VERSION 5.8 ;
BUSBITCHARS "[]" ;
DIVIDERCHAR "/" ;
UNITS
    DATABASE MICRONS 1000 ;
END UNITS

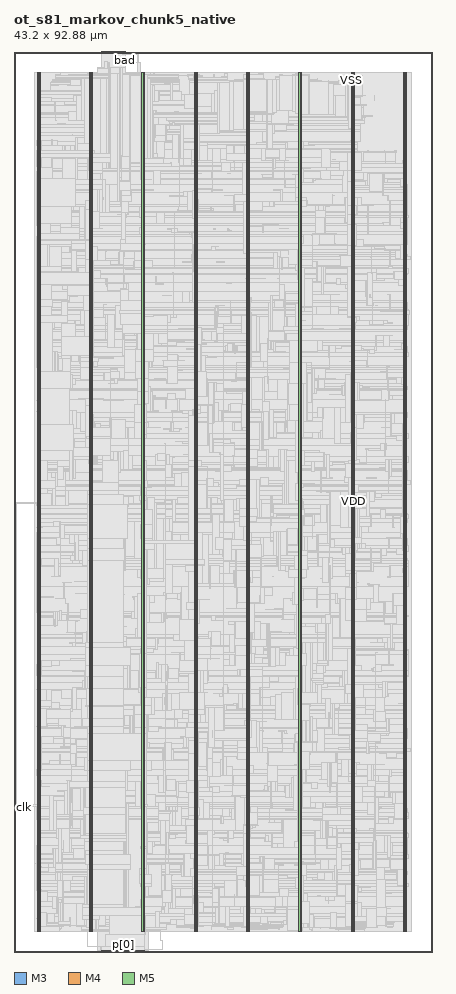
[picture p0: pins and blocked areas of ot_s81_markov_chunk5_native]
MACRO ot_s81_markov_chunk5_native
  FOREIGN ot_s81_markov_chunk5_native 0 0 ;
  CLASS BLOCK ;
  SIZE 43.2 BY 92.88 ;
  PIN bad
    DIRECTION OUTPUT ;
    USE SIGNAL ;
    PORT
      LAYER M3 ;
        RECT  11.448 92.736 11.466 92.88 ;
    END
  END bad
  PIN clk
    DIRECTION INPUT ;
    USE SIGNAL ;
    PORT
      LAYER M4 ;
        RECT  0 14.88 0.192 14.904 ;
    END
  END clk
  PIN p[0]
    DIRECTION INPUT ;
    USE SIGNAL ;
    PORT
      LAYER M3 ;
        RECT  11.304 0 11.322 0.144 ;
    END
  END p[0]
  PIN p[10]
    DIRECTION INPUT ;
    USE SIGNAL ;
    PORT
      LAYER M3 ;
        RECT  12.024 0 12.042 0.144 ;
    END
  END p[10]
  PIN p[11]
    DIRECTION INPUT ;
    USE SIGNAL ;
    PORT
      LAYER M5 ;
        RECT  12.048 0 12.072 0.192 ;
    END
  END p[11]
  PIN p[12]
    DIRECTION INPUT ;
    USE SIGNAL ;
    PORT
      LAYER M3 ;
        RECT  12.168 0 12.186 0.144 ;
    END
  END p[12]
  PIN p[13]
    DIRECTION INPUT ;
    USE SIGNAL ;
    PORT
      LAYER M5 ;
        RECT  12.192 0 12.216 0.192 ;
    END
  END p[13]
  PIN p[14]
    DIRECTION INPUT ;
    USE SIGNAL ;
    PORT
      LAYER M3 ;
        RECT  12.312 0 12.33 0.144 ;
    END
  END p[14]
  PIN p[15]
    DIRECTION INPUT ;
    USE SIGNAL ;
    PORT
      LAYER M5 ;
        RECT  12.336 0 12.36 0.192 ;
    END
  END p[15]
  PIN p[16]
    DIRECTION INPUT ;
    USE SIGNAL ;
    PORT
      LAYER M3 ;
        RECT  12.456 0 12.474 0.144 ;
    END
  END p[16]
  PIN p[17]
    DIRECTION INPUT ;
    USE SIGNAL ;
    PORT
      LAYER M5 ;
        RECT  12.48 0 12.504 0.192 ;
    END
  END p[17]
  PIN p[18]
    DIRECTION INPUT ;
    USE SIGNAL ;
    PORT
      LAYER M3 ;
        RECT  12.6 0 12.618 0.144 ;
    END
  END p[18]
  PIN p[19]
    DIRECTION INPUT ;
    USE SIGNAL ;
    PORT
      LAYER M5 ;
        RECT  12.624 0 12.648 0.192 ;
    END
  END p[19]
  PIN p[1]
    DIRECTION INPUT ;
    USE SIGNAL ;
    PORT
      LAYER M5 ;
        RECT  11.328 0 11.352 0.192 ;
    END
  END p[1]
  PIN p[20]
    DIRECTION INPUT ;
    USE SIGNAL ;
    PORT
      LAYER M3 ;
        RECT  12.744 0 12.762 0.144 ;
    END
  END p[20]
  PIN p[21]
    DIRECTION INPUT ;
    USE SIGNAL ;
    PORT
      LAYER M5 ;
        RECT  12.768 0 12.792 0.192 ;
    END
  END p[21]
  PIN p[22]
    DIRECTION INPUT ;
    USE SIGNAL ;
    PORT
      LAYER M3 ;
        RECT  12.888 0 12.906 0.144 ;
    END
  END p[22]
  PIN p[23]
    DIRECTION INPUT ;
    USE SIGNAL ;
    PORT
      LAYER M5 ;
        RECT  12.912 0 12.936 0.192 ;
    END
  END p[23]
  PIN p[24]
    DIRECTION INPUT ;
    USE SIGNAL ;
    PORT
      LAYER M3 ;
        RECT  13.032 0 13.05 0.144 ;
    END
  END p[24]
  PIN p[25]
    DIRECTION INPUT ;
    USE SIGNAL ;
    PORT
      LAYER M5 ;
        RECT  13.056 0 13.08 0.192 ;
    END
  END p[25]
  PIN p[26]
    DIRECTION INPUT ;
    USE SIGNAL ;
    PORT
      LAYER M3 ;
        RECT  13.176 0 13.194 0.144 ;
    END
  END p[26]
  PIN p[27]
    DIRECTION INPUT ;
    USE SIGNAL ;
    PORT
      LAYER M5 ;
        RECT  13.2 0 13.224 0.192 ;
    END
  END p[27]
  PIN p[28]
    DIRECTION INPUT ;
    USE SIGNAL ;
    PORT
      LAYER M3 ;
        RECT  13.32 0 13.338 0.144 ;
    END
  END p[28]
  PIN p[29]
    DIRECTION INPUT ;
    USE SIGNAL ;
    PORT
      LAYER M5 ;
        RECT  13.344 0 13.368 0.192 ;
    END
  END p[29]
  PIN p[2]
    DIRECTION INPUT ;
    USE SIGNAL ;
    PORT
      LAYER M3 ;
        RECT  11.448 0 11.466 0.144 ;
    END
  END p[2]
  PIN p[30]
    DIRECTION INPUT ;
    USE SIGNAL ;
    PORT
      LAYER M3 ;
        RECT  13.464 0 13.482 0.144 ;
    END
  END p[30]
  PIN p[31]
    DIRECTION INPUT ;
    USE SIGNAL ;
    PORT
      LAYER M5 ;
        RECT  13.488 0 13.512 0.192 ;
    END
  END p[31]
  PIN p[3]
    DIRECTION INPUT ;
    USE SIGNAL ;
    PORT
      LAYER M5 ;
        RECT  11.472 0 11.496 0.192 ;
    END
  END p[3]
  PIN p[4]
    DIRECTION INPUT ;
    USE SIGNAL ;
    PORT
      LAYER M3 ;
        RECT  11.592 0 11.61 0.144 ;
    END
  END p[4]
  PIN p[5]
    DIRECTION INPUT ;
    USE SIGNAL ;
    PORT
      LAYER M5 ;
        RECT  11.616 0 11.64 0.192 ;
    END
  END p[5]
  PIN p[6]
    DIRECTION INPUT ;
    USE SIGNAL ;
    PORT
      LAYER M3 ;
        RECT  11.736 0 11.754 0.144 ;
    END
  END p[6]
  PIN p[7]
    DIRECTION INPUT ;
    USE SIGNAL ;
    PORT
      LAYER M5 ;
        RECT  11.76 0 11.784 0.192 ;
    END
  END p[7]
  PIN p[8]
    DIRECTION INPUT ;
    USE SIGNAL ;
    PORT
      LAYER M3 ;
        RECT  11.88 0 11.898 0.144 ;
    END
  END p[8]
  PIN p[9]
    DIRECTION INPUT ;
    USE SIGNAL ;
    PORT
      LAYER M5 ;
        RECT  11.904 0 11.928 0.192 ;
    END
  END p[9]
  PIN rst_n
    DIRECTION INPUT ;
    USE SIGNAL ;
    PORT
      LAYER M4 ;
        RECT  0 15.024 0.192 15.048 ;
    END
  END rst_n
  PIN sum[0]
    DIRECTION INPUT ;
    USE SIGNAL ;
    PORT
      LAYER M3 ;
        RECT  9 0 9.018 0.144 ;
    END
  END sum[0]
  PIN sum[10]
    DIRECTION INPUT ;
    USE SIGNAL ;
    PORT
      LAYER M3 ;
        RECT  9.72 0 9.738 0.144 ;
    END
  END sum[10]
  PIN sum[11]
    DIRECTION INPUT ;
    USE SIGNAL ;
    PORT
      LAYER M5 ;
        RECT  9.744 0 9.768 0.192 ;
    END
  END sum[11]
  PIN sum[12]
    DIRECTION INPUT ;
    USE SIGNAL ;
    PORT
      LAYER M3 ;
        RECT  9.864 0 9.882 0.144 ;
    END
  END sum[12]
  PIN sum[13]
    DIRECTION INPUT ;
    USE SIGNAL ;
    PORT
      LAYER M5 ;
        RECT  9.888 0 9.912 0.192 ;
    END
  END sum[13]
  PIN sum[14]
    DIRECTION INPUT ;
    USE SIGNAL ;
    PORT
      LAYER M3 ;
        RECT  10.008 0 10.026 0.144 ;
    END
  END sum[14]
  PIN sum[15]
    DIRECTION INPUT ;
    USE SIGNAL ;
    PORT
      LAYER M5 ;
        RECT  10.032 0 10.056 0.192 ;
    END
  END sum[15]
  PIN sum[16]
    DIRECTION INPUT ;
    USE SIGNAL ;
    PORT
      LAYER M3 ;
        RECT  10.152 0 10.17 0.144 ;
    END
  END sum[16]
  PIN sum[17]
    DIRECTION INPUT ;
    USE SIGNAL ;
    PORT
      LAYER M5 ;
        RECT  10.176 0 10.2 0.192 ;
    END
  END sum[17]
  PIN sum[18]
    DIRECTION INPUT ;
    USE SIGNAL ;
    PORT
      LAYER M3 ;
        RECT  10.296 0 10.314 0.144 ;
    END
  END sum[18]
  PIN sum[19]
    DIRECTION INPUT ;
    USE SIGNAL ;
    PORT
      LAYER M5 ;
        RECT  10.32 0 10.344 0.192 ;
    END
  END sum[19]
  PIN sum[1]
    DIRECTION INPUT ;
    USE SIGNAL ;
    PORT
      LAYER M5 ;
        RECT  9.024 0 9.048 0.192 ;
    END
  END sum[1]
  PIN sum[20]
    DIRECTION INPUT ;
    USE SIGNAL ;
    PORT
      LAYER M3 ;
        RECT  10.44 0 10.458 0.144 ;
    END
  END sum[20]
  PIN sum[21]
    DIRECTION INPUT ;
    USE SIGNAL ;
    PORT
      LAYER M5 ;
        RECT  10.464 0 10.488 0.192 ;
    END
  END sum[21]
  PIN sum[22]
    DIRECTION INPUT ;
    USE SIGNAL ;
    PORT
      LAYER M3 ;
        RECT  10.584 0 10.602 0.144 ;
    END
  END sum[22]
  PIN sum[23]
    DIRECTION INPUT ;
    USE SIGNAL ;
    PORT
      LAYER M5 ;
        RECT  10.608 0 10.632 0.192 ;
    END
  END sum[23]
  PIN sum[24]
    DIRECTION INPUT ;
    USE SIGNAL ;
    PORT
      LAYER M3 ;
        RECT  10.728 0 10.746 0.144 ;
    END
  END sum[24]
  PIN sum[25]
    DIRECTION INPUT ;
    USE SIGNAL ;
    PORT
      LAYER M5 ;
        RECT  10.752 0 10.776 0.192 ;
    END
  END sum[25]
  PIN sum[26]
    DIRECTION INPUT ;
    USE SIGNAL ;
    PORT
      LAYER M3 ;
        RECT  10.872 0 10.89 0.144 ;
    END
  END sum[26]
  PIN sum[27]
    DIRECTION INPUT ;
    USE SIGNAL ;
    PORT
      LAYER M5 ;
        RECT  10.896 0 10.92 0.192 ;
    END
  END sum[27]
  PIN sum[28]
    DIRECTION INPUT ;
    USE SIGNAL ;
    PORT
      LAYER M3 ;
        RECT  11.016 0 11.034 0.144 ;
    END
  END sum[28]
  PIN sum[29]
    DIRECTION INPUT ;
    USE SIGNAL ;
    PORT
      LAYER M5 ;
        RECT  11.04 0 11.064 0.192 ;
    END
  END sum[29]
  PIN sum[2]
    DIRECTION INPUT ;
    USE SIGNAL ;
    PORT
      LAYER M3 ;
        RECT  9.144 0 9.162 0.144 ;
    END
  END sum[2]
  PIN sum[30]
    DIRECTION INPUT ;
    USE SIGNAL ;
    PORT
      LAYER M3 ;
        RECT  11.16 0 11.178 0.144 ;
    END
  END sum[30]
  PIN sum[31]
    DIRECTION INPUT ;
    USE SIGNAL ;
    PORT
      LAYER M5 ;
        RECT  11.184 0 11.208 0.192 ;
    END
  END sum[31]
  PIN sum[3]
    DIRECTION INPUT ;
    USE SIGNAL ;
    PORT
      LAYER M5 ;
        RECT  9.168 0 9.192 0.192 ;
    END
  END sum[3]
  PIN sum[4]
    DIRECTION INPUT ;
    USE SIGNAL ;
    PORT
      LAYER M3 ;
        RECT  9.288 0 9.306 0.144 ;
    END
  END sum[4]
  PIN sum[5]
    DIRECTION INPUT ;
    USE SIGNAL ;
    PORT
      LAYER M5 ;
        RECT  9.312 0 9.336 0.192 ;
    END
  END sum[5]
  PIN sum[6]
    DIRECTION INPUT ;
    USE SIGNAL ;
    PORT
      LAYER M3 ;
        RECT  9.432 0 9.45 0.144 ;
    END
  END sum[6]
  PIN sum[7]
    DIRECTION INPUT ;
    USE SIGNAL ;
    PORT
      LAYER M5 ;
        RECT  9.456 0 9.48 0.192 ;
    END
  END sum[7]
  PIN sum[8]
    DIRECTION INPUT ;
    USE SIGNAL ;
    PORT
      LAYER M3 ;
        RECT  9.576 0 9.594 0.144 ;
    END
  END sum[8]
  PIN sum[9]
    DIRECTION INPUT ;
    USE SIGNAL ;
    PORT
      LAYER M5 ;
        RECT  9.6 0 9.624 0.192 ;
    END
  END sum[9]
  PIN vin
    DIRECTION INPUT ;
    USE SIGNAL ;
    PORT
      LAYER M4 ;
        RECT  0 15.168 0.192 15.192 ;
    END
  END vin
  PIN vout
    DIRECTION OUTPUT ;
    USE SIGNAL ;
    PORT
      LAYER M3 ;
        RECT  11.304 92.736 11.322 92.88 ;
    END
  END vout
  PIN y[0]
    DIRECTION OUTPUT ;
    USE SIGNAL ;
    PORT
      LAYER M3 ;
        RECT  9 92.736 9.018 92.88 ;
    END
  END y[0]
  PIN y[10]
    DIRECTION OUTPUT ;
    USE SIGNAL ;
    PORT
      LAYER M3 ;
        RECT  9.72 92.736 9.738 92.88 ;
    END
  END y[10]
  PIN y[11]
    DIRECTION OUTPUT ;
    USE SIGNAL ;
    PORT
      LAYER M5 ;
        RECT  9.744 92.688 9.768 92.88 ;
    END
  END y[11]
  PIN y[12]
    DIRECTION OUTPUT ;
    USE SIGNAL ;
    PORT
      LAYER M3 ;
        RECT  9.864 92.736 9.882 92.88 ;
    END
  END y[12]
  PIN y[13]
    DIRECTION OUTPUT ;
    USE SIGNAL ;
    PORT
      LAYER M5 ;
        RECT  9.888 92.688 9.912 92.88 ;
    END
  END y[13]
  PIN y[14]
    DIRECTION OUTPUT ;
    USE SIGNAL ;
    PORT
      LAYER M3 ;
        RECT  10.008 92.736 10.026 92.88 ;
    END
  END y[14]
  PIN y[15]
    DIRECTION OUTPUT ;
    USE SIGNAL ;
    PORT
      LAYER M5 ;
        RECT  10.032 92.688 10.056 92.88 ;
    END
  END y[15]
  PIN y[16]
    DIRECTION OUTPUT ;
    USE SIGNAL ;
    PORT
      LAYER M3 ;
        RECT  10.152 92.736 10.17 92.88 ;
    END
  END y[16]
  PIN y[17]
    DIRECTION OUTPUT ;
    USE SIGNAL ;
    PORT
      LAYER M5 ;
        RECT  10.176 92.688 10.2 92.88 ;
    END
  END y[17]
  PIN y[18]
    DIRECTION OUTPUT ;
    USE SIGNAL ;
    PORT
      LAYER M3 ;
        RECT  10.296 92.736 10.314 92.88 ;
    END
  END y[18]
  PIN y[19]
    DIRECTION OUTPUT ;
    USE SIGNAL ;
    PORT
      LAYER M5 ;
        RECT  10.32 92.688 10.344 92.88 ;
    END
  END y[19]
  PIN y[1]
    DIRECTION OUTPUT ;
    USE SIGNAL ;
    PORT
      LAYER M5 ;
        RECT  9.024 92.688 9.048 92.88 ;
    END
  END y[1]
  PIN y[20]
    DIRECTION OUTPUT ;
    USE SIGNAL ;
    PORT
      LAYER M3 ;
        RECT  10.44 92.736 10.458 92.88 ;
    END
  END y[20]
  PIN y[21]
    DIRECTION OUTPUT ;
    USE SIGNAL ;
    PORT
      LAYER M5 ;
        RECT  10.464 92.688 10.488 92.88 ;
    END
  END y[21]
  PIN y[22]
    DIRECTION OUTPUT ;
    USE SIGNAL ;
    PORT
      LAYER M3 ;
        RECT  10.584 92.736 10.602 92.88 ;
    END
  END y[22]
  PIN y[23]
    DIRECTION OUTPUT ;
    USE SIGNAL ;
    PORT
      LAYER M5 ;
        RECT  10.608 92.688 10.632 92.88 ;
    END
  END y[23]
  PIN y[24]
    DIRECTION OUTPUT ;
    USE SIGNAL ;
    PORT
      LAYER M3 ;
        RECT  10.728 92.736 10.746 92.88 ;
    END
  END y[24]
  PIN y[25]
    DIRECTION OUTPUT ;
    USE SIGNAL ;
    PORT
      LAYER M5 ;
        RECT  10.752 92.688 10.776 92.88 ;
    END
  END y[25]
  PIN y[26]
    DIRECTION OUTPUT ;
    USE SIGNAL ;
    PORT
      LAYER M3 ;
        RECT  10.872 92.736 10.89 92.88 ;
    END
  END y[26]
  PIN y[27]
    DIRECTION OUTPUT ;
    USE SIGNAL ;
    PORT
      LAYER M5 ;
        RECT  10.896 92.688 10.92 92.88 ;
    END
  END y[27]
  PIN y[28]
    DIRECTION OUTPUT ;
    USE SIGNAL ;
    PORT
      LAYER M3 ;
        RECT  11.016 92.736 11.034 92.88 ;
    END
  END y[28]
  PIN y[29]
    DIRECTION OUTPUT ;
    USE SIGNAL ;
    PORT
      LAYER M5 ;
        RECT  11.04 92.688 11.064 92.88 ;
    END
  END y[29]
  PIN y[2]
    DIRECTION OUTPUT ;
    USE SIGNAL ;
    PORT
      LAYER M3 ;
        RECT  9.144 92.736 9.162 92.88 ;
    END
  END y[2]
  PIN y[30]
    DIRECTION OUTPUT ;
    USE SIGNAL ;
    PORT
      LAYER M3 ;
        RECT  11.16 92.736 11.178 92.88 ;
    END
  END y[30]
  PIN y[31]
    DIRECTION OUTPUT ;
    USE SIGNAL ;
    PORT
      LAYER M5 ;
        RECT  11.184 92.688 11.208 92.88 ;
    END
  END y[31]
  PIN y[3]
    DIRECTION OUTPUT ;
    USE SIGNAL ;
    PORT
      LAYER M5 ;
        RECT  9.168 92.688 9.192 92.88 ;
    END
  END y[3]
  PIN y[4]
    DIRECTION OUTPUT ;
    USE SIGNAL ;
    PORT
      LAYER M3 ;
        RECT  9.288 92.736 9.306 92.88 ;
    END
  END y[4]
  PIN y[5]
    DIRECTION OUTPUT ;
    USE SIGNAL ;
    PORT
      LAYER M5 ;
        RECT  9.312 92.688 9.336 92.88 ;
    END
  END y[5]
  PIN y[6]
    DIRECTION OUTPUT ;
    USE SIGNAL ;
    PORT
      LAYER M3 ;
        RECT  9.432 92.736 9.45 92.88 ;
    END
  END y[6]
  PIN y[7]
    DIRECTION OUTPUT ;
    USE SIGNAL ;
    PORT
      LAYER M5 ;
        RECT  9.456 92.688 9.48 92.88 ;
    END
  END y[7]
  PIN y[8]
    DIRECTION OUTPUT ;
    USE SIGNAL ;
    PORT
      LAYER M3 ;
        RECT  9.576 92.736 9.594 92.88 ;
    END
  END y[8]
  PIN y[9]
    DIRECTION OUTPUT ;
    USE SIGNAL ;
    PORT
      LAYER M5 ;
        RECT  9.6 92.688 9.624 92.88 ;
    END
  END y[9]
  PIN VDD
    DIRECTION INOUT ;
    USE POWER ;
    PORT
      LAYER M5 ;
        RECT  40.392 2.151 40.512 90.729 ;
        RECT  34.992 2.151 35.112 90.729 ;
        RECT  29.592 2.151 29.712 90.729 ;
        RECT  24.192 2.151 24.312 90.729 ;
        RECT  18.792 2.151 18.912 90.729 ;
        RECT  13.392 2.151 13.512 90.729 ;
        RECT  7.992 2.151 8.112 90.729 ;
        RECT  2.592 2.151 2.712 90.729 ;
    END
  END VDD
  PIN VSS
    DIRECTION INOUT ;
    USE GROUND ;
    PORT
      LAYER M5 ;
        RECT  40.2 2.137 40.32 90.743 ;
        RECT  34.8 2.137 34.92 90.743 ;
        RECT  29.4 2.137 29.52 90.743 ;
        RECT  24 2.137 24.12 90.743 ;
        RECT  18.6 2.137 18.72 90.743 ;
        RECT  13.2 2.137 13.32 90.743 ;
        RECT  7.8 2.137 7.92 90.743 ;
        RECT  2.4 2.137 2.52 90.743 ;
    END
  END VSS
  # OT_OBS_CLOSED layer=M5 d_um=1.536 added=399
  OBS
    LAYER RVTN ;
     RECT  2.16 2.16 41.04 2.295 ;
     RECT  2.16 2.565 41.04 2.835 ;
     RECT  2.16 3.105 41.04 3.375 ;
     RECT  2.16 3.645 41.04 3.915 ;
     RECT  2.16 4.185 41.04 4.455 ;
     RECT  2.16 4.725 41.04 4.995 ;
     RECT  2.16 5.265 41.04 5.535 ;
     RECT  2.16 5.805 41.04 6.075 ;
     RECT  2.16 6.345 41.04 6.615 ;
     RECT  2.16 6.885 41.04 7.155 ;
     RECT  2.16 7.425 41.04 7.695 ;
     RECT  2.16 7.965 41.04 8.235 ;
     RECT  2.16 8.505 41.04 8.775 ;
     RECT  2.16 9.045 41.04 9.315 ;
     RECT  2.16 9.585 41.04 9.855 ;
     RECT  2.16 10.125 41.04 10.395 ;
     RECT  2.16 10.665 41.04 10.935 ;
     RECT  2.16 11.205 41.04 11.475 ;
     RECT  2.16 11.745 41.04 12.015 ;
     RECT  2.16 12.285 41.04 12.555 ;
     RECT  2.16 12.825 41.04 13.095 ;
     RECT  2.16 13.365 41.04 13.635 ;
     RECT  2.16 13.905 41.04 14.175 ;
     RECT  2.16 14.445 41.04 14.715 ;
     RECT  2.16 14.985 41.04 15.255 ;
     RECT  2.16 15.525 41.04 15.795 ;
     RECT  2.16 16.065 41.04 16.335 ;
     RECT  2.16 16.605 41.04 16.875 ;
     RECT  2.16 17.145 41.04 17.415 ;
     RECT  2.16 17.685 41.04 17.955 ;
     RECT  2.16 18.225 41.04 18.495 ;
     RECT  2.16 18.765 41.04 19.035 ;
     RECT  2.16 19.305 41.04 19.575 ;
     RECT  2.16 19.845 41.04 20.115 ;
     RECT  2.16 20.385 41.04 20.655 ;
     RECT  2.16 20.925 41.04 21.195 ;
     RECT  2.16 21.465 41.04 21.735 ;
     RECT  2.16 22.005 41.04 22.275 ;
     RECT  2.16 22.545 41.04 22.815 ;
     RECT  2.16 23.085 41.04 23.355 ;
     RECT  2.16 23.625 41.04 23.895 ;
     RECT  2.16 24.165 41.04 24.435 ;
     RECT  2.16 24.705 41.04 24.975 ;
     RECT  2.16 25.245 41.04 25.515 ;
     RECT  2.16 25.785 41.04 26.055 ;
     RECT  2.16 26.325 41.04 26.595 ;
     RECT  2.16 26.865 41.04 27.135 ;
     RECT  2.16 27.405 41.04 27.675 ;
     RECT  2.16 27.945 41.04 28.215 ;
     RECT  2.16 28.485 41.04 28.755 ;
     RECT  2.16 29.025 41.04 29.295 ;
     RECT  2.16 29.565 41.04 29.835 ;
     RECT  2.16 30.105 41.04 30.375 ;
     RECT  2.16 30.645 41.04 30.915 ;
     RECT  2.16 31.185 41.04 31.455 ;
     RECT  2.16 31.725 41.04 31.995 ;
     RECT  2.16 32.265 41.04 32.535 ;
     RECT  2.16 32.805 41.04 33.075 ;
     RECT  2.16 33.345 41.04 33.615 ;
     RECT  2.16 33.885 41.04 34.155 ;
     RECT  2.16 34.425 41.04 34.695 ;
     RECT  2.16 34.965 41.04 35.235 ;
     RECT  2.16 35.505 41.04 35.775 ;
     RECT  2.16 36.045 41.04 36.315 ;
     RECT  2.16 36.585 41.04 36.855 ;
     RECT  2.16 37.125 41.04 37.395 ;
     RECT  2.16 37.665 41.04 37.935 ;
     RECT  2.16 38.205 41.04 38.475 ;
     RECT  2.16 38.745 41.04 39.015 ;
     RECT  2.16 39.285 41.04 39.555 ;
     RECT  2.16 39.825 41.04 40.095 ;
     RECT  2.16 40.365 41.04 40.635 ;
     RECT  2.16 40.905 41.04 41.175 ;
     RECT  2.16 41.445 41.04 41.715 ;
     RECT  2.16 41.985 41.04 42.255 ;
     RECT  2.16 42.525 41.04 42.795 ;
     RECT  2.16 43.065 41.04 43.335 ;
     RECT  2.16 43.605 41.04 43.875 ;
     RECT  2.16 44.145 41.04 44.415 ;
     RECT  2.16 44.685 41.04 44.955 ;
     RECT  2.16 45.225 41.04 45.495 ;
     RECT  2.16 45.765 41.04 46.035 ;
     RECT  2.16 46.305 41.04 46.575 ;
     RECT  2.16 46.845 41.04 47.115 ;
     RECT  2.16 47.385 41.04 47.655 ;
     RECT  2.16 47.925 41.04 48.195 ;
     RECT  2.16 48.465 41.04 48.735 ;
     RECT  2.16 49.005 41.04 49.275 ;
     RECT  2.16 49.545 41.04 49.815 ;
     RECT  2.16 50.085 41.04 50.355 ;
     RECT  2.16 50.625 41.04 50.895 ;
     RECT  2.16 51.165 41.04 51.435 ;
     RECT  2.16 51.705 41.04 51.975 ;
     RECT  2.16 52.245 41.04 52.515 ;
     RECT  2.16 52.785 41.04 53.055 ;
     RECT  2.16 53.325 41.04 53.595 ;
     RECT  2.16 53.865 41.04 54.135 ;
     RECT  2.16 54.405 41.04 54.675 ;
     RECT  2.16 54.945 41.04 55.215 ;
     RECT  2.16 55.485 41.04 55.755 ;
     RECT  2.16 56.025 41.04 56.295 ;
     RECT  2.16 56.565 41.04 56.835 ;
     RECT  2.16 57.105 41.04 57.375 ;
     RECT  2.16 57.645 41.04 57.915 ;
     RECT  2.16 58.185 41.04 58.455 ;
     RECT  2.16 58.725 41.04 58.995 ;
     RECT  2.16 59.265 41.04 59.535 ;
     RECT  2.16 59.805 41.04 60.075 ;
     RECT  2.16 60.345 41.04 60.615 ;
     RECT  2.16 60.885 41.04 61.155 ;
     RECT  2.16 61.425 41.04 61.695 ;
     RECT  2.16 61.965 41.04 62.235 ;
     RECT  2.16 62.505 41.04 62.775 ;
     RECT  2.16 63.045 41.04 63.315 ;
     RECT  2.16 63.585 41.04 63.855 ;
     RECT  2.16 64.125 41.04 64.395 ;
     RECT  2.16 64.665 41.04 64.935 ;
     RECT  2.16 65.205 41.04 65.475 ;
     RECT  2.16 65.745 41.04 66.015 ;
     RECT  2.16 66.285 41.04 66.555 ;
     RECT  2.16 66.825 41.04 67.095 ;
     RECT  2.16 67.365 41.04 67.635 ;
     RECT  2.16 67.905 41.04 68.175 ;
     RECT  2.16 68.445 41.04 68.715 ;
     RECT  2.16 68.985 41.04 69.255 ;
     RECT  2.16 69.525 41.04 69.795 ;
     RECT  2.16 70.065 41.04 70.335 ;
     RECT  2.16 70.605 41.04 70.875 ;
     RECT  2.16 71.145 41.04 71.415 ;
     RECT  2.16 71.685 41.04 71.955 ;
     RECT  2.16 72.225 41.04 72.495 ;
     RECT  2.16 72.765 41.04 73.035 ;
     RECT  2.16 73.305 41.04 73.575 ;
     RECT  2.16 73.845 41.04 74.115 ;
     RECT  2.16 74.385 41.04 74.655 ;
     RECT  2.16 74.925 41.04 75.195 ;
     RECT  2.16 75.465 41.04 75.735 ;
     RECT  2.16 76.005 41.04 76.275 ;
     RECT  2.16 76.545 41.04 76.815 ;
     RECT  2.16 77.085 41.04 77.355 ;
     RECT  2.16 77.625 41.04 77.895 ;
     RECT  2.16 78.165 41.04 78.435 ;
     RECT  2.16 78.705 41.04 78.975 ;
     RECT  2.16 79.245 41.04 79.515 ;
     RECT  2.16 79.785 41.04 80.055 ;
     RECT  2.16 80.325 41.04 80.595 ;
     RECT  2.16 80.865 41.04 81.135 ;
     RECT  2.16 81.405 41.04 81.675 ;
     RECT  2.16 81.945 41.04 82.215 ;
     RECT  2.16 82.485 41.04 82.755 ;
     RECT  2.16 83.025 41.04 83.295 ;
     RECT  2.16 83.565 41.04 83.835 ;
     RECT  2.16 84.105 41.04 84.375 ;
     RECT  2.16 84.645 41.04 84.915 ;
     RECT  2.16 85.185 41.04 85.455 ;
     RECT  2.16 85.725 41.04 85.995 ;
     RECT  2.16 86.265 41.04 86.535 ;
     RECT  2.16 86.805 41.04 87.075 ;
     RECT  2.16 87.345 41.04 87.615 ;
     RECT  2.16 87.885 41.04 88.155 ;
     RECT  2.16 88.425 41.04 88.695 ;
     RECT  2.16 88.965 41.04 89.235 ;
     RECT  2.16 89.505 41.04 89.775 ;
     RECT  2.16 90.045 41.04 90.315 ;
     RECT  2.16 90.585 41.04 90.72 ;
    LAYER RVTP ;
     RECT  2.16 2.295 41.04 2.565 ;
     RECT  2.16 2.835 41.04 3.105 ;
     RECT  2.16 3.375 41.04 3.645 ;
     RECT  2.16 3.915 41.04 4.185 ;
     RECT  2.16 4.455 41.04 4.725 ;
     RECT  2.16 4.995 41.04 5.265 ;
     RECT  2.16 5.535 41.04 5.805 ;
     RECT  2.16 6.075 41.04 6.345 ;
     RECT  2.16 6.615 41.04 6.885 ;
     RECT  2.16 7.155 41.04 7.425 ;
     RECT  2.16 7.695 41.04 7.965 ;
     RECT  2.16 8.235 41.04 8.505 ;
     RECT  2.16 8.775 41.04 9.045 ;
     RECT  2.16 9.315 41.04 9.585 ;
     RECT  2.16 9.855 41.04 10.125 ;
     RECT  2.16 10.395 41.04 10.665 ;
     RECT  2.16 10.935 41.04 11.205 ;
     RECT  2.16 11.475 41.04 11.745 ;
     RECT  2.16 12.015 41.04 12.285 ;
     RECT  2.16 12.555 41.04 12.825 ;
     RECT  2.16 13.095 41.04 13.365 ;
     RECT  2.16 13.635 41.04 13.905 ;
     RECT  2.16 14.175 41.04 14.445 ;
     RECT  2.16 14.715 41.04 14.985 ;
     RECT  2.16 15.255 41.04 15.525 ;
     RECT  2.16 15.795 41.04 16.065 ;
     RECT  2.16 16.335 41.04 16.605 ;
     RECT  2.16 16.875 41.04 17.145 ;
     RECT  2.16 17.415 41.04 17.685 ;
     RECT  2.16 17.955 41.04 18.225 ;
     RECT  2.16 18.495 41.04 18.765 ;
     RECT  2.16 19.035 41.04 19.305 ;
     RECT  2.16 19.575 41.04 19.845 ;
     RECT  2.16 20.115 41.04 20.385 ;
     RECT  2.16 20.655 41.04 20.925 ;
     RECT  2.16 21.195 41.04 21.465 ;
     RECT  2.16 21.735 41.04 22.005 ;
     RECT  2.16 22.275 41.04 22.545 ;
     RECT  2.16 22.815 41.04 23.085 ;
     RECT  2.16 23.355 41.04 23.625 ;
     RECT  2.16 23.895 41.04 24.165 ;
     RECT  2.16 24.435 41.04 24.705 ;
     RECT  2.16 24.975 41.04 25.245 ;
     RECT  2.16 25.515 41.04 25.785 ;
     RECT  2.16 26.055 41.04 26.325 ;
     RECT  2.16 26.595 41.04 26.865 ;
     RECT  2.16 27.135 41.04 27.405 ;
     RECT  2.16 27.675 41.04 27.945 ;
     RECT  2.16 28.215 41.04 28.485 ;
     RECT  2.16 28.755 41.04 29.025 ;
     RECT  2.16 29.295 41.04 29.565 ;
     RECT  2.16 29.835 41.04 30.105 ;
     RECT  2.16 30.375 41.04 30.645 ;
     RECT  2.16 30.915 41.04 31.185 ;
     RECT  2.16 31.455 41.04 31.725 ;
     RECT  2.16 31.995 41.04 32.265 ;
     RECT  2.16 32.535 41.04 32.805 ;
     RECT  2.16 33.075 41.04 33.345 ;
     RECT  2.16 33.615 41.04 33.885 ;
     RECT  2.16 34.155 41.04 34.425 ;
     RECT  2.16 34.695 41.04 34.965 ;
     RECT  2.16 35.235 41.04 35.505 ;
     RECT  2.16 35.775 41.04 36.045 ;
     RECT  2.16 36.315 41.04 36.585 ;
     RECT  2.16 36.855 41.04 37.125 ;
     RECT  2.16 37.395 41.04 37.665 ;
     RECT  2.16 37.935 41.04 38.205 ;
     RECT  2.16 38.475 41.04 38.745 ;
     RECT  2.16 39.015 41.04 39.285 ;
     RECT  2.16 39.555 41.04 39.825 ;
     RECT  2.16 40.095 41.04 40.365 ;
     RECT  2.16 40.635 41.04 40.905 ;
     RECT  2.16 41.175 41.04 41.445 ;
     RECT  2.16 41.715 41.04 41.985 ;
     RECT  2.16 42.255 41.04 42.525 ;
     RECT  2.16 42.795 41.04 43.065 ;
     RECT  2.16 43.335 41.04 43.605 ;
     RECT  2.16 43.875 41.04 44.145 ;
     RECT  2.16 44.415 41.04 44.685 ;
     RECT  2.16 44.955 41.04 45.225 ;
     RECT  2.16 45.495 41.04 45.765 ;
     RECT  2.16 46.035 41.04 46.305 ;
     RECT  2.16 46.575 41.04 46.845 ;
     RECT  2.16 47.115 41.04 47.385 ;
     RECT  2.16 47.655 41.04 47.925 ;
     RECT  2.16 48.195 41.04 48.465 ;
     RECT  2.16 48.735 41.04 49.005 ;
     RECT  2.16 49.275 41.04 49.545 ;
     RECT  2.16 49.815 41.04 50.085 ;
     RECT  2.16 50.355 41.04 50.625 ;
     RECT  2.16 50.895 41.04 51.165 ;
     RECT  2.16 51.435 41.04 51.705 ;
     RECT  2.16 51.975 41.04 52.245 ;
     RECT  2.16 52.515 41.04 52.785 ;
     RECT  2.16 53.055 41.04 53.325 ;
     RECT  2.16 53.595 41.04 53.865 ;
     RECT  2.16 54.135 41.04 54.405 ;
     RECT  2.16 54.675 41.04 54.945 ;
     RECT  2.16 55.215 41.04 55.485 ;
     RECT  2.16 55.755 41.04 56.025 ;
     RECT  2.16 56.295 41.04 56.565 ;
     RECT  2.16 56.835 41.04 57.105 ;
     RECT  2.16 57.375 41.04 57.645 ;
     RECT  2.16 57.915 41.04 58.185 ;
     RECT  2.16 58.455 41.04 58.725 ;
     RECT  2.16 58.995 41.04 59.265 ;
     RECT  2.16 59.535 41.04 59.805 ;
     RECT  2.16 60.075 41.04 60.345 ;
     RECT  2.16 60.615 41.04 60.885 ;
     RECT  2.16 61.155 41.04 61.425 ;
     RECT  2.16 61.695 41.04 61.965 ;
     RECT  2.16 62.235 41.04 62.505 ;
     RECT  2.16 62.775 41.04 63.045 ;
     RECT  2.16 63.315 41.04 63.585 ;
     RECT  2.16 63.855 41.04 64.125 ;
     RECT  2.16 64.395 41.04 64.665 ;
     RECT  2.16 64.935 41.04 65.205 ;
     RECT  2.16 65.475 41.04 65.745 ;
     RECT  2.16 66.015 41.04 66.285 ;
     RECT  2.16 66.555 41.04 66.825 ;
     RECT  2.16 67.095 41.04 67.365 ;
     RECT  2.16 67.635 41.04 67.905 ;
     RECT  2.16 68.175 41.04 68.445 ;
     RECT  2.16 68.715 41.04 68.985 ;
     RECT  2.16 69.255 41.04 69.525 ;
     RECT  2.16 69.795 41.04 70.065 ;
     RECT  2.16 70.335 41.04 70.605 ;
     RECT  2.16 70.875 41.04 71.145 ;
     RECT  2.16 71.415 41.04 71.685 ;
     RECT  2.16 71.955 41.04 72.225 ;
     RECT  2.16 72.495 41.04 72.765 ;
     RECT  2.16 73.035 41.04 73.305 ;
     RECT  2.16 73.575 41.04 73.845 ;
     RECT  2.16 74.115 41.04 74.385 ;
     RECT  2.16 74.655 41.04 74.925 ;
     RECT  2.16 75.195 41.04 75.465 ;
     RECT  2.16 75.735 41.04 76.005 ;
     RECT  2.16 76.275 41.04 76.545 ;
     RECT  2.16 76.815 41.04 77.085 ;
     RECT  2.16 77.355 41.04 77.625 ;
     RECT  2.16 77.895 41.04 78.165 ;
     RECT  2.16 78.435 41.04 78.705 ;
     RECT  2.16 78.975 41.04 79.245 ;
     RECT  2.16 79.515 41.04 79.785 ;
     RECT  2.16 80.055 41.04 80.325 ;
     RECT  2.16 80.595 41.04 80.865 ;
     RECT  2.16 81.135 41.04 81.405 ;
     RECT  2.16 81.675 41.04 81.945 ;
     RECT  2.16 82.215 41.04 82.485 ;
     RECT  2.16 82.755 41.04 83.025 ;
     RECT  2.16 83.295 41.04 83.565 ;
     RECT  2.16 83.835 41.04 84.105 ;
     RECT  2.16 84.375 41.04 84.645 ;
     RECT  2.16 84.915 41.04 85.185 ;
     RECT  2.16 85.455 41.04 85.725 ;
     RECT  2.16 85.995 41.04 86.265 ;
     RECT  2.16 86.535 41.04 86.805 ;
     RECT  2.16 87.075 41.04 87.345 ;
     RECT  2.16 87.615 41.04 87.885 ;
     RECT  2.16 88.155 41.04 88.425 ;
     RECT  2.16 88.695 41.04 88.965 ;
     RECT  2.16 89.235 41.04 89.505 ;
     RECT  2.16 89.775 41.04 90.045 ;
     RECT  2.16 90.315 41.04 90.585 ;
    LAYER M1 ;
     RECT  2.16 2.151 41.04 90.729 ;
    LAYER M2 ;
     RECT  2.16 2.151 7.555 90.729 ;
     RECT  7.555 2.106 7.691 90.729 ;
     RECT  7.691 2.151 8.851 90.729 ;
     RECT  8.851 2.106 9.211 90.729 ;
     RECT  9.211 1.728 9.319 90.729 ;
     RECT  8.635 0.144 9.599 0.162 ;
     RECT  9.319 1.152 10.031 90.729 ;
     RECT  10.031 1.152 10.651 1.242 ;
     RECT  10.651 0.531 10.895 1.242 ;
     RECT  10.895 1.152 10.939 1.242 ;
     RECT  10.031 2.106 10.939 90.729 ;
     RECT  10.579 91.791 11.011 91.809 ;
     RECT  10.939 1.152 11.155 90.729 ;
     RECT  11.011 91.791 11.155 91.89 ;
     RECT  11.155 1.152 11.183 91.89 ;
     RECT  11.183 2.106 11.255 91.89 ;
     RECT  11.255 91.791 11.399 91.89 ;
     RECT  11.183 1.152 11.759 1.242 ;
     RECT  11.255 2.106 11.759 90.774 ;
     RECT  11.443 0.144 11.939 0.234 ;
     RECT  11.759 1.152 11.939 1.17 ;
     RECT  11.759 2.151 12.335 90.774 ;
     RECT  12.739 1.152 12.839 1.17 ;
     RECT  11.399 91.791 13.019 91.809 ;
     RECT  11.939 0.144 13.027 0.162 ;
     RECT  13.027 0.144 13.099 0.198 ;
     RECT  12.335 2.151 13.171 90.729 ;
     RECT  13.099 0.144 13.199 0.279 ;
     RECT  13.199 0.144 13.667 0.234 ;
     RECT  13.171 2.106 14.135 90.729 ;
     RECT  13.667 0.216 15.323 0.234 ;
     RECT  15.115 1.152 15.323 1.17 ;
     RECT  14.135 2.151 41.04 90.729 ;
    LAYER M3 ;
     RECT  9 0.108 13.482 0.139 ;
     RECT  8.64 0.139 13.662 0.187 ;
     RECT  15.3 0.211 15.318 1.147 ;
     RECT  15.12 1.147 15.318 1.175 ;
     RECT  7.56 0.523 7.578 2.101 ;
     RECT  8.64 0.187 13.914 2.101 ;
     RECT  7.56 2.101 7.686 2.143 ;
     RECT  7.56 2.143 7.905 2.191 ;
     RECT  8.64 2.101 14.13 2.191 ;
     RECT  15.12 1.175 15.138 2.191 ;
     RECT  29.415 2.143 29.505 2.251 ;
     RECT  28.692 2.251 29.505 2.263 ;
     RECT  24.015 2.143 24.105 2.299 ;
     RECT  33.48 2.227 33.498 2.299 ;
     RECT  36.18 2.227 36.198 2.299 ;
     RECT  4.716 2.263 4.734 2.335 ;
     RECT  6.984 2.191 15.138 2.371 ;
     RECT  22.5 2.299 22.518 2.371 ;
     RECT  24.015 2.299 24.57 2.371 ;
     RECT  25.596 2.299 25.614 2.371 ;
     RECT  27.36 2.299 27.378 2.371 ;
     RECT  28.692 2.263 29.754 2.371 ;
     RECT  30.744 2.263 30.762 2.371 ;
     RECT  33.156 2.299 33.642 2.371 ;
     RECT  34.815 2.143 34.905 2.371 ;
     RECT  35.712 2.299 36.198 2.371 ;
     RECT  2.415 2.143 2.505 2.413 ;
     RECT  18.615 2.143 18.705 2.413 ;
     RECT  40.215 2.143 40.305 2.413 ;
     RECT  4.716 2.335 4.842 2.461 ;
     RECT  18.615 2.413 18.897 2.461 ;
     RECT  24.015 2.371 26.19 2.461 ;
     RECT  27.288 2.371 27.378 2.461 ;
     RECT  33.156 2.371 36.198 2.461 ;
     RECT  18.252 2.461 18.897 2.497 ;
     RECT  24.015 2.461 27.378 2.497 ;
     RECT  16.74 2.497 16.758 2.533 ;
     RECT  17.568 2.497 18.897 2.533 ;
     RECT  37.152 2.497 37.17 2.533 ;
     RECT  21.996 2.371 22.698 2.569 ;
     RECT  24.015 2.497 27.702 2.569 ;
     RECT  28.692 2.371 29.79 2.569 ;
     RECT  30.528 2.371 30.762 2.569 ;
     RECT  21.744 2.569 22.698 2.587 ;
     RECT  23.508 2.569 27.702 2.587 ;
     RECT  6.984 2.371 15.714 2.605 ;
     RECT  28.692 2.569 30.762 2.605 ;
     RECT  31.608 2.461 31.626 2.605 ;
     RECT  32.58 2.461 36.27 2.605 ;
     RECT  37.152 2.533 37.494 2.605 ;
     RECT  38.592 2.569 39.078 2.605 ;
     RECT  4.716 2.461 4.914 2.641 ;
     RECT  16.74 2.533 18.897 2.641 ;
     RECT  20.34 2.371 20.358 2.641 ;
     RECT  21.744 2.587 27.702 2.641 ;
     RECT  38.376 2.605 39.078 2.641 ;
     RECT  2.415 2.413 2.697 2.683 ;
     RECT  3.996 2.641 4.914 2.683 ;
     RECT  28.692 2.605 36.27 2.731 ;
     RECT  37.08 2.605 37.494 2.731 ;
     RECT  2.415 2.683 5.094 2.767 ;
     RECT  16.74 2.641 19.53 2.767 ;
     RECT  20.34 2.641 27.81 2.767 ;
     RECT  2.415 2.767 5.706 2.803 ;
     RECT  6.444 2.605 15.75 2.803 ;
     RECT  28.692 2.731 37.638 2.803 ;
     RECT  38.376 2.641 39.15 2.803 ;
     RECT  16.74 2.767 27.81 2.839 ;
     RECT  2.415 2.803 15.75 2.875 ;
     RECT  16.74 2.839 27.882 2.911 ;
     RECT  28.692 2.803 39.15 2.911 ;
     RECT  16.74 2.911 39.15 2.939 ;
     RECT  26.172 2.939 39.15 3.037 ;
     RECT  2.415 2.875 15.966 3.065 ;
     RECT  4.176 3.065 15.966 3.073 ;
     RECT  16.74 2.939 25.398 3.073 ;
     RECT  26.172 3.037 39.222 3.109 ;
     RECT  26.172 3.109 39.33 3.145 ;
     RECT  40.215 2.413 40.497 3.145 ;
     RECT  2.415 3.065 3.438 3.403 ;
     RECT  2.376 3.403 3.438 3.569 ;
     RECT  4.176 3.073 25.398 3.685 ;
     RECT  26.172 3.145 40.497 3.685 ;
     RECT  2.415 3.569 3.438 3.955 ;
     RECT  4.176 3.685 40.497 3.955 ;
     RECT  2.415 3.955 40.497 4.649 ;
     RECT  2.415 4.649 26.946 5.611 ;
     RECT  2.415 5.611 26.982 5.707 ;
     RECT  27.756 4.649 40.497 5.707 ;
     RECT  2.415 5.707 40.497 6.115 ;
     RECT  2.415 6.115 40.554 6.349 ;
     RECT  2.34 6.349 40.554 6.781 ;
     RECT  2.34 6.781 40.662 7.079 ;
     RECT  2.34 7.079 40.554 7.393 ;
     RECT  2.304 7.393 40.554 8.041 ;
     RECT  2.304 8.041 40.59 8.231 ;
     RECT  2.304 8.231 3.546 8.303 ;
     RECT  4.284 8.231 40.59 8.339 ;
     RECT  4.284 8.339 40.497 8.501 ;
     RECT  2.304 8.303 3.51 9.085 ;
     RECT  4.284 8.501 31.662 9.085 ;
     RECT  2.304 9.085 31.662 9.239 ;
     RECT  2.34 9.239 31.662 9.553 ;
     RECT  32.436 8.501 40.497 9.553 ;
     RECT  2.34 9.553 40.497 9.625 ;
     RECT  2.34 9.625 40.734 10.049 ;
     RECT  2.34 10.049 40.626 10.967 ;
     RECT  2.376 10.967 40.626 11.821 ;
     RECT  2.376 11.821 40.698 12.245 ;
     RECT  2.376 12.245 40.626 12.317 ;
     RECT  2.376 12.317 40.497 12.515 ;
     RECT  2.412 12.515 40.497 12.557 ;
     RECT  2.415 12.557 40.497 13.675 ;
     RECT  2.34 13.675 40.497 13.801 ;
     RECT  2.34 13.801 40.734 13.997 ;
     RECT  22.284 13.997 40.734 14.369 ;
     RECT  22.284 14.369 40.59 14.783 ;
     RECT  2.34 13.997 21.51 14.791 ;
     RECT  22.284 14.783 40.497 14.791 ;
     RECT  2.34 14.791 40.497 15.019 ;
     RECT  2.304 15.019 40.497 15.025 ;
     RECT  2.268 15.025 40.497 15.197 ;
     RECT  2.304 15.197 40.497 15.215 ;
     RECT  2.376 15.215 40.497 15.449 ;
     RECT  2.412 15.449 40.497 16.097 ;
     RECT  2.412 16.097 16.938 16.133 ;
     RECT  17.748 16.097 40.497 16.541 ;
     RECT  2.415 16.133 16.938 17.383 ;
     RECT  17.784 16.541 40.497 17.383 ;
     RECT  2.415 17.383 40.497 18.265 ;
     RECT  2.34 18.265 40.497 18.803 ;
     RECT  2.415 18.803 40.497 20.581 ;
     RECT  2.412 20.581 40.497 20.587 ;
     RECT  2.376 20.587 40.497 20.731 ;
     RECT  2.376 20.731 40.914 20.957 ;
     RECT  2.376 20.957 40.497 21.533 ;
     RECT  2.415 21.533 40.497 22.081 ;
     RECT  2.415 22.081 40.59 23.081 ;
     RECT  2.415 23.081 40.497 23.161 ;
     RECT  2.376 23.161 40.497 24.089 ;
     RECT  2.415 24.089 40.497 24.125 ;
     RECT  17.424 24.125 40.497 24.601 ;
     RECT  17.424 24.601 40.554 24.899 ;
     RECT  2.415 24.125 16.542 25.015 ;
     RECT  17.424 24.899 40.497 25.015 ;
     RECT  2.415 25.015 40.497 25.411 ;
     RECT  2.376 25.411 40.497 27.101 ;
     RECT  2.415 27.101 40.497 27.841 ;
     RECT  2.415 27.841 40.554 28.381 ;
     RECT  2.415 28.381 40.698 28.561 ;
     RECT  2.34 28.561 40.698 29.021 ;
     RECT  2.376 29.021 40.698 30.713 ;
     RECT  25.74 30.713 40.698 31.109 ;
     RECT  25.74 31.109 40.662 31.217 ;
     RECT  25.74 31.217 40.497 31.325 ;
     RECT  2.376 30.713 24.966 31.495 ;
     RECT  25.74 31.325 38.214 31.495 ;
     RECT  2.376 31.495 38.214 32.305 ;
     RECT  38.988 31.325 40.497 32.305 ;
     RECT  2.376 32.305 40.497 32.459 ;
     RECT  2.415 32.459 40.497 32.467 ;
     RECT  2.415 32.467 40.554 32.729 ;
     RECT  2.415 32.729 40.497 34.501 ;
     RECT  2.415 34.501 40.554 34.591 ;
     RECT  2.415 34.591 40.662 34.727 ;
     RECT  2.415 34.727 40.554 34.997 ;
     RECT  2.415 34.997 40.497 35.005 ;
     RECT  2.34 35.005 40.497 37.669 ;
     RECT  2.34 37.669 40.662 39.829 ;
     RECT  2.34 39.829 40.698 40.055 ;
     RECT  6.804 40.055 40.698 40.397 ;
     RECT  6.804 40.397 40.626 40.559 ;
     RECT  6.804 40.559 40.554 40.595 ;
     RECT  2.34 40.055 6.03 41.251 ;
     RECT  6.804 40.595 40.497 41.251 ;
     RECT  2.34 41.251 40.497 41.377 ;
     RECT  2.34 41.377 40.662 41.909 ;
     RECT  2.34 41.909 40.59 42.719 ;
     RECT  2.34 42.719 40.554 43.331 ;
     RECT  2.376 43.331 40.554 44.311 ;
     RECT  2.376 44.311 40.59 44.339 ;
     RECT  2.415 44.339 40.59 44.689 ;
     RECT  2.415 44.689 40.698 45.149 ;
     RECT  2.415 45.149 40.626 45.257 ;
     RECT  2.415 45.257 40.554 45.761 ;
     RECT  2.415 45.761 35.19 45.805 ;
     RECT  35.928 45.761 40.554 45.833 ;
     RECT  2.376 45.805 35.19 46.229 ;
     RECT  2.415 46.229 35.19 46.651 ;
     RECT  35.964 45.833 40.554 46.651 ;
     RECT  2.415 46.651 40.554 47.111 ;
     RECT  2.415 47.111 40.497 47.659 ;
     RECT  2.412 47.659 40.497 48.001 ;
     RECT  2.376 48.001 40.497 48.155 ;
     RECT  2.415 48.155 40.497 48.271 ;
     RECT  2.415 48.271 40.914 48.659 ;
     RECT  2.415 48.659 40.626 49.739 ;
     RECT  2.415 49.739 40.554 49.775 ;
     RECT  2.415 49.775 40.497 49.867 ;
     RECT  2.412 49.867 40.497 50.287 ;
     RECT  2.376 50.287 40.497 50.521 ;
     RECT  2.376 50.521 40.662 50.549 ;
     RECT  2.415 50.549 40.662 51.089 ;
     RECT  2.415 51.089 40.554 51.125 ;
     RECT  2.415 51.125 40.497 52.321 ;
     RECT  2.376 52.321 40.497 52.987 ;
     RECT  2.376 52.987 40.734 53.519 ;
     RECT  2.376 53.519 40.497 54.751 ;
     RECT  2.376 54.751 40.554 55.111 ;
     RECT  2.376 55.111 40.59 55.715 ;
     RECT  2.376 55.715 40.497 57.029 ;
     RECT  2.415 57.029 40.497 57.991 ;
     RECT  2.415 57.991 40.554 58.081 ;
     RECT  2.415 58.081 40.626 58.157 ;
     RECT  32.076 58.157 40.626 58.379 ;
     RECT  32.076 58.379 40.554 58.649 ;
     RECT  2.415 58.157 31.338 58.991 ;
     RECT  9.936 58.991 31.338 59.071 ;
     RECT  32.076 58.649 40.497 59.071 ;
     RECT  2.415 58.991 9.198 59.467 ;
     RECT  2.376 59.467 9.198 59.845 ;
     RECT  9.936 59.071 40.497 59.845 ;
     RECT  2.376 59.845 40.497 60.079 ;
     RECT  2.376 60.079 40.554 60.269 ;
     RECT  2.376 60.269 40.497 60.349 ;
     RECT  2.34 60.349 40.497 60.511 ;
     RECT  2.304 60.511 40.497 61.465 ;
     RECT  2.304 61.465 40.734 61.889 ;
     RECT  2.304 61.889 40.59 62.537 ;
     RECT  2.304 62.537 40.554 62.879 ;
     RECT  2.34 62.879 40.554 63.113 ;
     RECT  2.34 63.113 19.638 63.239 ;
     RECT  2.34 63.239 19.422 64.021 ;
     RECT  20.376 63.113 40.554 64.021 ;
     RECT  2.34 64.021 40.554 64.291 ;
     RECT  2.34 64.291 40.59 64.705 ;
     RECT  2.34 64.705 40.734 65.821 ;
     RECT  2.34 65.821 40.842 66.209 ;
     RECT  2.34 66.209 40.698 66.289 ;
     RECT  2.304 66.289 40.698 66.317 ;
     RECT  2.304 66.317 40.59 66.515 ;
     RECT  27.792 66.515 40.59 67.019 ;
     RECT  2.304 66.515 26.91 67.055 ;
     RECT  18.108 67.055 26.91 67.261 ;
     RECT  27.792 67.019 40.554 67.261 ;
     RECT  2.304 67.055 17.37 68.215 ;
     RECT  18.108 67.261 40.554 68.215 ;
     RECT  2.304 68.215 40.554 69.089 ;
     RECT  2.304 69.089 40.497 69.871 ;
     RECT  2.304 69.871 40.626 70.033 ;
     RECT  2.304 70.033 40.734 70.529 ;
     RECT  2.304 70.529 40.59 70.565 ;
     RECT  2.304 70.565 40.497 70.673 ;
     RECT  2.304 70.673 28.242 70.799 ;
     RECT  29.16 70.673 40.497 70.799 ;
     RECT  29.304 70.799 40.497 71.491 ;
     RECT  2.304 70.799 28.134 71.519 ;
     RECT  28.26 71.611 28.278 71.651 ;
     RECT  29.304 71.491 40.914 71.725 ;
     RECT  29.232 71.725 40.914 71.753 ;
     RECT  29.232 71.753 40.59 71.951 ;
     RECT  29.232 71.951 40.497 72.149 ;
     RECT  2.304 71.519 27.486 72.427 ;
     RECT  28.332 72.031 28.35 72.427 ;
     RECT  2.304 72.427 28.35 72.499 ;
     RECT  29.232 72.149 29.697 72.499 ;
     RECT  30.42 72.149 40.497 72.527 ;
     RECT  30.672 72.527 40.497 72.959 ;
     RECT  31.392 72.959 40.497 72.995 ;
     RECT  31.572 72.995 40.497 73.003 ;
     RECT  2.304 72.499 29.697 73.111 ;
     RECT  2.304 73.111 29.898 73.877 ;
     RECT  2.376 73.877 29.898 74.047 ;
     RECT  30.672 73.921 30.69 74.047 ;
     RECT  31.572 73.003 40.59 74.047 ;
     RECT  2.376 74.047 40.59 74.389 ;
     RECT  2.376 74.389 40.626 75.001 ;
     RECT  2.304 75.001 40.626 75.227 ;
     RECT  15.516 75.227 40.626 75.811 ;
     RECT  2.304 75.227 14.742 75.929 ;
     RECT  15.516 75.811 40.662 76.037 ;
     RECT  2.34 75.929 14.742 76.351 ;
     RECT  15.516 76.037 40.59 76.351 ;
     RECT  2.34 76.351 40.59 76.397 ;
     RECT  2.34 76.397 22.878 76.981 ;
     RECT  2.304 76.981 22.878 77.153 ;
     RECT  2.34 77.153 22.878 77.161 ;
     RECT  23.796 76.397 40.59 77.161 ;
     RECT  2.34 77.161 40.59 78.395 ;
     RECT  34.596 78.395 40.59 78.665 ;
     RECT  34.74 78.665 40.59 78.935 ;
     RECT  34.776 78.935 40.59 79.205 ;
     RECT  2.34 78.395 33.858 79.241 ;
     RECT  34.776 79.205 40.497 79.439 ;
     RECT  34.776 79.439 36.306 79.661 ;
     RECT  15.156 79.241 33.858 79.709 ;
     RECT  34.776 79.661 36.018 79.745 ;
     RECT  15.156 79.709 31.734 79.853 ;
     RECT  32.652 79.709 33.858 80.131 ;
     RECT  37.044 79.439 40.497 80.329 ;
     RECT  34.815 79.745 36.018 80.401 ;
     RECT  36.936 80.329 40.497 80.401 ;
     RECT  2.34 79.241 14.346 80.555 ;
     RECT  15.156 79.853 31.59 80.555 ;
     RECT  22.356 80.555 31.59 80.629 ;
     RECT  32.652 80.131 34.038 80.629 ;
     RECT  2.376 80.555 14.346 80.671 ;
     RECT  15.156 80.555 21.438 80.671 ;
     RECT  22.356 80.629 34.038 80.671 ;
     RECT  22.356 80.671 34.074 80.941 ;
     RECT  34.815 80.401 40.497 80.941 ;
     RECT  22.356 80.941 40.497 80.957 ;
     RECT  2.376 80.671 21.438 81.059 ;
     RECT  17.028 81.059 21.438 81.131 ;
     RECT  2.376 81.059 16.254 81.365 ;
     RECT  32.652 80.957 40.497 81.389 ;
     RECT  16.2 81.365 16.254 81.473 ;
     RECT  18.288 81.131 21.438 81.481 ;
     RECT  22.356 80.957 31.77 81.481 ;
     RECT  32.652 81.389 39.33 81.599 ;
     RECT  40.104 81.389 40.497 81.635 ;
     RECT  17.028 81.131 17.514 81.877 ;
     RECT  2.376 81.365 15.426 81.905 ;
     RECT  18.288 81.481 31.77 81.977 ;
     RECT  16.56 81.877 17.514 82.021 ;
     RECT  18.288 81.977 19.962 82.021 ;
     RECT  15.552 82.147 15.642 82.255 ;
     RECT  16.56 82.021 19.962 82.255 ;
     RECT  2.376 81.905 14.778 82.409 ;
     RECT  2.415 82.409 14.778 82.445 ;
     RECT  32.688 81.599 39.33 82.525 ;
     RECT  15.552 82.255 19.962 82.553 ;
     RECT  32.688 82.525 39.438 82.553 ;
     RECT  32.688 82.553 37.35 82.589 ;
     RECT  38.196 82.553 39.438 82.589 ;
     RECT  32.688 82.589 36.63 82.637 ;
     RECT  19.908 82.553 19.962 82.652 ;
     RECT  36.504 82.637 36.63 82.679 ;
     RECT  38.196 82.589 38.25 82.679 ;
     RECT  39.312 82.589 39.438 82.679 ;
     RECT  15.552 82.553 19.17 82.687 ;
     RECT  36.612 82.679 36.63 82.715 ;
     RECT  38.232 82.679 38.25 82.715 ;
     RECT  39.312 82.679 39.33 82.715 ;
     RECT  15.516 82.687 19.17 82.781 ;
     RECT  19.944 82.652 19.962 82.831 ;
     RECT  20.808 81.977 31.77 82.831 ;
     RECT  32.688 82.637 35.406 82.831 ;
     RECT  19.944 82.831 31.77 82.921 ;
     RECT  32.544 82.831 35.406 82.921 ;
     RECT  19.944 82.921 35.406 83.363 ;
     RECT  25.02 83.363 35.406 83.525 ;
     RECT  15.552 82.781 19.17 83.569 ;
     RECT  19.944 83.363 24.297 83.569 ;
     RECT  2.415 82.445 14.742 83.605 ;
     RECT  15.552 83.569 24.297 83.605 ;
     RECT  2.415 83.605 24.297 83.641 ;
     RECT  25.668 83.525 35.406 83.641 ;
     RECT  2.376 83.641 24.297 84.271 ;
     RECT  2.376 84.271 24.354 84.611 ;
     RECT  15.876 84.611 24.354 84.721 ;
     RECT  25.668 83.641 35.73 84.721 ;
     RECT  15.876 84.721 35.73 84.839 ;
     RECT  2.376 84.611 15.138 85.109 ;
     RECT  16.02 84.839 35.73 85.261 ;
     RECT  2.376 85.109 14.958 85.379 ;
     RECT  16.02 85.261 35.802 85.451 ;
     RECT  27.54 85.451 35.802 85.459 ;
     RECT  16.02 85.451 26.802 85.487 ;
     RECT  27.54 85.459 36.162 85.487 ;
     RECT  27.792 85.487 36.162 85.523 ;
     RECT  16.02 85.487 26.622 85.721 ;
     RECT  16.02 85.721 24.858 85.729 ;
     RECT  28.368 85.523 36.162 85.765 ;
     RECT  15.912 85.729 24.858 85.801 ;
     RECT  2.415 85.379 14.958 86.071 ;
     RECT  15.732 85.801 24.858 86.071 ;
     RECT  28.368 85.765 36.198 86.071 ;
     RECT  28.368 86.071 36.306 86.189 ;
     RECT  36.936 86.251 36.954 86.369 ;
     RECT  25.668 85.721 26.622 86.431 ;
     RECT  2.415 86.071 24.858 86.467 ;
     RECT  25.668 86.431 26.802 86.467 ;
     RECT  2.415 86.467 26.802 86.575 ;
     RECT  2.415 86.575 26.874 86.587 ;
     RECT  2.415 86.587 27.09 86.639 ;
     RECT  23.976 86.639 27.09 87.007 ;
     RECT  23.976 87.007 27.522 87.151 ;
     RECT  28.368 86.189 36.054 87.151 ;
     RECT  23.976 87.151 36.054 87.355 ;
     RECT  2.415 86.639 23.166 87.385 ;
     RECT  23.976 87.355 36.378 87.385 ;
     RECT  2.415 87.385 36.378 87.413 ;
     RECT  2.415 87.413 19.134 88.079 ;
     RECT  18.108 88.079 19.134 88.231 ;
     RECT  19.944 87.413 35.73 88.231 ;
     RECT  18.108 88.231 35.73 88.321 ;
     RECT  37.152 87.925 37.17 88.349 ;
     RECT  18.108 88.321 35.982 88.357 ;
     RECT  18.108 88.357 36.234 88.397 ;
     RECT  2.415 88.079 17.37 88.493 ;
     RECT  2.415 88.493 17.226 88.781 ;
     RECT  2.415 88.781 17.154 88.799 ;
     RECT  2.415 88.799 17.046 88.925 ;
     RECT  3.78 88.925 17.046 89.51 ;
     RECT  3.816 89.51 17.046 89.699 ;
     RECT  18.108 88.397 35.982 89.771 ;
     RECT  3.852 89.699 17.046 89.779 ;
     RECT  3.852 89.779 17.118 89.807 ;
     RECT  32.436 89.771 35.982 89.807 ;
     RECT  32.436 89.807 33.642 89.843 ;
     RECT  3.924 89.807 17.118 89.969 ;
     RECT  18.108 89.771 31.698 89.969 ;
     RECT  32.472 89.843 32.49 89.969 ;
     RECT  33.48 89.843 33.642 89.969 ;
     RECT  34.416 89.807 35.982 89.969 ;
     RECT  33.48 89.969 33.498 89.981 ;
     RECT  3.924 89.969 17.046 90.005 ;
     RECT  22.788 89.969 31.338 90.005 ;
     RECT  3.924 90.005 16.974 90.041 ;
     RECT  23.292 90.005 25.938 90.041 ;
     RECT  26.964 90.005 31.338 90.077 ;
     RECT  18.108 89.969 22.05 90.091 ;
     RECT  4.248 90.041 16.974 90.113 ;
     RECT  23.688 90.041 25.866 90.113 ;
     RECT  31.32 90.077 31.338 90.113 ;
     RECT  18.036 90.091 22.05 90.239 ;
     RECT  26.964 90.077 30.546 90.239 ;
     RECT  34.668 89.969 35.982 90.239 ;
     RECT  4.284 90.113 16.938 90.275 ;
     RECT  18.036 90.239 19.854 90.275 ;
     RECT  20.592 90.239 22.05 90.275 ;
     RECT  34.668 90.239 35.097 90.275 ;
     RECT  21.456 90.275 22.05 90.311 ;
     RECT  18.036 90.275 19.422 90.355 ;
     RECT  26.964 90.239 27.738 90.383 ;
     RECT  28.692 90.239 30.546 90.383 ;
     RECT  4.32 90.275 16.938 90.419 ;
     RECT  17.928 90.355 19.422 90.419 ;
     RECT  35.964 90.239 35.982 90.419 ;
     RECT  2.415 88.925 2.697 90.467 ;
     RECT  34.815 90.275 35.097 90.467 ;
     RECT  40.215 81.635 40.497 90.467 ;
     RECT  4.32 90.419 4.842 90.509 ;
     RECT  5.616 90.419 16.938 90.509 ;
     RECT  17.928 90.419 19.098 90.509 ;
     RECT  20.592 90.275 20.682 90.509 ;
     RECT  23.688 90.113 25.722 90.509 ;
     RECT  28.692 90.383 30.51 90.509 ;
     RECT  4.464 90.509 4.842 90.545 ;
     RECT  5.616 90.509 5.634 90.545 ;
     RECT  6.408 90.509 14.994 90.545 ;
     RECT  20.592 90.509 20.61 90.545 ;
     RECT  27.396 90.383 27.738 90.545 ;
     RECT  28.98 90.509 30.402 90.545 ;
     RECT  7.815 90.545 14.454 90.557 ;
     RECT  6.408 90.545 6.426 90.581 ;
     RECT  15.912 90.509 15.93 90.581 ;
     RECT  17.928 90.509 18.954 90.581 ;
     RECT  24.015 90.509 24.354 90.581 ;
     RECT  4.824 90.545 4.842 90.617 ;
     RECT  7.815 90.557 13.305 90.617 ;
     RECT  14.436 90.557 14.454 90.617 ;
     RECT  18.615 90.581 18.954 90.617 ;
     RECT  21.744 90.311 22.05 90.617 ;
     RECT  25.236 90.509 25.722 90.617 ;
     RECT  29.088 90.545 29.505 90.617 ;
     RECT  25.236 90.617 25.254 90.689 ;
     RECT  2.415 90.467 2.505 90.737 ;
     RECT  7.815 90.617 7.905 90.737 ;
     RECT  12.312 90.617 13.305 90.737 ;
     RECT  18.615 90.617 18.705 90.737 ;
     RECT  24.015 90.581 24.105 90.737 ;
     RECT  29.415 90.617 29.505 90.737 ;
     RECT  34.815 90.467 34.905 90.737 ;
     RECT  40.215 90.467 40.305 90.737 ;
     RECT  12.312 90.737 13.014 90.779 ;
     RECT  8.64 90.617 11.466 91.277 ;
     RECT  12.78 90.779 13.014 91.814 ;
     RECT  12.78 91.814 12.798 92.669 ;
     RECT  9 91.277 11.466 92.748 ;
    LAYER M4 ;
     RECT  0.156 14.88 0.275 15.192 ;
     RECT  2.252 9.12 2.293 9.144 ;
     RECT  2.329 28.992 2.365 29.016 ;
     RECT  0.229 46.32 2.365 46.344 ;
     RECT  2.293 81.456 2.365 81.48 ;
     RECT  2.293 83.232 2.365 83.256 ;
     RECT  0.275 15.024 2.401 15.192 ;
     RECT  2.365 3.408 2.408 3.432 ;
     RECT  2.365 6.384 2.408 6.408 ;
     RECT  2.293 7.92 2.408 9.144 ;
     RECT  2.365 10.176 2.408 10.2 ;
     RECT  2.401 12.528 2.408 12.552 ;
     RECT  2.329 13.68 2.408 13.704 ;
     RECT  2.401 15.024 2.408 16.104 ;
     RECT  2.329 18.768 2.408 18.792 ;
     RECT  2.401 20.592 2.408 20.616 ;
     RECT  2.365 23.28 2.408 23.304 ;
     RECT  2.365 27.072 2.408 27.096 ;
     RECT  2.365 28.992 2.408 29.64 ;
     RECT  2.365 36.624 2.408 36.648 ;
     RECT  2.365 39.744 2.408 39.768 ;
     RECT  2.365 43.824 2.408 43.848 ;
     RECT  2.365 46.08 2.408 46.344 ;
     RECT  2.401 49.872 2.408 49.896 ;
     RECT  2.365 55.728 2.408 55.752 ;
     RECT  2.365 56.88 2.408 56.904 ;
     RECT  2.365 66.048 2.408 66.072 ;
     RECT  2.365 67.68 2.408 67.704 ;
     RECT  2.365 70.272 2.408 70.632 ;
     RECT  2.365 81.072 2.408 81.48 ;
     RECT  2.365 83.232 2.408 83.784 ;
     RECT  2.408 2.148 2.512 90.732 ;
     RECT  2.512 2.418 2.704 90.462 ;
     RECT  2.704 5.184 2.819 6.408 ;
     RECT  2.704 8.688 2.819 8.808 ;
     RECT  2.704 77.04 2.819 78.648 ;
     RECT  2.704 28.464 2.837 30.072 ;
     RECT  2.704 17.088 2.867 17.688 ;
     RECT  2.704 18.768 2.867 19.464 ;
     RECT  2.704 20.592 2.867 22.248 ;
     RECT  2.704 39.744 2.867 40.632 ;
     RECT  2.704 80.4 2.867 83.784 ;
     RECT  2.867 39.792 2.873 40.632 ;
     RECT  2.704 43.824 2.909 43.896 ;
     RECT  2.704 2.688 3.299 4.104 ;
     RECT  2.704 23.28 3.305 27.096 ;
     RECT  3.299 4.08 3.347 4.104 ;
     RECT  2.704 51.312 3.421 75.864 ;
     RECT  2.704 49.488 3.449 49.896 ;
     RECT  3.305 23.28 3.485 23.592 ;
     RECT  2.819 5.184 3.491 6.264 ;
     RECT  2.867 17.088 3.629 17.112 ;
     RECT  2.819 77.472 3.665 78.648 ;
     RECT  2.704 12.528 3.697 13.704 ;
     RECT  2.704 14.976 3.697 16.104 ;
     RECT  2.867 19.344 3.697 19.464 ;
     RECT  3.421 51.312 3.697 75.384 ;
     RECT  3.697 50.688 3.701 75.384 ;
     RECT  3.701 50.688 3.779 58.296 ;
     RECT  3.701 59.28 3.809 75.384 ;
     RECT  2.867 80.4 3.827 82.056 ;
     RECT  2.837 28.464 3.845 28.488 ;
     RECT  2.837 29.472 3.845 30.072 ;
     RECT  2.704 87.792 3.845 88.2 ;
     RECT  3.305 25.104 3.875 27.096 ;
     RECT  2.704 46.08 3.881 47.304 ;
     RECT  3.809 59.28 3.881 74.136 ;
     RECT  2.867 83.232 3.905 83.784 ;
     RECT  3.449 49.488 3.913 49.512 ;
     RECT  3.665 78.096 3.913 78.648 ;
     RECT  3.881 64.368 3.917 74.136 ;
     RECT  3.491 5.184 3.949 5.688 ;
     RECT  2.704 10.176 3.949 10.2 ;
     RECT  2.704 33.648 3.949 33.672 ;
     RECT  3.881 59.28 3.953 63.24 ;
     RECT  3.917 68.832 3.953 74.136 ;
     RECT  3.779 50.688 3.971 54.696 ;
     RECT  3.917 66.624 3.971 67.32 ;
     RECT  3.971 66.72 3.989 67.32 ;
     RECT  3.905 83.232 3.989 83.832 ;
     RECT  3.971 50.688 4.012 53.016 ;
     RECT  3.953 70.896 4.012 74.136 ;
     RECT  3.881 46.128 4.021 47.304 ;
     RECT  3.697 12.528 4.025 16.104 ;
     RECT  2.704 36.624 4.061 36.648 ;
     RECT  3.779 56.4 4.061 58.296 ;
     RECT  2.819 8.688 4.093 8.712 ;
     RECT  3.949 10.176 4.093 10.632 ;
     RECT  3.949 33.648 4.093 33.72 ;
     RECT  2.704 34.992 4.093 35.112 ;
     RECT  2.909 43.872 4.093 43.896 ;
     RECT  2.867 21.504 4.097 22.248 ;
     RECT  4.061 56.4 4.097 58.152 ;
     RECT  3.917 64.368 4.163 65.64 ;
     RECT  4.012 50.832 4.169 53.016 ;
     RECT  4.163 64.368 4.169 65.592 ;
     RECT  3.841 38.736 4.201 38.76 ;
     RECT  2.873 39.936 4.201 40.632 ;
     RECT  2.704 86.448 4.201 86.472 ;
     RECT  3.845 87.792 4.201 87.816 ;
     RECT  3.953 59.28 4.213 61.992 ;
     RECT  4.093 7.392 4.237 7.416 ;
     RECT  4.093 8.688 4.237 10.632 ;
     RECT  3.697 31.536 4.241 31.56 ;
     RECT  4.093 33.648 4.259 35.112 ;
     RECT  4.021 46.128 4.261 47.88 ;
     RECT  3.913 49.008 4.261 49.512 ;
     RECT  4.201 86.448 4.261 87.816 ;
     RECT  3.913 76.944 4.268 76.968 ;
     RECT  4.213 59.808 4.277 61.992 ;
     RECT  4.261 46.128 4.307 49.512 ;
     RECT  4.237 7.392 4.313 10.632 ;
     RECT  4.261 85.776 4.313 87.816 ;
     RECT  4.313 85.776 4.348 85.8 ;
     RECT  4.097 56.4 4.349 57.048 ;
     RECT  4.025 12.528 4.357 15.624 ;
     RECT  3.949 4.512 4.381 5.688 ;
     RECT  4.357 11.712 4.403 15.624 ;
     RECT  2.704 42.72 4.405 42.744 ;
     RECT  3.913 78.096 4.417 78.936 ;
     RECT  4.259 33.696 4.457 35.112 ;
     RECT  4.277 59.904 4.457 61.992 ;
     RECT  3.953 63.216 4.457 63.24 ;
     RECT  4.012 71.28 4.457 74.136 ;
     RECT  4.405 42.096 4.492 42.744 ;
     RECT  3.875 27.024 4.493 27.096 ;
     RECT  4.313 7.392 4.501 8.184 ;
     RECT  4.307 48.048 4.501 49.512 ;
     RECT  3.809 75.216 4.501 75.384 ;
     RECT  4.268 76.416 4.501 76.968 ;
     RECT  4.381 4.08 4.525 5.688 ;
     RECT  3.989 83.232 4.529 83.784 ;
     RECT  3.299 2.688 4.549 2.952 ;
     RECT  4.525 4.08 4.549 6.264 ;
     RECT  3.485 23.328 4.556 23.592 ;
     RECT  4.201 38.736 4.601 40.632 ;
     RECT  4.457 59.904 4.601 61.656 ;
     RECT  3.769 89.472 4.601 89.496 ;
     RECT  4.313 9.264 4.633 10.632 ;
     RECT  4.403 11.712 4.633 12.792 ;
     RECT  4.601 39.936 4.637 40.632 ;
     RECT  4.601 59.904 4.637 61.416 ;
     RECT  4.556 23.328 4.643 24.12 ;
     RECT  4.637 59.904 4.643 61.272 ;
     RECT  3.697 19.344 4.669 19.8 ;
     RECT  4.492 42.72 4.705 42.744 ;
     RECT  4.093 43.872 4.705 44.472 ;
     RECT  3.845 29.568 4.709 30.072 ;
     RECT  4.457 34.176 4.741 35.112 ;
     RECT  3.875 25.104 4.745 25.8 ;
     RECT  4.669 19.344 4.781 20.376 ;
     RECT  4.601 38.736 4.781 38.808 ;
     RECT  4.457 72.192 4.813 74.136 ;
     RECT  4.501 75.216 4.813 76.968 ;
     RECT  4.417 78.096 4.813 79.704 ;
     RECT  4.745 25.104 4.817 25.128 ;
     RECT  4.705 42.72 4.817 44.472 ;
     RECT  4.781 38.736 4.835 38.76 ;
     RECT  4.549 2.688 4.837 6.264 ;
     RECT  4.501 7.296 4.837 8.184 ;
     RECT  4.097 22.224 4.885 22.248 ;
     RECT  4.643 23.328 4.885 23.352 ;
     RECT  4.493 27.024 4.885 27.048 ;
     RECT  4.741 34.176 4.925 35.256 ;
     RECT  4.169 52.032 4.925 53.016 ;
     RECT  4.633 9.264 4.931 12.792 ;
     RECT  4.813 72.192 4.931 76.968 ;
     RECT  3.953 68.832 4.957 69.72 ;
     RECT  4.169 64.416 4.961 65.592 ;
     RECT  4.813 78.096 4.988 79.848 ;
     RECT  3.827 80.88 4.988 82.056 ;
     RECT  4.988 78.096 4.993 82.056 ;
     RECT  4.529 83.232 4.993 83.256 ;
     RECT  4.837 2.688 5.027 8.184 ;
     RECT  5.027 2.688 5.061 7.368 ;
     RECT  4.813 21.12 5.125 21.192 ;
     RECT  4.885 22.224 5.125 23.352 ;
     RECT  4.931 75.264 5.149 76.968 ;
     RECT  4.097 58.128 5.173 58.152 ;
     RECT  4.313 87.36 5.177 87.816 ;
     RECT  5.125 21.12 5.212 23.352 ;
     RECT  5.149 75.744 5.221 76.968 ;
     RECT  4.993 78.096 5.221 83.256 ;
     RECT  4.403 14.208 5.245 15.624 ;
     RECT  4.453 16.608 5.245 16.632 ;
     RECT  4.817 42.72 5.249 44.088 ;
     RECT  4.307 46.128 5.269 47.016 ;
     RECT  4.501 48.048 5.269 49.56 ;
     RECT  5.221 75.744 5.285 83.256 ;
     RECT  5.269 46.128 5.315 49.56 ;
     RECT  4.349 56.928 5.315 57.048 ;
     RECT  4.309 36.48 5.317 36.504 ;
     RECT  5.212 22.704 5.321 23.352 ;
     RECT  4.489 85.488 5.321 85.512 ;
     RECT  5.317 35.952 5.357 36.504 ;
     RECT  5.285 76.368 5.357 83.256 ;
     RECT  4.925 34.176 5.393 34.824 ;
     RECT  5.281 55.872 5.413 55.896 ;
     RECT  5.269 62.736 5.461 62.76 ;
     RECT  3.971 54.096 5.497 54.696 ;
     RECT  5.413 55.68 5.497 55.896 ;
     RECT  4.957 68.352 5.509 69.72 ;
     RECT  5.461 32.976 5.516 33 ;
     RECT  5.393 34.176 5.516 34.248 ;
     RECT  4.169 50.832 5.533 50.856 ;
     RECT  4.925 52.032 5.533 52.968 ;
     RECT  3.989 67.248 5.533 67.32 ;
     RECT  5.509 68.352 5.537 70.248 ;
     RECT  5.537 69.408 5.555 70.248 ;
     RECT  5.245 14.208 5.569 16.632 ;
     RECT  5.425 17.664 5.569 17.688 ;
     RECT  5.516 32.976 5.603 33.048 ;
     RECT  5.357 35.952 5.603 35.976 ;
     RECT  5.315 46.128 5.609 47.64 ;
     RECT  4.931 9.264 5.645 9.288 ;
     RECT  5.497 54.096 5.653 55.896 ;
     RECT  5.173 58.128 5.653 58.68 ;
     RECT  4.643 60 5.653 61.272 ;
     RECT  5.653 58.128 5.66 61.272 ;
     RECT  5.461 62.736 5.66 63.288 ;
     RECT  4.931 10.32 5.677 12.792 ;
     RECT  5.569 14.208 5.677 17.688 ;
     RECT  5.315 48.624 5.677 49.56 ;
     RECT  5.533 50.832 5.677 52.968 ;
     RECT  5.66 58.128 5.699 63.288 ;
     RECT  4.931 72.192 5.699 74.136 ;
     RECT  5.533 67.152 5.701 67.32 ;
     RECT  5.537 68.352 5.701 68.376 ;
     RECT  5.321 22.704 5.717 22.776 ;
     RECT  5.677 10.32 5.747 17.688 ;
     RECT  5.701 67.152 5.747 68.376 ;
     RECT  5.249 42.72 5.749 43.08 ;
     RECT  5.747 10.32 5.753 16.968 ;
     RECT  5.061 6.24 5.789 7.368 ;
     RECT  5.753 12.768 5.789 16.968 ;
     RECT  4.709 30.048 5.821 30.072 ;
     RECT  4.789 40.656 5.821 40.872 ;
     RECT  5.699 60.816 5.843 63.288 ;
     RECT  5.245 25.008 5.845 25.032 ;
     RECT  5.569 89.472 5.857 89.496 ;
     RECT  5.699 72.192 5.861 73.512 ;
     RECT  5.357 76.512 5.861 83.256 ;
     RECT  5.753 10.32 5.897 11.736 ;
     RECT  5.845 25.008 5.929 25.128 ;
     RECT  4.993 38.112 5.933 38.136 ;
     RECT  4.781 19.344 5.965 19.8 ;
     RECT  5.929 24.816 5.965 25.128 ;
     RECT  4.885 26.16 5.965 27.048 ;
     RECT  5.843 60.96 5.969 63.288 ;
     RECT  5.965 24.816 5.989 27.048 ;
     RECT  5.677 48.624 6.001 52.968 ;
     RECT  5.509 84.288 6.001 84.312 ;
     RECT  5.699 58.128 6.005 59.64 ;
     RECT  5.989 24.816 6.035 27.336 ;
     RECT  5.749 31.872 6.037 31.896 ;
     RECT  5.861 72.192 6.037 72.408 ;
     RECT  5.789 12.768 6.041 16.824 ;
     RECT  6.001 48.624 6.041 53.016 ;
     RECT  5.653 54.048 6.044 55.896 ;
     RECT  5.789 7.344 6.073 7.368 ;
     RECT  6.005 58.128 6.077 59.16 ;
     RECT  6.001 84.288 6.085 84.408 ;
     RECT  5.897 10.32 6.109 10.632 ;
     RECT  6.041 48.816 6.131 53.016 ;
     RECT  5.861 76.512 6.149 77.448 ;
     RECT  5.965 19.344 6.181 20.088 ;
     RECT  5.177 87.792 6.181 87.816 ;
     RECT  5.821 40.416 6.217 40.872 ;
     RECT  5.749 42.192 6.217 43.08 ;
     RECT  6.131 52.032 6.221 53.016 ;
     RECT  5.861 78.624 6.227 83.256 ;
     RECT  6.181 19.104 6.253 20.088 ;
     RECT  5.212 21.12 6.253 21.192 ;
     RECT  4.961 64.416 6.277 65.16 ;
     RECT  5.603 32.976 6.284 33 ;
     RECT  6.037 71.808 6.293 72.408 ;
     RECT  6.277 63.504 6.323 65.16 ;
     RECT  6.253 19.104 6.332 21.192 ;
     RECT  6.332 19.104 6.361 21.384 ;
     RECT  6.323 63.504 6.364 63.816 ;
     RECT  6.037 31.536 6.365 31.896 ;
     RECT  6.131 48.816 6.365 50.856 ;
     RECT  6.077 58.56 6.365 59.16 ;
     RECT  5.555 69.456 6.373 70.248 ;
     RECT  6.227 79.68 6.397 83.256 ;
     RECT  6.044 54 6.401 55.896 ;
     RECT  6.361 19.104 6.419 21.96 ;
     RECT  6.293 71.856 6.445 72.408 ;
     RECT  5.612 85.776 6.469 86.76 ;
     RECT  6.181 87.792 6.469 88.392 ;
     RECT  5.061 2.688 6.473 5.016 ;
     RECT  6.035 25.008 6.473 27.336 ;
     RECT  6.397 79.68 6.509 84.024 ;
     RECT  5.747 67.68 6.545 68.376 ;
     RECT  6.545 67.776 6.565 68.376 ;
     RECT  6.373 69.456 6.565 70.68 ;
     RECT  5.516 34.128 6.581 34.248 ;
     RECT  5.969 60.96 6.611 62.424 ;
     RECT  5.315 57.024 6.613 57.048 ;
     RECT  6.611 62.4 6.652 62.424 ;
     RECT  6.565 67.776 6.653 70.68 ;
     RECT  6.217 40.416 6.689 43.08 ;
     RECT  6.109 74.688 6.757 74.712 ;
     RECT  6.149 76.512 6.757 76.968 ;
     RECT  6.253 66.528 6.761 66.552 ;
     RECT  6.581 34.224 6.797 34.248 ;
     RECT  5.861 73.488 6.803 73.512 ;
     RECT  6.611 60.96 6.805 61.32 ;
     RECT  6.041 14.64 6.829 16.824 ;
     RECT  6.401 54 6.829 55.704 ;
     RECT  5.857 89.472 6.851 90.072 ;
     RECT  5.897 11.712 6.853 11.736 ;
     RECT  6.041 12.768 6.853 13.656 ;
     RECT  6.829 14.64 6.853 16.968 ;
     RECT  6.323 64.8 6.901 65.16 ;
     RECT  6.469 85.776 6.937 88.392 ;
     RECT  6.851 89.472 6.937 90.12 ;
     RECT  6.289 23.28 7.004 23.304 ;
     RECT  6.473 25.008 7.004 26.184 ;
     RECT  6.365 31.872 7.045 31.896 ;
     RECT  6.284 32.88 7.045 33 ;
     RECT  6.473 27.168 7.117 27.336 ;
     RECT  6.689 40.416 7.117 41.448 ;
     RECT  6.853 11.712 7.141 13.656 ;
     RECT  6.853 14.64 7.141 17.592 ;
     RECT  5.789 6.24 7.225 6.264 ;
     RECT  6.073 7.344 7.225 7.752 ;
     RECT  6.109 9.696 7.237 10.632 ;
     RECT  7.141 11.712 7.237 17.592 ;
     RECT  6.473 2.784 7.261 5.016 ;
     RECT  7.225 6.24 7.261 7.752 ;
     RECT  7.189 73.536 7.261 73.56 ;
     RECT  6.757 74.688 7.261 76.968 ;
     RECT  6.509 83.472 7.261 84.024 ;
     RECT  6.937 85.776 7.261 90.12 ;
     RECT  6.805 60.768 7.285 61.32 ;
     RECT  6.419 19.104 7.297 20.088 ;
     RECT  7.117 27.168 7.297 28.008 ;
     RECT  6.037 28.992 7.297 29.016 ;
     RECT  7.297 27.168 7.333 29.016 ;
     RECT  7.261 73.536 7.333 76.968 ;
     RECT  6.829 53.664 7.369 55.704 ;
     RECT  6.613 57.024 7.369 57.096 ;
     RECT  7.237 9.696 7.381 17.592 ;
     RECT  6.653 69.456 7.381 70.68 ;
     RECT  6.445 71.856 7.381 72.264 ;
     RECT  6.221 52.032 7.405 52.632 ;
     RECT  7.369 53.664 7.405 57.096 ;
     RECT  7.045 31.872 7.477 33 ;
     RECT  7.261 2.784 7.513 7.752 ;
     RECT  7.297 18.72 7.549 20.088 ;
     RECT  6.364 63.504 7.585 63.528 ;
     RECT  6.901 64.8 7.585 66.216 ;
     RECT  5.609 46.32 7.621 47.64 ;
     RECT  7.585 63.504 7.621 66.216 ;
     RECT  6.509 79.68 7.628 80.664 ;
     RECT  6.509 82.032 7.628 82.488 ;
     RECT  6.253 38.208 7.657 38.232 ;
     RECT  7.117 39.888 7.657 41.448 ;
     RECT  6.689 42.48 7.657 43.08 ;
     RECT  6.829 34.464 7.693 35.352 ;
     RECT  7.513 2.496 7.765 7.752 ;
     RECT  7.381 9.072 7.801 17.592 ;
     RECT  7.333 73.536 7.801 77.592 ;
     RECT  6.227 78.624 7.801 78.648 ;
     RECT  7.765 2.496 7.808 7.992 ;
     RECT  7.801 9.072 7.808 17.688 ;
     RECT  7.549 18.72 7.808 20.136 ;
     RECT  6.419 21.168 7.808 21.96 ;
     RECT  7.004 23.28 7.808 26.184 ;
     RECT  7.333 27.168 7.808 29.064 ;
     RECT  5.821 30.048 7.808 30.264 ;
     RECT  7.477 31.872 7.808 33.048 ;
     RECT  7.693 34.464 7.808 35.832 ;
     RECT  6.361 37.008 7.808 37.032 ;
     RECT  7.657 38.208 7.808 43.08 ;
     RECT  5.249 44.064 7.808 44.088 ;
     RECT  7.621 45.456 7.808 47.64 ;
     RECT  6.365 49.488 7.808 50.856 ;
     RECT  7.405 52.032 7.808 57.096 ;
     RECT  6.365 59.136 7.808 59.16 ;
     RECT  7.285 60.384 7.808 61.32 ;
     RECT  7.621 63.072 7.808 66.216 ;
     RECT  6.653 67.776 7.808 68.376 ;
     RECT  7.381 69.456 7.808 72.264 ;
     RECT  7.801 73.536 7.808 78.648 ;
     RECT  7.628 79.68 7.808 82.488 ;
     RECT  7.261 83.472 7.808 90.12 ;
     RECT  7.808 2.148 7.912 90.732 ;
     RECT  7.912 2.304 8.104 90.732 ;
     RECT  8.104 23.04 8.165 25.464 ;
     RECT  8.104 40.848 8.165 44.424 ;
     RECT  8.104 11.424 8.201 13.608 ;
     RECT  8.104 50.304 8.243 55.464 ;
     RECT  8.104 60.288 8.243 61.32 ;
     RECT  8.201 11.424 8.245 11.448 ;
     RECT  8.243 50.304 8.284 54.648 ;
     RECT  8.104 14.976 8.345 16.392 ;
     RECT  8.104 19.296 8.345 21.432 ;
     RECT  8.104 2.304 8.381 10.152 ;
     RECT  8.104 26.496 8.417 35.832 ;
     RECT  8.284 50.304 8.417 54.504 ;
     RECT  8.417 26.496 8.489 28.488 ;
     RECT  8.417 29.76 8.489 35.832 ;
     RECT  8.417 50.304 8.531 51.288 ;
     RECT  8.381 2.304 8.561 7.704 ;
     RECT  8.104 38.256 8.561 39.864 ;
     RECT  8.104 71.328 8.597 72.84 ;
     RECT  8.531 50.304 8.633 51.24 ;
     RECT  8.243 60.384 8.633 61.32 ;
     RECT  8.104 74.64 8.633 78.696 ;
     RECT  8.561 2.304 8.705 7.656 ;
     RECT  8.104 17.664 8.741 17.688 ;
     RECT  8.633 60.96 8.749 61.32 ;
     RECT  8.489 29.76 8.777 33.048 ;
     RECT  8.633 74.64 8.819 74.808 ;
     RECT  8.633 75.888 8.819 78.696 ;
     RECT  8.104 37.056 8.915 37.272 ;
     RECT  7.549 0.528 8.917 0.552 ;
     RECT  8.417 52.704 8.921 54.504 ;
     RECT  8.104 69.456 8.921 70.296 ;
     RECT  8.345 19.296 8.957 19.608 ;
     RECT  8.104 45.456 8.957 48.552 ;
     RECT  8.104 79.728 8.963 90.168 ;
     RECT  8.777 29.76 9.029 32.232 ;
     RECT  8.489 34.464 9.029 35.832 ;
     RECT  8.561 38.256 9.029 38.28 ;
     RECT  8.201 12.432 9.109 13.608 ;
     RECT  8.345 14.976 9.109 15.528 ;
     RECT  8.819 76.368 9.109 78.696 ;
     RECT  8.963 79.728 9.109 79.752 ;
     RECT  8.957 19.488 9.137 19.608 ;
     RECT  8.957 45.696 9.137 48.552 ;
     RECT  8.345 20.592 9.169 21.432 ;
     RECT  8.165 23.04 9.169 23.064 ;
     RECT  8.165 24.096 9.169 25.464 ;
     RECT  8.165 40.848 9.169 42.552 ;
     RECT  8.165 43.68 9.169 44.424 ;
     RECT  8.819 74.64 9.173 74.664 ;
     RECT  9.169 20.592 9.209 21.48 ;
     RECT  9.029 29.76 9.209 32.04 ;
     RECT  8.104 57.024 9.241 57.096 ;
     RECT  8.104 65.52 9.241 66.264 ;
     RECT  9.109 12.432 9.277 15.528 ;
     RECT  9.277 12.096 9.281 15.528 ;
     RECT  9.241 56.88 9.281 57.096 ;
     RECT  9.241 65.52 9.281 66.84 ;
     RECT  8.629 91.2 9.301 91.272 ;
     RECT  9.301 91.2 9.313 91.8 ;
     RECT  9.209 29.76 9.389 30.888 ;
     RECT  9.281 65.52 9.404 65.832 ;
     RECT  8.381 8.832 9.421 10.152 ;
     RECT  9.169 23.04 9.421 25.464 ;
     RECT  8.705 2.784 9.425 7.656 ;
     RECT  9.109 76.368 9.425 79.752 ;
     RECT  8.597 71.328 9.461 72.36 ;
     RECT  8.921 69.456 9.493 69.48 ;
     RECT  9.281 66.816 9.497 66.84 ;
     RECT  9.281 14.208 9.541 15.528 ;
     RECT  8.561 39.504 9.565 39.864 ;
     RECT  9.169 40.848 9.565 44.424 ;
     RECT  9.493 68.928 9.565 69.48 ;
     RECT  9.461 72.336 9.569 72.36 ;
     RECT  8.963 80.832 9.569 90.168 ;
     RECT  9.445 63.12 9.601 63.144 ;
     RECT  9.404 64.896 9.601 65.832 ;
     RECT  9.313 91.2 9.635 91.848 ;
     RECT  9.601 62.4 9.637 63.144 ;
     RECT  9.601 64.32 9.637 65.832 ;
     RECT  9.565 68.64 9.637 69.48 ;
     RECT  9.541 14.208 9.647 15.576 ;
     RECT  9.169 16.752 9.647 17.064 ;
     RECT  8.633 50.832 9.673 51.24 ;
     RECT  9.637 68.256 9.683 69.48 ;
     RECT  9.569 80.88 9.733 90.168 ;
     RECT  9.635 91.2 9.733 91.8 ;
     RECT  9.673 50.832 9.745 51.624 ;
     RECT  9.137 45.696 9.749 47.4 ;
     RECT  9.209 32.016 9.785 32.04 ;
     RECT  9.425 3.36 9.817 7.656 ;
     RECT  9.421 8.784 9.817 10.152 ;
     RECT  9.209 20.976 9.817 21.48 ;
     RECT  9.421 22.752 9.817 25.464 ;
     RECT  8.489 26.496 9.817 26.856 ;
     RECT  9.817 22.752 9.821 26.856 ;
     RECT  9.029 34.464 9.821 35.592 ;
     RECT  9.425 76.368 9.821 79.224 ;
     RECT  9.647 14.208 9.829 17.064 ;
     RECT  8.917 0.192 9.857 0.552 ;
     RECT  9.745 50.832 9.857 51.96 ;
     RECT  8.921 53.376 9.889 54.36 ;
     RECT  9.733 80.88 9.893 91.8 ;
     RECT  9.817 20.976 9.923 21.672 ;
     RECT  9.821 22.752 9.923 24.456 ;
     RECT  9.893 80.88 9.923 91.224 ;
     RECT  9.461 71.328 9.925 71.352 ;
     RECT  8.489 27.936 9.961 28.488 ;
     RECT  9.389 29.76 9.961 30.84 ;
     RECT  9.889 53.376 9.961 55.08 ;
     RECT  9.961 27.936 9.965 30.84 ;
     RECT  9.137 48.48 9.997 48.552 ;
     RECT  9.421 49.536 9.997 49.56 ;
     RECT  9.923 20.976 10.001 21.48 ;
     RECT  9.923 22.752 10.001 23.064 ;
     RECT  9.821 76.368 10.001 76.392 ;
     RECT  9.961 53.088 10.019 55.08 ;
     RECT  9.281 56.88 10.019 57.048 ;
     RECT  10.019 53.088 10.069 54.936 ;
     RECT  9.821 25.536 10.073 26.856 ;
     RECT  9.749 45.792 10.133 47.4 ;
     RECT  9.997 48.48 10.133 49.56 ;
     RECT  9.281 12.096 10.177 12.888 ;
     RECT  9.932 60.24 10.177 60.264 ;
     RECT  9.965 30.384 10.181 30.84 ;
     RECT  9.445 1.728 10.211 1.752 ;
     RECT  9.829 14.208 10.213 17.112 ;
     RECT  9.137 19.488 10.213 19.512 ;
     RECT  9.821 34.464 10.217 35.112 ;
     RECT  10.133 45.792 10.217 49.56 ;
     RECT  9.857 0.24 10.249 0.552 ;
     RECT  10.217 48.576 10.249 49.56 ;
     RECT  9.857 50.832 10.249 51.624 ;
     RECT  8.749 61.296 10.289 61.32 ;
     RECT  9.565 38.928 10.307 44.424 ;
     RECT  9.817 3.36 10.321 10.152 ;
     RECT  10.307 38.928 10.321 39.912 ;
     RECT  9.709 58.656 10.321 58.68 ;
     RECT  10.181 30.816 10.325 30.84 ;
     RECT  10.321 38.064 10.325 39.912 ;
     RECT  10.325 38.064 10.348 39.672 ;
     RECT  10.249 0.24 10.355 0.6 ;
     RECT  9.637 62.4 10.361 65.832 ;
     RECT  10.073 26.784 10.429 26.856 ;
     RECT  9.965 27.936 10.429 29.208 ;
     RECT  10.361 64.32 10.429 65.832 ;
     RECT  10.001 21.312 10.433 21.48 ;
     RECT  10.355 0.24 10.499 0.408 ;
     RECT  10.213 19.488 10.501 19.896 ;
     RECT  10.213 14.208 10.537 17.976 ;
     RECT  10.501 19.44 10.537 19.896 ;
     RECT  10.508 33.36 10.595 33.384 ;
     RECT  10.429 26.784 10.621 29.208 ;
     RECT  10.321 58.656 10.649 59.256 ;
     RECT  10.649 59.232 10.681 59.256 ;
     RECT  10.177 60.24 10.681 60.312 ;
     RECT  9.821 77.472 10.681 79.224 ;
     RECT  9.923 80.88 10.681 90.648 ;
     RECT  10.249 48.576 10.685 51.624 ;
     RECT  10.321 3.36 10.789 10.872 ;
     RECT  8.915 37.056 10.789 37.08 ;
     RECT  10.348 38.064 10.789 39.48 ;
     RECT  10.685 48.72 10.793 51.624 ;
     RECT  10.177 11.904 10.825 12.888 ;
     RECT  9.925 70.992 10.825 71.352 ;
     RECT  10.793 48.816 10.829 51.624 ;
     RECT  10.789 37.056 10.835 39.48 ;
     RECT  10.825 70.992 10.837 72.168 ;
     RECT  10.825 11.904 10.861 13.128 ;
     RECT  10.537 14.208 10.861 19.896 ;
     RECT  10.001 22.752 10.865 22.776 ;
     RECT  10.217 45.792 10.865 47.16 ;
     RECT  10.681 77.472 10.883 90.648 ;
     RECT  10.499 0.24 10.885 0.264 ;
     RECT  10.883 80.832 10.885 90.648 ;
     RECT  10.837 70.992 10.973 72.408 ;
     RECT  10.883 77.472 10.973 79.56 ;
     RECT  10.973 77.472 11.005 77.976 ;
     RECT  10.829 49.488 11.009 51.624 ;
     RECT  10.885 80.832 11.029 91.176 ;
     RECT  10.789 2.976 11.045 10.872 ;
     RECT  10.217 34.752 11.116 35.112 ;
     RECT  10.835 38.928 11.117 39.48 ;
     RECT  10.361 62.4 11.149 63.24 ;
     RECT  11.029 80.832 11.153 91.272 ;
     RECT  11.005 77.088 11.171 77.976 ;
     RECT  10.835 37.056 11.185 37.608 ;
     RECT  11.185 36.864 11.189 37.608 ;
     RECT  11.153 80.832 11.189 91.176 ;
     RECT  11.045 3.408 11.221 10.872 ;
     RECT  10.861 11.904 11.221 19.896 ;
     RECT  11.009 49.824 11.257 51.624 ;
     RECT  10.865 45.936 11.267 47.16 ;
     RECT  10.307 41.184 11.293 44.424 ;
     RECT  10.621 26.832 11.297 29.208 ;
     RECT  10.717 32.064 11.329 32.088 ;
     RECT  10.019 56.88 11.333 56.904 ;
     RECT  10.681 59.232 11.365 60.312 ;
     RECT  11.149 61.584 11.365 63.24 ;
     RECT  11.189 36.864 11.369 36.888 ;
     RECT  10.973 71.808 11.405 72.408 ;
     RECT  11.117 39.408 11.413 39.48 ;
     RECT  11.293 41.184 11.413 44.472 ;
     RECT  11.365 59.232 11.413 63.24 ;
     RECT  10.429 64.32 11.413 66.744 ;
     RECT  11.221 3.408 11.437 19.896 ;
     RECT  9.923 24.048 11.437 24.456 ;
     RECT  11.413 59.232 11.441 66.744 ;
     RECT  11.441 59.76 11.449 66.744 ;
     RECT  11.372 69.984 11.459 70.008 ;
     RECT  11.437 3.408 11.477 20.136 ;
     RECT  10.069 52.992 11.477 54.936 ;
     RECT  9.683 68.256 11.509 68.952 ;
     RECT  10.717 76.08 11.509 76.104 ;
     RECT  11.413 39.408 11.513 44.472 ;
     RECT  11.029 73.536 11.549 73.56 ;
     RECT  11.509 67.824 11.557 68.952 ;
     RECT  10.073 25.536 11.581 25.56 ;
     RECT  11.329 32.064 11.585 32.568 ;
     RECT  11.405 72.288 11.593 72.408 ;
     RECT  11.077 33.6 11.621 33.624 ;
     RECT  11.557 67.824 11.651 69 ;
     RECT  11.257 1.728 11.653 1.752 ;
     RECT  11.437 30.816 11.653 30.84 ;
     RECT  11.585 32.064 11.653 32.472 ;
     RECT  11.477 3.408 11.657 15.288 ;
     RECT  11.653 30.816 11.657 32.472 ;
     RECT  11.509 75.84 11.657 76.104 ;
     RECT  11.297 27.216 11.689 29.208 ;
     RECT  11.477 16.704 11.693 20.136 ;
     RECT  11.657 76.08 11.749 76.104 ;
     RECT  11.477 52.992 11.756 54.12 ;
     RECT  11.693 18.72 11.761 20.136 ;
     RECT  11.651 68.256 11.765 69 ;
     RECT  11.749 76.08 11.765 76.392 ;
     RECT  11.267 45.936 11.788 46.968 ;
     RECT  11.653 1.728 11.795 1.992 ;
     RECT  11.765 68.352 11.795 68.376 ;
     RECT  10.885 0.192 11.797 0.264 ;
     RECT  11.795 1.728 11.797 1.8 ;
     RECT  11.257 49.824 11.801 51.768 ;
     RECT  11.765 76.368 11.836 76.392 ;
     RECT  11.657 3.792 11.837 15.288 ;
     RECT  11.837 3.936 11.843 13.656 ;
     RECT  11.756 52.944 11.843 54.12 ;
     RECT  10.973 78.96 11.905 79.56 ;
     RECT  11.189 80.832 11.905 90.6 ;
     RECT  11.329 21.6 11.928 21.624 ;
     RECT  11.437 23.328 11.928 24.456 ;
     RECT  11.797 0.192 11.939 1.8 ;
     RECT  11.689 27.216 11.941 29.64 ;
     RECT  11.657 30.816 11.941 31.368 ;
     RECT  11.171 77.472 11.941 77.976 ;
     RECT  11.905 78.96 11.941 90.6 ;
     RECT  11.941 27.216 11.987 31.368 ;
     RECT  11.941 77.472 11.987 90.6 ;
     RECT  11.761 18.72 11.989 20.424 ;
     RECT  11.928 21.6 11.989 24.456 ;
     RECT  11.987 80.4 12.017 90.6 ;
     RECT  11.987 30.24 12.028 31.224 ;
     RECT  11.989 18.72 12.035 24.456 ;
     RECT  12.017 80.4 12.053 90.504 ;
     RECT  11.116 34.896 12.085 35.112 ;
     RECT  11.987 77.472 12.172 78.648 ;
     RECT  12.035 20.784 12.233 24.456 ;
     RECT  11.801 49.824 12.233 51.288 ;
     RECT  12.193 36.624 12.301 36.648 ;
     RECT  11.788 46.32 12.337 46.968 ;
     RECT  12.233 21.408 12.373 24.456 ;
     RECT  11.581 25.44 12.373 25.56 ;
     RECT  11.473 70.416 12.373 70.44 ;
     RECT  11.449 63.648 12.437 66.744 ;
     RECT  12.085 34.416 12.445 35.112 ;
     RECT  12.301 36.336 12.445 36.648 ;
     RECT  11.843 52.992 12.469 54.12 ;
     RECT  11.513 40.848 12.481 44.472 ;
     RECT  11.837 14.976 12.517 15.288 ;
     RECT  11.693 16.704 12.517 17.64 ;
     RECT  11.449 59.76 12.517 62.184 ;
     RECT  11.657 32.448 12.589 32.472 ;
     RECT  12.517 59.232 12.589 62.184 ;
     RECT  11.939 0.192 12.629 0.552 ;
     RECT  12.589 59.232 12.661 62.232 ;
     RECT  12.437 63.648 12.661 67.272 ;
     RECT  11.513 39.456 12.697 39.48 ;
     RECT  12.469 56.448 12.697 56.472 ;
     RECT  12.589 32.448 12.733 33.384 ;
     RECT  12.445 34.416 12.733 36.648 ;
     RECT  12.697 56.448 12.757 57.432 ;
     RECT  11.987 27.216 12.805 29.064 ;
     RECT  11.173 92.64 12.809 92.664 ;
     RECT  12.517 14.976 13.021 17.64 ;
     RECT  12.028 30.816 13.021 31.224 ;
     RECT  12.697 38.64 13.021 39.48 ;
     RECT  11.939 1.728 13.025 1.8 ;
     RECT  12.373 21.408 13.052 25.56 ;
     RECT  13.021 79.728 13.052 80.376 ;
     RECT  12.053 81.456 13.052 90.504 ;
     RECT  12.337 46.32 13.093 47.064 ;
     RECT  13.052 79.728 13.093 90.504 ;
     RECT  11.843 4.176 13.165 13.656 ;
     RECT  12.629 0.192 13.18 0.36 ;
     RECT  13.025 1.776 13.208 1.8 ;
     RECT  13.165 2.784 13.208 13.656 ;
     RECT  13.021 14.928 13.208 17.64 ;
     RECT  12.035 18.816 13.208 19.8 ;
     RECT  13.052 21.408 13.208 25.656 ;
     RECT  12.805 26.832 13.208 29.064 ;
     RECT  13.021 30.816 13.208 31.32 ;
     RECT  12.733 32.448 13.208 37.032 ;
     RECT  13.021 38.496 13.208 39.48 ;
     RECT  12.481 40.56 13.208 44.472 ;
     RECT  13.093 46.32 13.208 47.928 ;
     RECT  12.233 50.16 13.208 51.288 ;
     RECT  12.469 52.992 13.208 54.696 ;
     RECT  12.757 56.448 13.208 57.864 ;
     RECT  12.661 59.232 13.208 67.272 ;
     RECT  12.373 70.416 13.208 71.304 ;
     RECT  12.373 73.056 13.208 73.08 ;
     RECT  12.949 74.064 13.208 74.712 ;
     RECT  12.901 75.792 13.208 75.816 ;
     RECT  12.553 76.944 13.208 76.968 ;
     RECT  12.172 78.624 13.208 78.648 ;
     RECT  13.093 79.728 13.208 90.552 ;
     RECT  13.18 0.192 13.235 0.312 ;
     RECT  13.208 1.776 13.312 90.732 ;
     RECT  13.312 1.776 13.504 90.552 ;
     RECT  13.504 5.76 13.529 13.416 ;
     RECT  13.504 73.056 13.565 73.08 ;
     RECT  13.504 1.776 13.601 3.72 ;
     RECT  13.504 14.976 13.601 16.344 ;
     RECT  13.504 30.24 13.619 31.272 ;
     RECT  13.504 52.992 13.715 54.696 ;
     RECT  13.529 10.128 13.745 13.416 ;
     RECT  13.504 37.92 13.745 46.872 ;
     RECT  13.504 47.904 13.763 48.648 ;
     RECT  13.504 21.12 13.781 26.232 ;
     RECT  13.504 81.936 13.781 90.552 ;
     RECT  13.529 5.76 13.889 9.048 ;
     RECT  13.715 54.096 13.889 54.696 ;
     RECT  13.235 0.192 13.925 0.216 ;
     RECT  13.781 22.752 13.925 26.232 ;
     RECT  13.781 21.12 13.961 21.672 ;
     RECT  13.504 33.984 13.961 36.792 ;
     RECT  13.745 37.92 13.997 38.52 ;
     RECT  13.715 52.992 13.997 53.016 ;
     RECT  13.504 60.336 14.033 61.032 ;
     RECT  13.504 55.824 14.069 58.344 ;
     RECT  13.781 81.936 14.105 90.12 ;
     RECT  14.033 60.336 14.141 60.984 ;
     RECT  13.504 79.728 14.141 79.752 ;
     RECT  13.504 18.768 14.177 19.8 ;
     RECT  14.177 19.536 14.213 19.8 ;
     RECT  13.763 47.904 14.213 48.024 ;
     RECT  14.105 81.936 14.249 89.544 ;
     RECT  14.249 81.936 14.257 89.448 ;
     RECT  13.745 10.128 14.285 11.4 ;
     RECT  13.504 70.656 14.291 71.352 ;
     RECT  14.069 55.824 14.321 57.864 ;
     RECT  14.141 60.384 14.321 60.984 ;
     RECT  14.291 70.656 14.329 70.68 ;
     RECT  13.504 78.624 14.393 78.648 ;
     RECT  13.619 30.864 14.429 31.272 ;
     RECT  14.321 55.824 14.429 57.432 ;
     RECT  13.504 65.568 14.429 65.784 ;
     RECT  14.257 81.936 14.429 86.808 ;
     RECT  14.321 60.96 14.435 60.984 ;
     RECT  13.504 62.16 14.437 63.816 ;
     RECT  13.961 36.096 14.465 36.792 ;
     RECT  13.745 39.6 14.465 46.872 ;
     RECT  14.429 56.976 14.501 57.432 ;
     RECT  14.429 83.616 14.501 85.416 ;
     RECT  14.285 10.896 14.537 11.4 ;
     RECT  13.925 24.48 14.537 26.232 ;
     RECT  14.257 87.792 14.537 89.448 ;
     RECT  14.501 57.168 14.573 57.432 ;
     RECT  14.429 86.496 14.573 86.808 ;
     RECT  13.601 2.496 14.605 3.72 ;
     RECT  13.504 50.16 14.605 51.096 ;
     RECT  13.601 14.976 14.609 16.248 ;
     RECT  14.501 84.048 14.627 85.416 ;
     RECT  14.588 69.696 14.629 69.72 ;
     RECT  14.605 2.496 14.641 3.96 ;
     RECT  13.504 28.224 14.641 28.824 ;
     RECT  14.429 31.248 14.641 31.272 ;
     RECT  13.504 32.448 14.641 32.472 ;
     RECT  14.629 68.928 14.675 69.72 ;
     RECT  14.573 86.592 14.681 86.808 ;
     RECT  13.961 21.12 14.713 21.144 ;
     RECT  14.641 28.224 14.713 29.064 ;
     RECT  14.465 39.6 14.753 46.344 ;
     RECT  14.641 31.248 14.825 32.472 ;
     RECT  14.713 28.224 14.861 29.928 ;
     RECT  14.825 31.824 14.861 32.472 ;
     RECT  14.537 87.792 14.861 88.872 ;
     RECT  14.785 17.808 14.893 18.168 ;
     RECT  13.925 22.752 14.897 23.256 ;
     RECT  14.429 55.824 14.897 55.848 ;
     RECT  13.745 12.432 14.917 13.416 ;
     RECT  14.609 14.976 14.917 15.384 ;
     RECT  14.917 12.432 14.963 15.384 ;
     RECT  14.641 2.496 14.969 4.2 ;
     RECT  14.861 87.84 14.969 88.872 ;
     RECT  14.537 11.136 15.073 11.4 ;
     RECT  14.963 12.432 15.073 15 ;
     RECT  14.897 23.136 15.113 23.256 ;
     RECT  13.889 54.096 15.149 54.12 ;
     RECT  14.969 3.936 15.181 4.2 ;
     RECT  15.113 23.232 15.185 23.256 ;
     RECT  14.437 62.64 15.185 63.816 ;
     RECT  15.181 3.936 15.217 4.296 ;
     RECT  13.961 33.984 15.217 34.92 ;
     RECT  13.889 5.808 15.221 9.048 ;
     RECT  14.861 28.224 15.253 29.688 ;
     RECT  14.713 20.976 15.289 21.144 ;
     RECT  14.861 32.448 15.293 32.472 ;
     RECT  14.537 24.912 15.325 26.232 ;
     RECT  14.213 19.728 15.361 19.8 ;
     RECT  15.289 20.832 15.361 21.144 ;
     RECT  14.893 16.512 15.397 18.168 ;
     RECT  15.361 19.728 15.397 21.144 ;
     RECT  14.465 36.768 15.397 36.792 ;
     RECT  13.997 38.208 15.397 38.52 ;
     RECT  14.753 39.6 15.397 44.712 ;
     RECT  15.325 61.008 15.397 61.032 ;
     RECT  15.217 33.984 15.401 35.064 ;
     RECT  14.675 68.928 15.401 68.952 ;
     RECT  15.397 38.208 15.437 44.712 ;
     RECT  15.397 16.512 15.443 21.144 ;
     RECT  15.397 60.384 15.443 61.032 ;
     RECT  14.753 46.32 15.505 46.344 ;
     RECT  14.429 81.936 15.505 81.96 ;
     RECT  15.443 16.512 15.509 18.792 ;
     RECT  15.509 16.656 15.532 18.696 ;
     RECT  15.217 3.936 15.541 4.68 ;
     RECT  15.221 5.808 15.541 7.944 ;
     RECT  15.443 19.776 15.541 21.144 ;
     RECT  15.401 34.128 15.58 35.064 ;
     RECT  14.627 84.288 15.589 85.416 ;
     RECT  14.533 59.184 15.653 59.208 ;
     RECT  15.577 52.464 15.661 52.488 ;
     RECT  15.397 36.768 15.685 37.08 ;
     RECT  15.644 56.112 15.685 56.136 ;
     RECT  14.573 57.168 15.685 57.192 ;
     RECT  15.532 16.656 15.689 18.168 ;
     RECT  14.969 2.496 15.725 2.952 ;
     RECT  15.58 34.416 15.725 35.064 ;
     RECT  15.361 78.336 15.725 78.36 ;
     RECT  15.589 83.76 15.725 85.416 ;
     RECT  15.685 36.432 15.731 37.08 ;
     RECT  15.685 56.112 15.731 57.192 ;
     RECT  15.469 10.08 15.757 10.104 ;
     RECT  15.073 11.136 15.757 15 ;
     RECT  14.605 50.16 15.757 51.384 ;
     RECT  15.725 2.832 15.761 2.952 ;
     RECT  15.325 24.912 15.781 26.664 ;
     RECT  15.253 27.792 15.781 29.688 ;
     RECT  15.725 34.416 15.797 34.44 ;
     RECT  14.681 86.592 15.797 86.616 ;
     RECT  15.781 24.912 15.827 29.688 ;
     RECT  15.731 56.976 15.829 57.192 ;
     RECT  14.429 65.664 15.829 65.784 ;
     RECT  15.827 24.912 15.869 29.496 ;
     RECT  15.869 28.224 15.905 29.496 ;
     RECT  15.505 30.72 15.905 30.744 ;
     RECT  15.433 53.952 15.937 53.976 ;
     RECT  15.541 3.936 15.941 7.944 ;
     RECT  15.757 10.08 15.941 15 ;
     RECT  15.221 9.024 15.973 9.048 ;
     RECT  15.941 10.08 15.973 10.584 ;
     RECT  15.973 9.024 15.977 10.584 ;
     RECT  15.937 53.904 16.009 53.976 ;
     RECT  15.977 10.128 16.013 10.584 ;
     RECT  15.757 49.008 16.013 51.384 ;
     RECT  15.941 11.76 16.085 15 ;
     RECT  15.437 38.496 16.085 44.712 ;
     RECT  15.761 2.88 16.117 2.952 ;
     RECT  14.969 87.84 16.153 88.392 ;
     RECT  15.541 89.664 16.153 89.688 ;
     RECT  15.941 4.464 16.157 7.944 ;
     RECT  16.009 53.76 16.189 53.976 ;
     RECT  15.829 64.992 16.193 65.784 ;
     RECT  15.869 24.912 16.229 26.664 ;
     RECT  15.361 67.776 16.229 67.8 ;
     RECT  16.189 53.76 16.261 54.648 ;
     RECT  15.865 74.592 16.261 74.616 ;
     RECT  15.541 19.776 16.265 21.576 ;
     RECT  15.505 46.32 16.297 46.584 ;
     RECT  16.157 7.92 16.307 7.944 ;
     RECT  16.013 49.008 16.307 51.096 ;
     RECT  16.085 38.688 16.316 44.712 ;
     RECT  15.977 9.024 16.337 9.144 ;
     RECT  16.316 38.688 16.337 45 ;
     RECT  16.337 38.88 16.355 45 ;
     RECT  16.355 39.984 16.357 45 ;
     RECT  16.297 46.32 16.357 46.68 ;
     RECT  16.085 13.104 16.369 15 ;
     RECT  15.505 81.936 16.369 82.776 ;
     RECT  15.725 83.76 16.369 84.36 ;
     RECT  15.725 85.344 16.369 85.416 ;
     RECT  16.157 4.464 16.373 6.84 ;
     RECT  16.357 39.984 16.373 46.68 ;
     RECT  16.153 87.84 16.373 89.688 ;
     RECT  16.261 53.76 16.409 54.696 ;
     RECT  15.361 32.736 16.441 32.76 ;
     RECT  16.193 65.472 16.453 65.784 ;
     RECT  16.265 19.776 16.481 20.856 ;
     RECT  16.397 70.128 16.481 70.152 ;
     RECT  14.213 48 16.513 48.024 ;
     RECT  16.307 49.008 16.513 49.368 ;
     RECT  16.307 51.072 16.517 51.096 ;
     RECT  16.297 23.184 16.549 23.208 ;
     RECT  16.369 85.344 16.595 85.608 ;
     RECT  16.549 70.656 16.633 70.68 ;
     RECT  16.373 4.464 16.697 6.552 ;
     RECT  16.085 11.76 16.697 12.12 ;
     RECT  16.369 13.104 16.697 15.048 ;
     RECT  15.689 16.656 16.697 17.832 ;
     RECT  16.373 44.4 16.697 46.68 ;
     RECT  15.829 56.976 16.697 57.624 ;
     RECT  16.117 2.88 16.729 3.384 ;
     RECT  15.185 62.64 16.733 63 ;
     RECT  15.443 60.384 16.789 60.552 ;
     RECT  16.697 16.656 16.799 17.64 ;
     RECT  16.453 65.52 16.805 65.784 ;
     RECT  15.788 58.656 16.835 58.92 ;
     RECT  16.789 60 16.835 61.608 ;
     RECT  15.731 36.432 16.837 37.032 ;
     RECT  16.697 46.32 16.837 46.68 ;
     RECT  16.697 12.096 16.841 12.12 ;
     RECT  16.549 76.368 16.841 76.392 ;
     RECT  16.271 55.824 16.873 55.848 ;
     RECT  16.697 56.976 16.873 57.144 ;
     RECT  16.261 74.208 16.877 74.616 ;
     RECT  16.549 23.184 16.913 23.976 ;
     RECT  16.835 58.656 16.913 58.68 ;
     RECT  15.905 28.224 16.94 29.256 ;
     RECT  16.799 15.984 16.949 17.64 ;
     RECT  16.835 61.008 16.949 61.608 ;
     RECT  16.549 86.736 16.949 86.76 ;
     RECT  16.909 76.512 17.017 76.584 ;
     RECT  16.369 81.936 17.017 84.36 ;
     RECT  16.94 27.888 17.027 29.256 ;
     RECT  16.229 25.056 17.045 26.664 ;
     RECT  17.027 28.512 17.077 29.256 ;
     RECT  16.225 30.864 17.077 30.888 ;
     RECT  16.441 32.16 17.077 32.76 ;
     RECT  17.053 34.416 17.077 34.44 ;
     RECT  17.017 81.504 17.101 84.36 ;
     RECT  17.045 25.056 17.123 26.808 ;
     RECT  17.077 28.512 17.123 30.888 ;
     RECT  17.123 25.2 17.129 26.808 ;
     RECT  16.409 53.76 17.129 53.976 ;
     RECT  16.873 55.824 17.129 57.144 ;
     RECT  17.101 81.936 17.161 84.36 ;
     RECT  16.595 85.344 17.161 85.416 ;
     RECT  17.123 30 17.164 30.888 ;
     RECT  16.337 9.024 17.197 9.048 ;
     RECT  16.837 36.336 17.197 37.032 ;
     RECT  16.697 5.712 17.201 6.552 ;
     RECT  16.373 39.984 17.219 43.08 ;
     RECT  17.077 32.16 17.233 33.288 ;
     RECT  17.077 34.32 17.233 34.44 ;
     RECT  17.197 35.52 17.233 37.08 ;
     RECT  16.697 13.104 17.237 15 ;
     RECT  16.373 87.84 17.237 88.776 ;
     RECT  17.197 8.208 17.269 9.048 ;
     RECT  16.513 48 17.269 49.368 ;
     RECT  17.233 32.16 17.305 37.08 ;
     RECT  17.129 53.952 17.309 53.976 ;
     RECT  16.835 60 17.345 60.024 ;
     RECT  16.657 52.704 17.377 52.728 ;
     RECT  15.253 80.304 17.377 80.328 ;
     RECT  17.129 55.824 17.413 55.848 ;
     RECT  16.081 78 17.449 78.024 ;
     RECT  17.377 21.12 17.485 21.144 ;
     RECT  17.161 81.936 17.489 85.416 ;
     RECT  17.269 7.776 17.521 9.048 ;
     RECT  16.013 10.128 17.521 10.152 ;
     RECT  17.485 21.12 17.521 21.192 ;
     RECT  17.161 22.176 17.521 22.2 ;
     RECT  16.733 62.976 17.561 63 ;
     RECT  16.729 2.784 17.564 3.384 ;
     RECT  16.697 4.464 17.564 4.488 ;
     RECT  17.521 7.776 17.593 10.152 ;
     RECT  17.237 87.84 17.593 88.488 ;
     RECT  16.949 61.008 17.597 61.032 ;
     RECT  17.237 13.104 17.701 13.752 ;
     RECT  17.129 57.024 17.701 57.144 ;
     RECT  17.629 58.128 17.701 58.152 ;
     RECT  17.708 11.52 17.749 11.544 ;
     RECT  17.521 21.12 17.773 22.2 ;
     RECT  16.913 23.184 17.773 23.688 ;
     RECT  17.017 76.512 17.917 76.92 ;
     RECT  17.449 78 17.917 78.456 ;
     RECT  17.749 11.232 17.989 11.544 ;
     RECT  17.701 12.528 17.989 13.752 ;
     RECT  17.413 55.584 17.989 55.848 ;
     RECT  17.521 51.36 18.025 51.384 ;
     RECT  16.909 90.48 18.025 90.504 ;
     RECT  16.877 74.208 18.097 74.232 ;
     RECT  16.481 19.776 18.133 19.896 ;
     RECT  17.653 39.312 18.133 39.336 ;
     RECT  17.269 48 18.133 49.512 ;
     RECT  18.025 50.784 18.133 51.384 ;
     RECT  17.237 14.976 18.169 15 ;
     RECT  16.949 15.984 18.169 16.536 ;
     RECT  16.949 17.616 18.169 17.64 ;
     RECT  17.377 52.512 18.277 52.728 ;
     RECT  17.701 54.144 18.277 54.168 ;
     RECT  17.341 71.184 18.277 71.208 ;
     RECT  18.097 74.064 18.277 74.232 ;
     RECT  17.489 81.936 18.277 82.776 ;
     RECT  17.305 32.16 18.349 37.704 ;
     RECT  18.133 38.736 18.349 39.336 ;
     RECT  17.201 5.76 18.373 6.552 ;
     RECT  18.277 71.184 18.38 72.024 ;
     RECT  17.773 21.12 18.385 23.688 ;
     RECT  17.917 76.512 18.421 78.456 ;
     RECT  17.989 55.344 18.457 55.848 ;
     RECT  18.421 75.744 18.457 78.456 ;
     RECT  17.564 2.784 18.469 4.488 ;
     RECT  18.373 5.76 18.469 6.6 ;
     RECT  18.457 55.248 18.469 55.848 ;
     RECT  18.421 67.056 18.469 67.08 ;
     RECT  18.38 70.224 18.469 72.024 ;
     RECT  18.277 73.728 18.469 74.232 ;
     RECT  18.025 90.096 18.529 90.504 ;
     RECT  17.989 11.232 18.565 13.752 ;
     RECT  18.169 14.976 18.565 17.64 ;
     RECT  18.469 2.784 18.608 6.6 ;
     RECT  17.593 7.776 18.608 10.2 ;
     RECT  18.565 11.232 18.608 17.64 ;
     RECT  18.133 18.96 18.608 19.896 ;
     RECT  18.385 21.12 18.608 23.976 ;
     RECT  17.129 25.2 18.608 25.992 ;
     RECT  17.123 28.512 18.608 28.968 ;
     RECT  17.164 30.864 18.608 30.888 ;
     RECT  18.349 32.16 18.608 39.336 ;
     RECT  17.219 40.416 18.608 43.08 ;
     RECT  16.697 44.4 18.608 44.76 ;
     RECT  16.837 46.32 18.608 46.92 ;
     RECT  18.133 48 18.608 51.48 ;
     RECT  18.277 52.512 18.608 54.168 ;
     RECT  18.469 55.248 18.608 55.992 ;
     RECT  17.701 57.024 18.608 58.152 ;
     RECT  17.809 62.16 18.608 62.232 ;
     RECT  16.981 64.32 18.608 64.344 ;
     RECT  16.805 65.76 18.608 65.784 ;
     RECT  18.469 67.056 18.608 67.704 ;
     RECT  18.469 70.224 18.608 74.232 ;
     RECT  18.457 75.744 18.608 78.6 ;
     RECT  17.377 80.304 18.608 80.376 ;
     RECT  18.277 81.648 18.608 82.776 ;
     RECT  17.489 84 18.608 85.416 ;
     RECT  17.593 87.024 18.608 88.488 ;
     RECT  18.529 90.048 18.608 90.504 ;
     RECT  18.608 2.148 18.712 90.732 ;
     RECT  18.712 2.418 18.904 90.462 ;
     RECT  18.904 8.976 18.965 10.2 ;
     RECT  18.904 19.104 18.965 29.064 ;
     RECT  18.904 32.304 19.001 32.568 ;
     RECT  18.904 13.824 19.037 17.688 ;
     RECT  18.904 4.08 19.043 5.784 ;
     RECT  18.965 19.104 19.043 22.728 ;
     RECT  18.904 76.512 19.073 77.64 ;
     RECT  18.904 33.936 19.109 36.36 ;
     RECT  19.109 33.936 19.181 34.776 ;
     RECT  18.904 81.648 19.187 85.416 ;
     RECT  18.965 23.712 19.253 29.064 ;
     RECT  18.904 64.032 19.331 64.392 ;
     RECT  18.904 59.184 19.344 62.76 ;
     RECT  18.904 50.112 19.379 50.76 ;
     RECT  18.904 80.304 19.397 80.328 ;
     RECT  18.904 38.016 19.469 43.32 ;
     RECT  19.043 4.08 19.505 5.16 ;
     RECT  19.037 13.824 19.505 15.768 ;
     RECT  19.253 26.736 19.541 29.064 ;
     RECT  18.904 90 19.613 90.072 ;
     RECT  19.344 59.184 19.721 61.608 ;
     RECT  19.253 23.712 19.756 25.32 ;
     RECT  19.344 62.736 19.865 62.76 ;
     RECT  18.904 45.792 19.909 48.264 ;
     RECT  19.721 59.184 19.909 59.88 ;
     RECT  19.043 19.104 19.916 21.576 ;
     RECT  19.541 27.744 19.933 29.064 ;
     RECT  18.904 30.24 19.933 30.264 ;
     RECT  18.904 57.84 19.933 58.152 ;
     RECT  19.909 59.184 19.933 59.208 ;
     RECT  18.904 78.72 19.933 78.744 ;
     RECT  19.909 45.792 19.955 48.84 ;
     RECT  19.379 50.112 19.955 50.136 ;
     RECT  18.904 11.232 19.957 12.168 ;
     RECT  18.965 8.976 19.969 9.96 ;
     RECT  19.957 10.992 19.969 12.552 ;
     RECT  19.541 26.736 19.973 26.76 ;
     RECT  19.933 57.84 19.973 59.208 ;
     RECT  19.721 61.344 19.973 61.608 ;
     RECT  19.969 8.976 20.003 12.552 ;
     RECT  19.916 18.768 20.005 21.576 ;
     RECT  19.043 22.704 20.005 22.728 ;
     RECT  18.904 52.224 20.005 54.648 ;
     RECT  18.904 55.632 20.005 56.664 ;
     RECT  19.973 57.84 20.005 58.776 ;
     RECT  19.933 27.744 20.009 30.264 ;
     RECT  20.009 27.984 20.017 30.264 ;
     RECT  19.187 81.648 20.017 83.208 ;
     RECT  19.469 38.016 20.045 43.08 ;
     RECT  20.005 52.224 20.045 58.776 ;
     RECT  20.005 18.768 20.051 22.728 ;
     RECT  20.003 8.976 20.077 11.016 ;
     RECT  20.051 21.12 20.077 22.728 ;
     RECT  19.756 23.712 20.077 25.224 ;
     RECT  20.017 27.984 20.081 28.968 ;
     RECT  20.045 40.944 20.081 43.08 ;
     RECT  19.001 32.352 20.113 32.568 ;
     RECT  20.077 8.544 20.117 11.016 ;
     RECT  20.081 27.984 20.117 28.008 ;
     RECT  20.051 18.768 20.147 19.8 ;
     RECT  19.505 13.824 20.153 15.432 ;
     RECT  20.045 38.016 20.156 39.864 ;
     RECT  19.037 16.944 20.185 17.688 ;
     RECT  20.147 18.768 20.185 19.512 ;
     RECT  20.045 52.224 20.185 53.544 ;
     RECT  20.185 16.56 20.225 19.512 ;
     RECT  19.109 36.336 20.225 36.36 ;
     RECT  20.156 37.488 20.243 39.864 ;
     RECT  18.904 44.4 20.245 44.76 ;
     RECT  19.955 45.792 20.245 46.92 ;
     RECT  20.117 10.992 20.261 11.016 ;
     RECT  19.073 76.512 20.285 76.776 ;
     RECT  20.245 44.4 20.332 46.92 ;
     RECT  20.252 31.296 20.339 31.32 ;
     RECT  20.285 76.512 20.339 76.824 ;
     RECT  18.904 87.264 20.348 88.632 ;
     RECT  20.339 76.56 20.369 76.824 ;
     RECT  19.933 78.672 20.389 78.744 ;
     RECT  19.969 79.776 20.396 79.8 ;
     RECT  20.113 32.352 20.401 33.048 ;
     RECT  19.181 34.752 20.401 34.776 ;
     RECT  18.904 72.384 20.401 72.408 ;
     RECT  20.389 78.528 20.435 78.744 ;
     RECT  20.293 6 20.437 6.072 ;
     RECT  18.904 7.056 20.437 7.08 ;
     RECT  20.081 40.992 20.437 43.08 ;
     RECT  20.332 44.4 20.437 45.144 ;
     RECT  20.017 81.648 20.437 82.968 ;
     RECT  20.225 16.56 20.473 17.112 ;
     RECT  20.435 78.528 20.477 78.648 ;
     RECT  20.396 79.776 20.483 80.472 ;
     RECT  18.904 2.784 20.531 3.096 ;
     RECT  20.185 51.504 20.531 53.544 ;
     RECT  19.955 48 20.549 48.84 ;
     RECT  20.483 79.776 20.549 79.8 ;
     RECT  20.045 54.576 20.585 58.776 ;
     RECT  20.369 76.56 20.585 76.776 ;
     RECT  20.531 51.504 20.621 52.92 ;
     RECT  18.904 65.76 20.653 65.784 ;
     RECT  20.531 2.832 20.657 3.096 ;
     RECT  20.437 6 20.657 7.08 ;
     RECT  20.117 8.544 20.657 9.96 ;
     RECT  20.077 21.12 20.657 25.224 ;
     RECT  20.585 54.624 20.657 58.776 ;
     RECT  20.657 54.768 20.693 58.776 ;
     RECT  19.613 90 20.693 90.024 ;
     RECT  19.331 64.368 20.725 64.392 ;
     RECT  20.653 65.76 20.725 66.504 ;
     RECT  20.348 86.592 20.725 88.632 ;
     RECT  20.003 12.096 20.729 12.552 ;
     RECT  20.657 2.88 20.761 3.096 ;
     RECT  19.505 4.08 20.761 4.584 ;
     RECT  20.761 2.88 20.765 4.584 ;
     RECT  20.725 64.368 20.773 66.504 ;
     RECT  20.401 34.224 20.801 34.776 ;
     RECT  20.617 74.592 20.801 74.616 ;
     RECT  20.153 15.408 20.837 15.432 ;
     RECT  20.401 72.384 20.837 72.792 ;
     RECT  20.653 63.024 20.869 63.048 ;
     RECT  20.773 64.368 20.869 66.744 ;
     RECT  20.693 57.84 20.909 58.776 ;
     RECT  19.973 61.344 20.945 61.368 ;
     RECT  19.187 84.432 21.013 85.416 ;
     RECT  20.725 86.592 21.013 88.872 ;
     RECT  20.332 46.32 21.017 46.92 ;
     RECT  20.869 63.024 21.017 66.744 ;
     RECT  20.693 54.768 21.053 56.664 ;
     RECT  20.549 48 21.089 48.456 ;
     RECT  20.837 72.768 21.089 72.792 ;
     RECT  20.765 2.928 21.109 4.584 ;
     RECT  20.657 6 21.109 6.696 ;
     RECT  21.017 63.792 21.155 66.744 ;
     RECT  20.581 26.688 21.157 26.712 ;
     RECT  21.155 63.792 21.161 65.592 ;
     RECT  20.657 8.976 21.193 9.96 ;
     RECT  20.473 16.512 21.197 17.112 ;
     RECT  20.243 38.016 21.197 39.864 ;
     RECT  20.437 40.992 21.197 45.144 ;
     RECT  21.161 63.792 21.197 64.392 ;
     RECT  20.621 51.504 21.229 51.528 ;
     RECT  21.109 2.928 21.233 6.696 ;
     RECT  20.017 30.24 21.233 30.264 ;
     RECT  21.013 84.432 21.233 89.736 ;
     RECT  20.225 18.144 21.265 19.512 ;
     RECT  20.437 81.504 21.269 82.968 ;
     RECT  20.153 13.824 21.337 14.136 ;
     RECT  21.265 18.144 21.341 19.896 ;
     RECT  20.401 31.68 21.341 33.048 ;
     RECT  21.229 51.312 21.341 51.528 ;
     RECT  20.833 49.584 21.349 49.608 ;
     RECT  21.341 51.312 21.395 51.336 ;
     RECT  21.089 48 21.445 48.264 ;
     RECT  21.349 49.584 21.445 50.04 ;
     RECT  21.337 13.296 21.449 14.136 ;
     RECT  21.017 46.32 21.449 46.776 ;
     RECT  21.053 54.768 21.449 55.896 ;
     RECT  21.341 18.24 21.481 19.896 ;
     RECT  20.657 21.12 21.481 21.864 ;
     RECT  21.449 54.864 21.485 55.896 ;
     RECT  21.157 26.4 21.553 26.712 ;
     RECT  21.197 40.992 21.553 42.552 ;
     RECT  21.445 49.584 21.557 50.712 ;
     RECT  20.477 78.624 21.557 78.648 ;
     RECT  21.193 11.664 21.589 11.688 ;
     RECT  20.657 22.848 21.589 25.224 ;
     RECT  21.553 26.4 21.589 27.336 ;
     RECT  21.553 40.848 21.589 42.552 ;
     RECT  21.193 8.976 21.593 10.152 ;
     RECT  21.449 13.296 21.593 13.992 ;
     RECT  20.801 34.224 21.593 34.248 ;
     RECT  20.909 57.84 21.593 58.68 ;
     RECT  20.621 52.56 21.625 52.92 ;
     RECT  21.481 18.24 21.629 21.864 ;
     RECT  21.589 22.848 21.665 27.336 ;
     RECT  21.233 5.76 21.697 6.696 ;
     RECT  21.197 44.4 21.697 45.144 ;
     RECT  21.449 46.32 21.697 46.728 ;
     RECT  21.155 66.72 21.701 66.744 ;
     RECT  20.869 71.184 21.701 71.208 ;
     RECT  21.665 22.848 21.737 25.56 ;
     RECT  21.593 8.976 21.773 9 ;
     RECT  21.737 22.848 21.773 23.4 ;
     RECT  21.593 10.128 21.788 10.152 ;
     RECT  21.733 62.016 21.805 62.04 ;
     RECT  21.233 2.928 21.841 4.68 ;
     RECT  21.409 74.352 21.845 74.376 ;
     RECT  21.629 18.24 21.881 20.184 ;
     RECT  21.737 24.912 21.881 25.56 ;
     RECT  21.593 57.84 21.949 57.864 ;
     RECT  21.269 81.744 21.949 82.968 ;
     RECT  21.665 26.688 21.98 27.336 ;
     RECT  21.589 11.472 22.028 11.688 ;
     RECT  22.028 11.28 22.057 11.688 ;
     RECT  21.805 62.016 22.057 62.568 ;
     RECT  22.021 74.448 22.057 74.472 ;
     RECT  21.98 26.688 22.067 27.576 ;
     RECT  21.788 10.128 22.097 10.296 ;
     RECT  22.067 26.688 22.097 27.336 ;
     RECT  22.057 11.28 22.115 12.552 ;
     RECT  21.485 55.728 22.129 55.896 ;
     RECT  22.057 74.448 22.169 74.664 ;
     RECT  21.841 2.592 22.205 4.68 ;
     RECT  22.169 74.448 22.205 74.568 ;
     RECT  21.625 29.568 22.213 30.216 ;
     RECT  21.341 31.68 22.213 32.808 ;
     RECT  21.233 84.768 22.273 89.736 ;
     RECT  21.625 52.512 22.313 52.92 ;
     RECT  21.161 65.472 22.357 65.592 ;
     RECT  22.129 55.728 22.381 56.472 ;
     RECT  21.985 80.352 22.385 80.376 ;
     RECT  21.589 40.32 22.421 42.552 ;
     RECT  21.557 49.584 22.421 50.184 ;
     RECT  22.357 64.896 22.444 66.264 ;
     RECT  21.593 13.68 22.453 13.992 ;
     RECT  21.913 68.976 22.457 69 ;
     RECT  22.205 74.448 22.457 74.472 ;
     RECT  21.697 17.136 22.501 17.16 ;
     RECT  21.881 18.24 22.501 19.128 ;
     RECT  22.46 16.128 22.547 16.152 ;
     RECT  22.525 54.576 22.561 54.6 ;
     RECT  22.057 62.016 22.561 62.808 ;
     RECT  22.501 17.136 22.565 19.128 ;
     RECT  22.421 42.528 22.597 42.552 ;
     RECT  22.565 17.136 22.601 18.264 ;
     RECT  22.273 84.768 22.601 89.88 ;
     RECT  21.197 38.016 22.633 39.096 ;
     RECT  22.115 11.664 22.637 12.552 ;
     RECT  22.165 67.248 22.637 67.272 ;
     RECT  21.697 78.096 22.652 78.12 ;
     RECT  22.097 10.128 22.669 10.152 ;
     RECT  21.881 25.44 22.669 25.56 ;
     RECT  22.561 61.92 22.669 62.808 ;
     RECT  21.697 44.4 22.673 46.728 ;
     RECT  22.652 77.232 22.693 78.12 ;
     RECT  21.949 81.744 22.7 83.256 ;
     RECT  22.453 13.68 22.705 14.856 ;
     RECT  22.597 42.528 22.705 43.32 ;
     RECT  22.673 44.4 22.705 44.472 ;
     RECT  22.561 53.856 22.705 54.6 ;
     RECT  22.669 61.872 22.705 62.808 ;
     RECT  22.693 76.368 22.739 78.12 ;
     RECT  22.559 51.216 22.741 51.24 ;
     RECT  22.313 52.512 22.741 52.536 ;
     RECT  22.7 81.456 22.741 83.256 ;
     RECT  22.421 50.016 22.745 50.184 ;
     RECT  22.213 29.568 22.769 32.808 ;
     RECT  22.165 33.792 22.769 34.104 ;
     RECT  22.633 38.016 22.777 39.336 ;
     RECT  22.705 61.776 22.781 62.808 ;
     RECT  22.741 51.216 22.787 52.536 ;
     RECT  22.741 80.64 22.787 83.256 ;
     RECT  22.769 29.568 22.817 34.104 ;
     RECT  22.781 61.776 22.817 62.568 ;
     RECT  22.777 37.584 22.837 39.336 ;
     RECT  22.421 40.32 22.837 41.496 ;
     RECT  22.637 12.528 22.849 12.552 ;
     RECT  22.705 13.68 22.849 16.008 ;
     RECT  22.489 58.896 22.892 58.92 ;
     RECT  22.673 45.552 22.921 46.728 ;
     RECT  22.837 37.584 22.924 41.496 ;
     RECT  21.697 5.76 22.933 7.368 ;
     RECT  21.829 8.832 22.933 8.856 ;
     RECT  21.445 47.808 22.961 48.264 ;
     RECT  22.892 58.896 22.961 59.784 ;
     RECT  22.817 61.872 22.961 62.568 ;
     RECT  22.933 5.76 22.979 8.856 ;
     RECT  22.961 59.232 22.979 59.784 ;
     RECT  21.949 35.424 22.981 35.448 ;
     RECT  21.881 20.16 22.988 20.184 ;
     RECT  22.669 25.44 22.993 25.608 ;
     RECT  22.979 5.76 23.02 7.944 ;
     RECT  22.988 19.92 23.029 20.184 ;
     RECT  21.629 21.264 23.029 21.864 ;
     RECT  22.961 61.92 23.033 62.568 ;
     RECT  22.993 25.152 23.065 25.608 ;
     RECT  22.453 28.512 23.065 28.536 ;
     RECT  23.065 25.104 23.173 25.608 ;
     RECT  22.097 26.688 23.173 26.712 ;
     RECT  23.065 28.512 23.317 29.112 ;
     RECT  22.961 48.144 23.317 48.264 ;
     RECT  22.205 4.368 23.353 4.68 ;
     RECT  22.669 10.032 23.461 10.152 ;
     RECT  22.705 53.856 23.461 54.648 ;
     RECT  22.381 55.728 23.461 56.568 ;
     RECT  21.197 63.792 23.497 63.816 ;
     RECT  22.444 64.896 23.497 65.736 ;
     RECT  23.461 53.856 23.605 56.568 ;
     RECT  21.949 57.6 23.605 57.864 ;
     RECT  22.205 2.592 23.641 2.616 ;
     RECT  23.353 3.936 23.641 4.68 ;
     RECT  22.739 77.472 23.701 77.496 ;
     RECT  23.461 9.072 23.708 10.152 ;
     RECT  22.705 42.528 23.713 44.472 ;
     RECT  22.601 84.864 23.713 89.88 ;
     RECT  23.708 9.072 23.749 10.872 ;
     RECT  22.849 12.528 23.749 16.008 ;
     RECT  21.773 23.376 23.749 23.4 ;
     RECT  22.787 81.936 23.749 83.256 ;
     RECT  23.497 63.792 24.001 65.736 ;
     RECT  23.641 2.592 24.008 4.68 ;
     RECT  23.02 5.76 24.008 7.464 ;
     RECT  23.749 9.072 24.008 16.008 ;
     RECT  22.601 17.136 24.008 17.16 ;
     RECT  22.601 18.24 24.008 18.264 ;
     RECT  23.029 19.92 24.008 21.864 ;
     RECT  23.749 23.376 24.008 23.928 ;
     RECT  23.173 25.104 24.008 26.712 ;
     RECT  23.317 28.416 24.008 29.112 ;
     RECT  22.817 30.624 24.008 34.104 ;
     RECT  22.981 35.424 24.008 36.024 ;
     RECT  22.924 37.584 24.008 39.336 ;
     RECT  22.924 40.32 24.008 41.496 ;
     RECT  23.713 42.48 24.008 44.472 ;
     RECT  22.921 45.552 24.008 46.776 ;
     RECT  23.317 48.144 24.008 48.792 ;
     RECT  22.745 50.016 24.008 50.04 ;
     RECT  22.787 51.888 24.008 51.912 ;
     RECT  23.605 53.856 24.008 57.864 ;
     RECT  22.979 59.232 24.008 59.256 ;
     RECT  22.933 60.816 24.008 60.84 ;
     RECT  23.033 62.016 24.008 62.568 ;
     RECT  24.001 63.792 24.008 66.504 ;
     RECT  23.893 69.456 24.008 69.48 ;
     RECT  23.701 72.144 24.008 72.168 ;
     RECT  23.66 73.2 24.008 73.224 ;
     RECT  22.739 76.368 24.008 76.392 ;
     RECT  23.701 77.376 24.008 77.496 ;
     RECT  22.787 80.64 24.008 80.664 ;
     RECT  23.749 81.888 24.008 83.256 ;
     RECT  23.713 84.864 24.008 90.024 ;
     RECT  24.008 2.148 24.112 90.732 ;
     RECT  24.112 2.418 24.304 90.462 ;
     RECT  24.304 3.936 24.419 4.68 ;
     RECT  24.304 60.336 24.419 67.512 ;
     RECT  24.304 11.76 24.445 13.08 ;
     RECT  24.304 40.704 24.46 43.32 ;
     RECT  24.419 67.008 24.46 67.512 ;
     RECT  24.419 60.336 24.467 66.024 ;
     RECT  24.304 2.592 24.473 2.76 ;
     RECT  24.304 28.416 24.473 28.536 ;
     RECT  24.46 42.48 24.473 43.32 ;
     RECT  24.304 55.728 24.473 59.256 ;
     RECT  24.467 60.336 24.508 65.736 ;
     RECT  24.304 29.616 24.509 36.024 ;
     RECT  24.509 29.616 24.515 30.84 ;
     RECT  24.509 32.208 24.617 36.024 ;
     RECT  24.304 38.16 24.617 39.336 ;
     RECT  24.445 12.768 24.653 13.08 ;
     RECT  24.304 18.384 24.689 19.272 ;
     RECT  24.46 40.704 24.725 41.448 ;
     RECT  24.515 29.616 24.797 30.792 ;
     RECT  24.617 32.208 24.803 34.872 ;
     RECT  24.419 3.936 24.905 4.488 ;
     RECT  24.653 12.816 24.905 13.08 ;
     RECT  24.508 62.016 24.977 65.736 ;
     RECT  24.304 20.544 25.046 23.88 ;
     RECT  24.304 44.4 25.049 48.792 ;
     RECT  24.304 50.016 25.091 51.816 ;
     RECT  24.304 14.352 25.121 15.048 ;
     RECT  25.091 50.016 25.121 50.088 ;
     RECT  25.121 14.352 25.139 14.376 ;
     RECT  24.905 13.056 25.229 13.08 ;
     RECT  24.473 28.416 25.229 28.488 ;
     RECT  24.473 2.736 25.297 2.76 ;
     RECT  24.304 25.44 25.297 26.664 ;
     RECT  25.091 51.792 25.297 51.816 ;
     RECT  24.304 52.896 25.297 54.696 ;
     RECT  25.046 20.544 25.301 23.832 ;
     RECT  24.304 9.216 25.333 9.624 ;
     RECT  24.617 36 25.333 36.024 ;
     RECT  25.049 44.88 25.337 48.792 ;
     RECT  24.304 5.856 25.373 7.896 ;
     RECT  24.473 55.728 25.373 55.992 ;
     RECT  24.977 62.016 25.373 65.592 ;
     RECT  25.333 36 25.405 36.84 ;
     RECT  24.725 40.848 25.477 41.448 ;
     RECT  24.473 42.48 25.477 42.792 ;
     RECT  25.337 48.144 25.477 48.792 ;
     RECT  25.297 25.44 25.481 27.336 ;
     RECT  24.803 32.208 25.481 34.104 ;
     RECT  24.304 81.84 25.513 82.968 ;
     RECT  24.617 38.64 25.523 39.336 ;
     RECT  24.905 3.936 25.553 4.44 ;
     RECT  25.337 44.88 25.553 46.728 ;
     RECT  25.297 51.792 25.585 54.696 ;
     RECT  25.373 55.728 25.585 55.752 ;
     RECT  25.523 38.688 25.589 38.712 ;
     RECT  25.373 6.144 25.621 7.896 ;
     RECT  24.473 57.024 25.621 59.256 ;
     RECT  25.549 80.256 25.621 80.28 ;
     RECT  24.304 76.512 25.625 77.4 ;
     RECT  25.621 6.144 25.649 7.992 ;
     RECT  25.333 9.216 25.649 9.816 ;
     RECT  25.297 2.736 25.661 2.904 ;
     RECT  25.301 20.544 25.667 22.824 ;
     RECT  24.304 74.304 25.669 74.856 ;
     RECT  25.585 51.792 25.715 55.752 ;
     RECT  24.304 16.656 25.729 16.68 ;
     RECT  25.649 6.144 25.733 9.816 ;
     RECT  25.669 74.304 25.733 75.048 ;
     RECT  24.508 60.336 25.765 60.984 ;
     RECT  25.667 22.8 25.769 22.824 ;
     RECT  25.477 40.848 25.769 42.792 ;
     RECT  25.621 56.832 25.801 59.256 ;
     RECT  25.553 3.936 25.805 4.392 ;
     RECT  25.405 36 25.805 37.608 ;
     RECT  25.729 16.656 25.837 16.776 ;
     RECT  24.445 11.76 25.868 11.784 ;
     RECT  25.733 8.544 25.877 9.816 ;
     RECT  25.801 56.832 25.877 59.352 ;
     RECT  25.868 11.376 25.909 11.784 ;
     RECT  24.797 29.616 25.945 30.408 ;
     RECT  25.513 81.648 25.949 82.968 ;
     RECT  24.304 69.456 25.985 69.48 ;
     RECT  25.481 32.208 26.053 33.864 ;
     RECT  25.949 82.944 26.053 82.968 ;
     RECT  24.304 84.864 26.053 85.464 ;
     RECT  24.304 86.688 26.053 90.072 ;
     RECT  25.121 50.016 26.089 50.04 ;
     RECT  25.715 51.792 26.089 51.816 ;
     RECT  25.301 23.808 26.093 23.832 ;
     RECT  26.053 82.944 26.14 90.072 ;
     RECT  25.765 60.336 26.195 61.08 ;
     RECT  25.837 16.656 26.197 17.208 ;
     RECT  24.689 18.384 26.197 18.408 ;
     RECT  25.945 29.472 26.197 30.408 ;
     RECT  26.053 31.536 26.197 33.864 ;
     RECT  25.667 20.544 26.201 21.096 ;
     RECT  25.661 2.88 26.233 2.904 ;
     RECT  25.373 62.16 26.233 65.592 ;
     RECT  24.46 67.008 26.233 67.032 ;
     RECT  26.197 16.656 26.243 18.408 ;
     RECT  26.017 19.44 26.243 19.464 ;
     RECT  26.201 20.544 26.243 20.616 ;
     RECT  25.715 52.896 26.273 55.752 ;
     RECT  26.243 16.656 26.305 18.216 ;
     RECT  25.477 48.144 26.309 48.936 ;
     RECT  26.089 50.016 26.309 51.816 ;
     RECT  25.877 57.84 26.309 59.352 ;
     RECT  26.233 62.16 26.309 67.032 ;
     RECT  25.481 27.312 26.341 27.336 ;
     RECT  25.229 28.416 26.341 28.44 ;
     RECT  26.273 53.136 26.341 55.752 ;
     RECT  25.877 56.832 26.341 56.856 ;
     RECT  26.341 27.312 26.381 28.44 ;
     RECT  26.197 29.472 26.381 33.864 ;
     RECT  26.341 53.136 26.381 56.856 ;
     RECT  25.625 76.896 26.381 77.4 ;
     RECT  26.3 14.784 26.444 14.808 ;
     RECT  26.305 16.608 26.444 18.216 ;
     RECT  25.553 44.88 26.444 46.296 ;
     RECT  25.481 25.44 26.449 26.28 ;
     RECT  26.233 2.88 26.453 3.144 ;
     RECT  26.381 29.472 26.453 33.048 ;
     RECT  26.195 60.336 26.453 60.36 ;
     RECT  26.309 62.16 26.453 63.144 ;
     RECT  26.309 64.128 26.485 67.032 ;
     RECT  26.444 44.064 26.521 46.296 ;
     RECT  26.485 64.128 26.521 67.368 ;
     RECT  26.444 14.784 26.531 18.216 ;
     RECT  26.521 44.064 26.531 46.968 ;
     RECT  25.909 11.376 26.581 12.264 ;
     RECT  26.453 62.16 26.597 63.096 ;
     RECT  26.581 10.752 26.627 12.264 ;
     RECT  25.805 36.816 26.633 37.608 ;
     RECT  26.521 64.128 26.633 67.704 ;
     RECT  25.621 79.92 26.665 80.28 ;
     RECT  25.949 81.648 26.665 81.864 ;
     RECT  26.531 14.784 26.668 15.336 ;
     RECT  26.14 82.944 26.669 85.368 ;
     RECT  26.633 36.816 26.705 36.84 ;
     RECT  26.531 44.88 26.705 46.968 ;
     RECT  26.14 86.544 26.723 90.072 ;
     RECT  26.597 62.16 26.737 63 ;
     RECT  26.381 76.944 26.737 77.4 ;
     RECT  26.629 38.736 26.741 38.76 ;
     RECT  25.769 40.896 26.773 42.792 ;
     RECT  26.485 70.56 26.773 70.584 ;
     RECT  24.304 71.712 26.773 72.168 ;
     RECT  26.705 44.88 26.785 46.296 ;
     RECT  26.381 53.136 26.813 55.992 ;
     RECT  26.665 79.92 26.813 81.864 ;
     RECT  26.669 84.432 26.849 85.368 ;
     RECT  25.805 4.128 26.881 4.392 ;
     RECT  26.303 13.344 26.881 13.368 ;
     RECT  25.981 35.328 26.917 35.352 ;
     RECT  25.877 8.544 26.921 9.624 ;
     RECT  26.737 76.944 26.921 77.496 ;
     RECT  26.845 24 26.953 24.024 ;
     RECT  26.449 25.44 26.953 26.328 ;
     RECT  26.668 14.784 26.957 14.808 ;
     RECT  26.531 16.608 26.993 18.216 ;
     RECT  26.453 29.472 26.993 31.416 ;
     RECT  26.813 80.88 26.993 81.864 ;
     RECT  26.953 24 27.025 26.328 ;
     RECT  26.881 4.128 27.029 4.632 ;
     RECT  26.737 61.968 27.029 63 ;
     RECT  26.723 86.592 27.101 90.072 ;
     RECT  25.873 39.84 27.109 39.864 ;
     RECT  26.773 40.896 27.109 43.368 ;
     RECT  26.785 44.88 27.137 45.24 ;
     RECT  26.813 53.136 27.137 54.696 ;
     RECT  26.309 57.84 27.169 59.112 ;
     RECT  26.627 10.752 27.173 11.208 ;
     RECT  26.993 16.608 27.181 17.64 ;
     RECT  26.773 70.56 27.209 72.168 ;
     RECT  26.381 27.888 27.245 28.44 ;
     RECT  25.733 6.144 27.249 7.464 ;
     RECT  26.921 8.544 27.249 9 ;
     RECT  27.109 39.84 27.313 43.368 ;
     RECT  26.309 50.016 27.313 51.096 ;
     RECT  25.733 75.024 27.317 75.048 ;
     RECT  27.249 6.144 27.347 9 ;
     RECT  26.633 67.344 27.349 67.704 ;
     RECT  27.241 69.504 27.349 69.528 ;
     RECT  27.209 70.56 27.353 71.784 ;
     RECT  26.993 81.696 27.385 81.864 ;
     RECT  26.669 82.944 27.385 82.968 ;
     RECT  27.101 86.832 27.385 90.072 ;
     RECT  27.349 67.344 27.395 69.528 ;
     RECT  27.347 6.144 27.421 6.552 ;
     RECT  26.993 29.616 27.425 31.416 ;
     RECT  27.353 70.56 27.425 71.736 ;
     RECT  26.921 77.472 27.457 77.496 ;
     RECT  26.773 78.624 27.457 78.648 ;
     RECT  27.313 39.36 27.461 43.368 ;
     RECT  27.313 50.016 27.529 51.864 ;
     RECT  27.025 24 27.601 26.616 ;
     RECT  27.425 70.56 27.601 71.64 ;
     RECT  26.453 2.88 27.637 3.048 ;
     RECT  26.627 12.24 27.637 12.264 ;
     RECT  26.881 13.344 27.637 13.704 ;
     RECT  26.453 32.976 27.641 33.048 ;
     RECT  26.243 20.592 27.673 20.616 ;
     RECT  27.596 21.648 27.673 21.672 ;
     RECT  27.637 12.24 27.683 13.704 ;
     RECT  27.673 20.592 27.683 21.672 ;
     RECT  26.785 46.224 27.709 46.296 ;
     RECT  26.309 48.144 27.709 48.312 ;
     RECT  27.601 70.464 27.713 71.64 ;
     RECT  27.601 34.32 27.74 34.344 ;
     RECT  26.917 35.328 27.74 35.448 ;
     RECT  27.457 77.472 27.749 78.648 ;
     RECT  27.347 8.976 27.821 9 ;
     RECT  27.74 34.32 27.827 35.448 ;
     RECT  27.637 2.832 27.853 3.048 ;
     RECT  27.173 10.8 27.853 11.208 ;
     RECT  27.683 12.24 27.853 13.656 ;
     RECT  27.029 62.976 27.864 63 ;
     RECT  26.633 64.128 27.864 66.168 ;
     RECT  27.181 16.608 27.889 17.208 ;
     RECT  27.395 67.344 27.893 68.856 ;
     RECT  27.313 22.8 27.925 22.824 ;
     RECT  27.864 62.976 27.925 66.168 ;
     RECT  27.893 67.344 27.925 68.136 ;
     RECT  27.781 79.68 27.925 79.704 ;
     RECT  27.709 46.224 27.961 48.312 ;
     RECT  27.529 49.536 27.961 51.864 ;
     RECT  27.137 53.568 27.961 54.696 ;
     RECT  27.925 78.864 27.971 79.704 ;
     RECT  27.029 61.968 28.001 61.992 ;
     RECT  27.385 81.696 28.021 82.968 ;
     RECT  27.425 29.616 28.037 30.888 ;
     RECT  27.925 62.976 28.037 68.136 ;
     RECT  28.021 81.696 28.067 83.496 ;
     RECT  27.889 16.512 28.069 17.208 ;
     RECT  27.461 39.36 28.069 39.912 ;
     RECT  27.961 53.568 28.069 54.744 ;
     RECT  26.813 55.824 28.069 55.992 ;
     RECT  28.037 30.576 28.073 30.888 ;
     RECT  27.461 40.896 28.105 43.368 ;
     RECT  27.925 22.512 28.145 22.824 ;
     RECT  27.961 46.224 28.145 51.864 ;
     RECT  26.849 84.816 28.145 85.368 ;
     RECT  27.853 2.832 28.172 3.288 ;
     RECT  27.029 4.368 28.172 4.632 ;
     RECT  28.069 53.568 28.177 55.992 ;
     RECT  27.169 57.024 28.177 59.112 ;
     RECT  28.105 40.896 28.181 43.56 ;
     RECT  28.172 2.832 28.213 4.632 ;
     RECT  28.181 42.048 28.213 43.56 ;
     RECT  28.067 82.944 28.213 83.496 ;
     RECT  28.145 22.512 28.217 22.536 ;
     RECT  28.145 51.744 28.217 51.864 ;
     RECT  27.347 7.632 28.253 7.848 ;
     RECT  28.037 62.976 28.253 65.592 ;
     RECT  28.213 2.256 28.259 4.632 ;
     RECT  27.713 70.608 28.289 71.64 ;
     RECT  27.421 5.712 28.3 6.552 ;
     RECT  28.067 81.696 28.317 81.72 ;
     RECT  28.145 46.224 28.325 50.76 ;
     RECT  28.069 39.264 28.357 39.912 ;
     RECT  27.385 74.688 28.361 74.712 ;
     RECT  28.073 30.624 28.393 30.888 ;
     RECT  28.357 38.688 28.405 39.912 ;
     RECT  27.641 32.976 28.429 33 ;
     RECT  28.069 15.984 28.465 17.208 ;
     RECT  27.137 44.88 28.465 45 ;
     RECT  27.781 36.48 28.573 36.504 ;
     RECT  28.465 15.984 28.609 17.4 ;
     RECT  27.385 86.832 28.753 90.504 ;
     RECT  28.573 36.288 28.789 36.504 ;
     RECT  28.069 14.64 28.825 14.664 ;
     RECT  28.609 15.984 28.825 18.024 ;
     RECT  27.683 20.592 28.825 21 ;
     RECT  27.817 60.144 28.825 60.168 ;
     RECT  28.145 85.296 28.825 85.368 ;
     RECT  27.601 24 28.861 26.76 ;
     RECT  28.393 30.624 28.861 31.272 ;
     RECT  28.429 32.736 28.897 33 ;
     RECT  27.827 34.32 28.897 34.824 ;
     RECT  28.405 39.888 28.897 39.912 ;
     RECT  28.181 40.896 28.897 40.92 ;
     RECT  28.825 60.144 28.933 60.84 ;
     RECT  27.109 19.2 28.969 19.224 ;
     RECT  28.825 20.592 28.988 21.528 ;
     RECT  27.971 78.864 29.005 78.888 ;
     RECT  28.753 80.256 29.005 80.28 ;
     RECT  27.749 77.472 29.029 77.496 ;
     RECT  28.753 86.784 29.029 90.504 ;
     RECT  28.3 6.528 29.041 6.552 ;
     RECT  28.253 7.632 29.041 7.656 ;
     RECT  28.289 70.608 29.041 70.92 ;
     RECT  28.861 24 29.077 27.192 ;
     RECT  27.245 28.416 29.077 28.44 ;
     RECT  28.177 53.568 29.077 59.112 ;
     RECT  28.253 64.56 29.077 65.592 ;
     RECT  28.037 66.864 29.077 66.888 ;
     RECT  28.897 32.736 29.113 34.824 ;
     RECT  28.789 35.856 29.113 37.08 ;
     RECT  29.077 53.04 29.113 59.112 ;
     RECT  28.253 62.976 29.141 63.096 ;
     RECT  29.141 62.688 29.173 63.096 ;
     RECT  28.217 51.744 29.18 51.768 ;
     RECT  29.113 52.8 29.18 59.112 ;
     RECT  28.933 60.144 29.18 60.888 ;
     RECT  27.853 10.8 29.221 13.656 ;
     RECT  28.825 14.64 29.221 18.168 ;
     RECT  28.969 19.2 29.221 19.32 ;
     RECT  29.113 32.736 29.221 37.08 ;
     RECT  29.041 70.368 29.269 70.92 ;
     RECT  28.213 42.048 29.293 43.656 ;
     RECT  28.325 46.272 29.401 50.76 ;
     RECT  29.18 51.744 29.401 60.888 ;
     RECT  28.259 2.256 29.408 4.392 ;
     RECT  29.041 6.528 29.408 7.656 ;
     RECT  28.897 8.976 29.408 9 ;
     RECT  29.221 10.8 29.408 19.32 ;
     RECT  28.988 20.592 29.408 22.488 ;
     RECT  29.077 24 29.408 28.44 ;
     RECT  28.861 30.624 29.408 31.464 ;
     RECT  29.221 32.64 29.408 37.08 ;
     RECT  28.405 38.688 29.408 38.712 ;
     RECT  28.897 39.888 29.408 40.92 ;
     RECT  29.293 41.952 29.408 43.656 ;
     RECT  28.465 44.784 29.408 45 ;
     RECT  29.401 46.272 29.408 60.888 ;
     RECT  29.173 62.496 29.408 63.096 ;
     RECT  29.077 64.56 29.408 66.888 ;
     RECT  28.037 67.92 29.408 68.136 ;
     RECT  29.269 69.456 29.408 70.92 ;
     RECT  29.029 77.472 29.408 77.88 ;
     RECT  29.005 78.864 29.408 80.28 ;
     RECT  28.933 81.456 29.408 81.48 ;
     RECT  28.213 82.944 29.408 83.64 ;
     RECT  28.825 85.296 29.408 85.464 ;
     RECT  29.029 86.544 29.408 90.504 ;
     RECT  29.408 2.148 29.512 90.732 ;
     RECT  29.512 2.418 29.704 90.504 ;
     RECT  29.704 14.928 29.765 31.944 ;
     RECT  29.704 38.592 29.765 46.824 ;
     RECT  29.704 8.976 29.801 9.336 ;
     RECT  29.765 43.968 29.801 46.824 ;
     RECT  29.801 9.072 29.837 9.336 ;
     RECT  29.704 79.44 29.837 80.856 ;
     RECT  29.704 2.544 29.843 7.944 ;
     RECT  29.704 36.288 29.873 37.512 ;
     RECT  29.704 47.904 29.873 48.312 ;
     RECT  29.801 43.968 29.909 46.536 ;
     RECT  29.704 53.136 29.909 59.736 ;
     RECT  29.704 82.944 29.909 83.64 ;
     RECT  29.765 38.592 29.945 42.84 ;
     RECT  29.909 43.968 29.945 45.624 ;
     RECT  29.945 38.592 30.017 39.768 ;
     RECT  29.704 50.16 30.017 51.768 ;
     RECT  29.704 66.144 30.017 70.68 ;
     RECT  29.765 17.472 30.089 31.944 ;
     RECT  29.704 33.552 30.089 33.912 ;
     RECT  29.704 65.136 30.125 65.16 ;
     RECT  29.704 76.992 30.197 77.88 ;
     RECT  29.843 7.344 30.22 7.944 ;
     RECT  30.017 38.688 30.227 39.768 ;
     RECT  30.089 17.472 30.233 24.264 ;
     RECT  29.909 54.72 30.233 59.736 ;
     RECT  30.197 76.992 30.241 77.544 ;
     RECT  29.843 2.544 30.305 6.072 ;
     RECT  30.233 54.864 30.305 59.736 ;
     RECT  29.945 40.8 30.323 42.84 ;
     RECT  30.305 2.544 30.341 5.208 ;
     RECT  30.227 39.456 30.369 39.768 ;
     RECT  29.909 83.184 30.413 83.64 ;
     RECT  29.704 86.448 30.413 90.504 ;
     RECT  29.704 13.632 30.449 13.704 ;
     RECT  30.341 2.544 30.467 4.104 ;
     RECT  30.341 5.184 30.467 5.208 ;
     RECT  30.233 18.816 30.467 24.264 ;
     RECT  30.467 19.104 30.508 24.264 ;
     RECT  30.413 86.448 30.521 90.072 ;
     RECT  30.089 25.344 30.557 31.944 ;
     RECT  29.765 14.928 30.629 16.056 ;
     RECT  30.508 20.352 30.629 24.264 ;
     RECT  29.837 80.832 30.629 80.856 ;
     RECT  30.449 13.632 30.665 13.656 ;
     RECT  30.305 56.736 30.697 59.736 ;
     RECT  29.704 60.816 30.697 60.888 ;
     RECT  30.233 17.472 30.733 17.544 ;
     RECT  30.017 50.16 30.733 50.568 ;
     RECT  30.697 56.736 30.737 60.888 ;
     RECT  30.017 70.608 30.757 70.68 ;
     RECT  29.704 72.144 30.757 72.888 ;
     RECT  30.017 66.144 30.769 69.48 ;
     RECT  29.837 79.44 30.773 79.848 ;
     RECT  30.305 54.864 30.803 55.704 ;
     RECT  30.737 56.736 30.803 60.264 ;
     RECT  29.909 53.136 30.805 53.592 ;
     RECT  30.557 25.632 30.809 31.944 ;
     RECT  30.769 65.328 30.809 69.48 ;
     RECT  30.22 7.344 30.845 7.656 ;
     RECT  30.629 20.688 30.845 24.264 ;
     RECT  30.809 65.328 30.853 66.648 ;
     RECT  30.757 70.608 30.853 72.888 ;
     RECT  29.837 9.072 30.877 9.096 ;
     RECT  30.773 79.44 30.881 79.8 ;
     RECT  30.467 2.544 30.953 3.912 ;
     RECT  30.877 9.072 30.989 9.24 ;
     RECT  30.803 57.648 30.989 60.264 ;
     RECT  29.704 10.992 31.021 12.072 ;
     RECT  30.953 2.544 31.061 3.672 ;
     RECT  29.945 43.968 31.061 45.144 ;
     RECT  29.873 48.288 31.061 48.312 ;
     RECT  30.733 49.584 31.061 50.568 ;
     RECT  30.413 83.184 31.061 83.208 ;
     RECT  30.629 14.928 31.093 15.432 ;
     RECT  30.089 33.6 31.093 33.912 ;
     RECT  30.881 79.632 31.097 79.8 ;
     RECT  30.241 76.992 31.1 77.016 ;
     RECT  30.989 9.072 31.139 9.096 ;
     RECT  31.021 10.176 31.139 12.552 ;
     RECT  31.139 10.848 31.141 12.552 ;
     RECT  30.845 20.688 31.169 24.072 ;
     RECT  30.989 57.648 31.169 58.152 ;
     RECT  30.853 65.76 31.169 66.648 ;
     RECT  31.097 79.68 31.169 79.8 ;
     RECT  29.704 74.064 31.187 74.088 ;
     RECT  30.323 41.424 31.201 42.84 ;
     RECT  31.169 79.68 31.205 79.752 ;
     RECT  30.809 69.216 31.237 69.48 ;
     RECT  30.853 70.608 31.237 71.304 ;
     RECT  29.873 36.336 31.244 37.512 ;
     RECT  30.845 7.44 31.273 7.656 ;
     RECT  30.733 16.848 31.277 17.544 ;
     RECT  31.244 35.568 31.285 37.512 ;
     RECT  30.369 39.744 31.309 39.768 ;
     RECT  31.201 41.424 31.309 43.128 ;
     RECT  30.803 55.2 31.309 55.704 ;
     RECT  31.285 35.568 31.331 37.56 ;
     RECT  29.704 61.968 31.349 63.096 ;
     RECT  31.237 69.216 31.349 71.304 ;
     RECT  31.331 36.336 31.372 37.56 ;
     RECT  31.309 39.744 31.385 43.128 ;
     RECT  30.805 52.944 31.385 53.592 ;
     RECT  31.1 76.464 31.453 77.016 ;
     RECT  31.205 79.728 31.493 79.752 ;
     RECT  30.017 51.552 31.565 51.768 ;
     RECT  31.141 11.664 31.597 12.552 ;
     RECT  30.877 13.584 31.597 13.608 ;
     RECT  31.061 44.352 31.597 45.144 ;
     RECT  31.525 46.176 31.597 46.2 ;
     RECT  31.309 5.76 31.601 5.784 ;
     RECT  31.385 52.992 31.633 53.592 ;
     RECT  30.809 25.632 31.709 28.68 ;
     RECT  31.489 17.76 31.741 17.784 ;
     RECT  30.508 19.104 31.741 19.32 ;
     RECT  31.709 25.632 31.745 27.672 ;
     RECT  31.093 33.024 31.777 33.912 ;
     RECT  30.809 67.824 31.777 68.184 ;
     RECT  31.349 69.216 31.777 70.728 ;
     RECT  31.169 58.128 31.817 58.152 ;
     RECT  31.349 62.112 31.817 63.096 ;
     RECT  31.597 11.664 31.82 13.608 ;
     RECT  31.093 14.832 31.82 15.432 ;
     RECT  31.309 55.2 31.82 56.232 ;
     RECT  31.633 38.544 31.885 38.568 ;
     RECT  31.385 39.744 31.885 40.728 ;
     RECT  31.633 52.992 31.885 53.832 ;
     RECT  31.82 55.056 31.885 56.232 ;
     RECT  31.709 28.656 31.909 28.68 ;
     RECT  30.809 29.76 31.909 31.944 ;
     RECT  30.697 64.32 31.925 64.344 ;
     RECT  30.853 72.864 31.925 72.888 ;
     RECT  31.061 50.016 31.957 50.568 ;
     RECT  31.565 51.552 31.957 51.576 ;
     RECT  31.345 74.112 31.957 74.472 ;
     RECT  31.453 75.792 31.957 77.016 ;
     RECT  31.909 28.656 31.961 31.944 ;
     RECT  31.777 67.824 31.961 70.728 ;
     RECT  31.273 7.44 31.993 8.184 ;
     RECT  31.957 50.016 31.997 51.576 ;
     RECT  31.169 20.688 32.033 23.064 ;
     RECT  31.957 74.112 32.099 77.016 ;
     RECT  31.82 11.664 32.105 15.432 ;
     RECT  31.777 33.024 32.129 34.536 ;
     RECT  31.169 24.048 32.137 24.072 ;
     RECT  31.745 25.632 32.137 26.184 ;
     RECT  31.961 68.976 32.141 70.728 ;
     RECT  32.099 75.792 32.147 77.016 ;
     RECT  31.961 28.8 32.173 31.944 ;
     RECT  32.129 33.024 32.173 34.824 ;
     RECT  32.173 28.8 32.177 34.824 ;
     RECT  30.989 59.184 32.177 60.264 ;
     RECT  32.141 70.08 32.177 70.728 ;
     RECT  31.628 48.912 32.209 48.936 ;
     RECT  31.997 50.016 32.209 51.336 ;
     RECT  31.741 80.928 32.209 80.952 ;
     RECT  32.177 29.616 32.213 34.824 ;
     RECT  32.209 80.64 32.249 80.952 ;
     RECT  32.105 11.664 32.252 14.904 ;
     RECT  32.252 11.328 32.281 14.904 ;
     RECT  31.237 47.472 32.281 47.496 ;
     RECT  31.741 17.76 32.317 19.512 ;
     RECT  32.281 10.704 32.339 14.904 ;
     RECT  31.385 42.144 32.353 43.128 ;
     RECT  31.597 44.352 32.353 46.2 ;
     RECT  31.745 27.312 32.393 27.672 ;
     RECT  32.173 5.28 32.417 5.736 ;
     RECT  32.213 29.616 32.429 34.536 ;
     RECT  31.885 38.112 32.465 40.728 ;
     RECT  32.339 11.952 32.483 14.904 ;
     RECT  31.817 62.112 32.492 62.568 ;
     RECT  32.417 4.992 32.501 5.736 ;
     RECT  30.521 86.448 32.501 89.784 ;
     RECT  32.317 17.088 32.533 19.512 ;
     RECT  32.353 42.144 32.533 46.2 ;
     RECT  32.147 76.944 32.537 77.016 ;
     RECT  32.483 13.872 32.573 14.904 ;
     RECT  32.209 48.912 32.573 51.336 ;
     RECT  32.147 75.792 32.573 75.816 ;
     RECT  32.492 61.344 32.579 62.568 ;
     RECT  32.533 41.76 32.605 46.2 ;
     RECT  32.281 47.424 32.605 47.496 ;
     RECT  32.177 60.24 32.609 60.264 ;
     RECT  31.061 2.544 32.641 3.432 ;
     RECT  31.372 36.336 32.641 36.888 ;
     RECT  32.137 24.048 32.645 26.184 ;
     RECT  31.169 65.76 32.677 66.6 ;
     RECT  32.537 76.992 32.677 77.016 ;
     RECT  32.533 16.416 32.681 19.512 ;
     RECT  32.605 41.76 32.681 47.496 ;
     RECT  32.677 76.992 32.717 77.112 ;
     RECT  32.681 17.088 32.771 19.512 ;
     RECT  32.771 18.144 32.812 19.512 ;
     RECT  32.033 22.464 32.821 23.064 ;
     RECT  32.645 24.048 32.821 25.656 ;
     RECT  32.483 11.952 32.825 12.84 ;
     RECT  32.573 48.912 32.825 48.936 ;
     RECT  32.717 77.088 32.828 77.112 ;
     RECT  32.429 30.048 32.861 34.536 ;
     RECT  32.465 38.544 32.861 40.728 ;
     RECT  32.828 77.088 32.869 77.448 ;
     RECT  31.993 7.392 32.893 8.184 ;
     RECT  32.861 38.784 32.897 40.728 ;
     RECT  32.573 50.256 32.897 50.568 ;
     RECT  32.869 77.088 32.915 78.12 ;
     RECT  32.501 86.448 32.933 89.592 ;
     RECT  32.893 7.392 33.037 8.28 ;
     RECT  31.885 52.992 33.037 56.232 ;
     RECT  32.929 48.672 33.041 48.696 ;
     RECT  32.573 14.112 33.073 14.904 ;
     RECT  32.501 5.28 33.077 5.736 ;
     RECT  32.821 22.464 33.113 25.656 ;
     RECT  32.681 41.76 33.113 42.6 ;
     RECT  32.915 78.096 33.113 78.12 ;
     RECT  32.812 19.488 33.145 19.512 ;
     RECT  32.033 20.688 33.145 20.712 ;
     RECT  33.061 73.104 33.148 73.128 ;
     RECT  32.177 59.184 33.149 59.208 ;
     RECT  32.579 61.872 33.149 62.568 ;
     RECT  32.893 81.744 33.149 81.768 ;
     RECT  32.641 36.336 33.181 36.984 ;
     RECT  32.771 17.088 33.185 17.112 ;
     RECT  32.933 86.448 33.205 88.392 ;
     RECT  32.825 11.952 33.257 12.792 ;
     RECT  33.073 14.112 33.26 15 ;
     RECT  32.339 10.704 33.289 10.728 ;
     RECT  33.037 7.392 33.301 8.904 ;
     RECT  33.289 10.368 33.301 10.728 ;
     RECT  32.141 68.976 33.325 69.048 ;
     RECT  32.641 2.544 33.329 4.104 ;
     RECT  32.099 74.112 33.329 74.136 ;
     RECT  33.301 5.808 33.347 8.904 ;
     RECT  33.26 14.112 33.347 15.672 ;
     RECT  33.145 19.488 33.347 20.712 ;
     RECT  33.181 35.952 33.401 36.984 ;
     RECT  32.677 65.76 33.437 66.648 ;
     RECT  33.113 22.464 33.469 24.072 ;
     RECT  32.933 89.52 33.469 89.592 ;
     RECT  33.469 22.368 33.539 24.072 ;
     RECT  31.961 67.824 33.545 67.848 ;
     RECT  32.861 32.448 33.577 34.536 ;
     RECT  33.401 35.952 33.577 36.504 ;
     RECT  32.249 80.64 33.577 80.664 ;
     RECT  33.113 25.152 33.58 25.656 ;
     RECT  32.393 27.36 33.613 27.672 ;
     RECT  33.347 14.112 33.653 15 ;
     RECT  33.577 32.448 33.653 36.504 ;
     RECT  33.325 68.88 33.653 69.528 ;
     RECT  33.037 52.512 33.683 56.232 ;
     RECT  32.681 43.968 33.721 47.496 ;
     RECT  33.683 54.144 33.731 56.232 ;
     RECT  33.301 10.368 33.733 11.16 ;
     RECT  32.812 18.144 33.793 18.168 ;
     RECT  33.347 19.488 33.793 19.896 ;
     RECT  32.605 57.552 33.793 57.576 ;
     RECT  33.733 9.936 33.82 11.16 ;
     RECT  33.113 41.76 33.829 41.784 ;
     RECT  33.149 62.304 33.833 62.568 ;
     RECT  33.613 27.36 33.865 28.296 ;
     RECT  33.793 57.552 33.865 58.488 ;
     RECT  33.865 27.36 33.901 28.536 ;
     RECT  33.829 41.472 33.901 41.784 ;
     RECT  33.257 12.288 34.009 12.792 ;
     RECT  32.897 50.544 34.104 50.568 ;
     RECT  33.58 25.632 34.117 25.656 ;
     RECT  33.865 57.408 34.117 58.488 ;
     RECT  34.117 25.632 34.124 26.28 ;
     RECT  33.901 27.36 34.124 29.064 ;
     RECT  32.915 77.088 34.153 77.112 ;
     RECT  32.897 38.784 34.165 39.816 ;
     RECT  33.901 41.04 34.165 41.784 ;
     RECT  33.653 68.88 34.189 68.904 ;
     RECT  33.347 5.808 34.213 6.984 ;
     RECT  33.205 86.256 34.213 88.392 ;
     RECT  33.469 89.52 34.213 89.976 ;
     RECT  33.731 54.672 34.225 56.232 ;
     RECT  34.117 57.408 34.225 58.776 ;
     RECT  34.153 75.264 34.225 75.816 ;
     RECT  34.153 77.088 34.225 77.88 ;
     RECT  32.177 70.704 34.369 70.728 ;
     RECT  33.596 71.856 34.369 71.88 ;
     RECT  34.213 86.256 34.369 89.976 ;
     RECT  33.437 65.76 34.405 66.168 ;
     RECT  34.124 25.632 34.441 29.064 ;
     RECT  32.861 30.048 34.441 31.272 ;
     RECT  34.369 70.704 34.453 71.88 ;
     RECT  34.405 79.536 34.453 79.56 ;
     RECT  33.721 43.824 34.477 47.496 ;
     RECT  34.117 48.48 34.477 49.032 ;
     RECT  34.369 85.872 34.477 89.976 ;
     RECT  34.104 50.4 34.513 50.568 ;
     RECT  33.793 18.144 34.549 19.896 ;
     RECT  34.225 75.264 34.585 77.88 ;
     RECT  34.453 79.44 34.585 79.56 ;
     RECT  34.213 37.584 34.621 37.608 ;
     RECT  34.165 38.784 34.621 41.784 ;
     RECT  33.347 8.208 34.657 8.904 ;
     RECT  33.469 20.928 34.657 21.144 ;
     RECT  33.539 22.368 34.657 22.488 ;
     RECT  33.683 52.512 34.693 53.016 ;
     RECT  34.225 54.672 34.693 59.592 ;
     RECT  34.693 52.512 34.765 53.208 ;
     RECT  33.539 23.568 34.801 23.592 ;
     RECT  33.329 2.544 34.808 3.576 ;
     RECT  34.213 5.184 34.808 6.984 ;
     RECT  34.657 8.208 34.808 9.048 ;
     RECT  33.82 10.368 34.808 11.16 ;
     RECT  34.009 12.288 34.808 13.128 ;
     RECT  33.653 14.112 34.808 14.856 ;
     RECT  34.549 17.616 34.808 19.896 ;
     RECT  34.657 20.928 34.808 22.488 ;
     RECT  34.801 23.568 34.808 23.64 ;
     RECT  34.441 25.632 34.808 31.272 ;
     RECT  33.653 32.496 34.808 36.504 ;
     RECT  34.621 37.584 34.808 41.784 ;
     RECT  34.477 43.824 34.808 49.032 ;
     RECT  34.513 50.4 34.808 50.76 ;
     RECT  34.765 52.512 34.808 53.592 ;
     RECT  34.693 54.672 34.808 59.832 ;
     RECT  34.657 60.912 34.808 60.936 ;
     RECT  33.833 62.544 34.808 62.568 ;
     RECT  33.541 64.368 34.808 64.392 ;
     RECT  34.405 65.52 34.808 66.168 ;
     RECT  34.189 68.448 34.808 68.904 ;
     RECT  34.453 70.704 34.808 72.792 ;
     RECT  34.585 75.264 34.808 79.56 ;
     RECT  33.577 80.64 34.808 81.576 ;
     RECT  34.729 83.76 34.808 83.784 ;
     RECT  34.477 84.96 34.808 89.976 ;
     RECT  34.808 2.148 34.912 90.732 ;
     RECT  34.912 2.418 35.104 90.462 ;
     RECT  35.104 33.888 35.165 35.352 ;
     RECT  35.104 60.912 35.165 61.08 ;
     RECT  35.104 30.624 35.219 30.792 ;
     RECT  35.104 31.92 35.219 32.472 ;
     RECT  35.104 36.336 35.237 36.456 ;
     RECT  35.104 64.368 35.245 65.544 ;
     RECT  35.104 22.848 35.273 25.272 ;
     RECT  35.104 40.464 35.273 45.72 ;
     RECT  35.104 59.808 35.309 59.832 ;
     RECT  35.104 53.568 35.315 55.512 ;
     RECT  35.245 64.992 35.315 65.544 ;
     RECT  35.104 12.288 35.345 12.792 ;
     RECT  35.104 52.128 35.356 52.152 ;
     RECT  35.104 38.112 35.363 39.384 ;
     RECT  35.104 75.072 35.363 75.096 ;
     RECT  35.104 2.544 35.381 2.616 ;
     RECT  35.345 12.288 35.381 12.312 ;
     RECT  35.104 76.08 35.404 77.88 ;
     RECT  35.104 88.368 35.417 88.44 ;
     RECT  35.104 3.648 35.459 6.888 ;
     RECT  35.273 41.472 35.489 45.72 ;
     RECT  35.104 56.88 35.489 58.824 ;
     RECT  35.459 6.24 35.561 6.888 ;
     RECT  35.363 38.112 35.597 38.136 ;
     RECT  35.104 47.376 35.597 48.264 ;
     RECT  35.104 7.872 35.603 11.256 ;
     RECT  35.489 41.616 35.633 45.72 ;
     RECT  35.489 56.88 35.669 58.776 ;
     RECT  35.603 10.56 35.705 11.256 ;
     RECT  35.104 19.344 35.705 19.56 ;
     RECT  35.104 50.4 35.705 50.856 ;
     RECT  35.315 65.136 35.705 65.544 ;
     RECT  35.603 8.544 35.777 9.48 ;
     RECT  35.459 3.648 35.813 5.064 ;
     RECT  35.104 62.112 35.813 62.568 ;
     RECT  35.104 85.872 35.843 87.384 ;
     RECT  35.104 29.04 35.849 29.592 ;
     RECT  35.404 76.992 35.849 77.88 ;
     RECT  35.104 80.64 35.857 82.632 ;
     RECT  35.561 6.24 35.885 6.648 ;
     RECT  35.633 41.616 35.891 43.944 ;
     RECT  35.857 80.64 35.913 82.584 ;
     RECT  35.669 58.128 35.921 58.44 ;
     RECT  35.849 29.04 35.957 29.064 ;
     RECT  35.843 85.872 35.957 86.28 ;
     RECT  35.104 16.752 35.987 17.064 ;
     RECT  35.104 72.768 36.029 73.512 ;
     RECT  35.315 54.048 36.065 55.512 ;
     RECT  35.813 62.112 36.065 62.28 ;
     RECT  35.913 81.6 36.065 82.584 ;
     RECT  35.104 26.256 36.101 27.624 ;
     RECT  36.065 54.624 36.209 55.512 ;
     RECT  35.273 24.528 36.236 25.272 ;
     RECT  36.101 26.256 36.236 26.28 ;
     RECT  35.104 68.16 36.277 69.288 ;
     RECT  35.104 79.152 36.277 79.464 ;
     RECT  35.417 88.368 36.289 88.392 ;
     RECT  35.891 41.616 36.317 42.168 ;
     RECT  36.236 24.528 36.323 26.28 ;
     RECT  35.381 2.544 36.349 2.568 ;
     RECT  35.813 3.648 36.349 4.536 ;
     RECT  35.104 21.072 36.349 21.72 ;
     RECT  35.165 34.08 36.349 35.352 ;
     RECT  35.237 36.432 36.349 36.456 ;
     RECT  35.597 47.376 36.349 47.496 ;
     RECT  36.277 67.68 36.349 69.288 ;
     RECT  35.219 32.448 36.353 32.472 ;
     RECT  35.843 87.36 36.389 87.384 ;
     RECT  35.705 50.4 36.412 50.424 ;
     RECT  36.349 20.976 36.421 21.72 ;
     RECT  35.633 44.976 36.421 45.72 ;
     RECT  36.349 46.8 36.421 47.496 ;
     RECT  35.165 61.008 36.421 61.08 ;
     RECT  36.349 34.08 36.425 36.456 ;
     RECT  35.987 17.04 36.449 17.064 ;
     RECT  35.104 18.144 36.449 18.168 ;
     RECT  35.273 22.848 36.467 23.448 ;
     RECT  36.421 60.384 36.467 61.08 ;
     RECT  36.277 79.152 36.469 79.656 ;
     RECT  35.104 14.64 36.493 15.432 ;
     RECT  36.449 17.04 36.493 18.168 ;
     RECT  35.705 19.344 36.493 19.368 ;
     RECT  36.349 66.768 36.493 69.288 ;
     RECT  36.476 74.016 36.563 74.04 ;
     RECT  36.421 75.936 36.563 75.96 ;
     RECT  36.287 51.888 36.565 51.912 ;
     RECT  36.529 37.968 36.601 37.992 ;
     RECT  36.421 20.496 36.605 21.72 ;
     RECT  35.891 43.296 36.605 43.944 ;
     RECT  36.467 60.384 36.605 60.408 ;
     RECT  36.469 79.152 36.637 80.376 ;
     RECT  36.601 37.872 36.641 37.992 ;
     RECT  36.605 20.496 36.677 21.192 ;
     RECT  35.921 58.128 36.677 58.248 ;
     RECT  36.493 12.528 36.709 12.552 ;
     RECT  36.065 62.112 36.709 62.184 ;
     RECT  35.705 65.136 36.709 65.16 ;
     RECT  36.421 44.976 36.713 47.496 ;
     RECT  36.605 43.92 36.745 43.944 ;
     RECT  36.713 44.976 36.745 45.144 ;
     RECT  35.273 40.464 36.757 40.488 ;
     RECT  36.317 41.616 36.757 41.688 ;
     RECT  35.363 39.312 36.781 39.384 ;
     RECT  36.757 40.464 36.781 41.688 ;
     RECT  35.885 6.624 36.785 6.648 ;
     RECT  36.425 35.328 36.821 36.456 ;
     RECT  36.781 39.312 36.844 41.688 ;
     RECT  36.493 17.04 36.893 19.368 ;
     RECT  36.745 43.92 36.893 45.144 ;
     RECT  36.812 71.664 36.899 71.688 ;
     RECT  36.893 44.256 36.929 45.144 ;
     RECT  36.709 64.752 36.956 65.16 ;
     RECT  35.777 8.544 36.961 8.568 ;
     RECT  36.925 29.184 36.961 29.208 ;
     RECT  35.957 86.256 36.965 86.28 ;
     RECT  36.961 8.544 36.997 9.336 ;
     RECT  35.705 10.944 36.997 11.256 ;
     RECT  36.493 66.768 37.037 70.104 ;
     RECT  36.956 64.752 37.043 65.688 ;
     RECT  37.037 66.768 37.043 67.56 ;
     RECT  36.997 8.544 37.069 11.256 ;
     RECT  36.709 12.528 37.069 12.744 ;
     RECT  36.323 24.528 37.069 24.984 ;
     RECT  36.961 28.992 37.069 29.208 ;
     RECT  36.893 17.568 37.073 19.368 ;
     RECT  37.069 8.544 37.109 12.744 ;
     RECT  36.844 39.312 37.109 40.152 ;
     RECT  37.043 66.768 37.109 67.032 ;
     RECT  35.849 76.992 37.109 77.016 ;
     RECT  36.821 36.096 37.141 36.456 ;
     RECT  36.641 37.872 37.141 37.896 ;
     RECT  36.493 14.208 37.177 15.432 ;
     RECT  36.029 72.768 37.177 72.936 ;
     RECT  36.713 46.512 37.181 47.496 ;
     RECT  36.709 61.776 37.217 62.184 ;
     RECT  37.177 72.576 37.217 72.936 ;
     RECT  37.217 62.112 37.249 62.184 ;
     RECT  35.219 30.624 37.285 30.648 ;
     RECT  37.181 46.896 37.289 47.496 ;
     RECT  37.177 14.208 37.321 15.96 ;
     RECT  37.109 8.544 37.325 12.024 ;
     RECT  37.285 30.624 37.331 30.936 ;
     RECT  36.385 48.912 37.361 48.936 ;
     RECT  36.677 58.128 37.393 58.152 ;
     RECT  36.844 41.616 37.397 41.688 ;
     RECT  36.349 2.544 37.427 4.536 ;
     RECT  37.033 22.752 37.429 22.776 ;
     RECT  37.037 69.264 37.429 70.104 ;
     RECT  37.325 8.544 37.433 9.288 ;
     RECT  37.393 57.984 37.433 58.152 ;
     RECT  37.249 62.112 37.433 62.472 ;
     RECT  37.429 69.264 37.433 70.584 ;
     RECT  36.817 31.968 37.465 31.992 ;
     RECT  36.677 20.976 37.469 21.192 ;
     RECT  37.331 30.912 37.469 30.936 ;
     RECT  37.285 66.672 37.505 66.696 ;
     RECT  37.073 17.568 37.613 18.168 ;
     RECT  36.101 27.6 37.645 27.624 ;
     RECT  37.321 13.296 37.649 15.96 ;
     RECT  37.141 36.096 37.667 37.896 ;
     RECT  37.667 37.872 37.685 37.896 ;
     RECT  37.649 14.736 37.721 14.952 ;
     RECT  37.429 22.608 37.765 22.776 ;
     RECT  37.109 40.128 37.825 40.152 ;
     RECT  37.397 41.616 37.825 41.64 ;
     RECT  36.929 44.688 37.825 45.144 ;
     RECT  37.765 21.648 37.852 22.776 ;
     RECT  36.565 51.744 37.861 51.912 ;
     RECT  37.069 28.992 37.889 29.352 ;
     RECT  37.889 28.992 37.955 29.688 ;
     RECT  35.669 56.88 37.969 56.904 ;
     RECT  37.433 57.984 37.969 58.008 ;
     RECT  37.721 14.784 37.973 14.952 ;
     RECT  37.825 40.128 37.973 41.64 ;
     RECT  37.289 46.896 37.973 47.352 ;
     RECT  36.323 26.256 38.005 26.28 ;
     RECT  37.645 27.312 38.005 27.624 ;
     RECT  37.465 31.968 38.005 32.376 ;
     RECT  37.609 6 38.041 6.024 ;
     RECT  36.637 78.48 38.041 80.376 ;
     RECT  38.005 26.256 38.077 27.624 ;
     RECT  37.043 64.752 38.081 65.16 ;
     RECT  38.041 78.048 38.081 80.376 ;
     RECT  37.433 62.448 38.113 62.472 ;
     RECT  37.333 63.6 38.113 63.624 ;
     RECT  37.649 15.936 38.149 15.96 ;
     RECT  36.425 34.08 38.149 34.2 ;
     RECT  38.005 75.216 38.149 75.24 ;
     RECT  37.433 8.544 38.156 8.712 ;
     RECT  37.073 19.344 38.189 19.368 ;
     RECT  37.217 72.576 38.189 72.792 ;
     RECT  38.081 79.44 38.189 80.376 ;
     RECT  38.149 34.08 38.221 34.92 ;
     RECT  38.041 6 38.225 6.264 ;
     RECT  37.433 69.264 38.225 69.528 ;
     RECT  38.156 7.92 38.243 8.712 ;
     RECT  37.861 51.744 38.252 52.488 ;
     RECT  38.149 15.936 38.257 16.056 ;
     RECT  38.189 72.576 38.257 72.6 ;
     RECT  37.325 10.272 38.261 12.024 ;
     RECT  37.973 14.784 38.261 14.808 ;
     RECT  38.221 33.84 38.261 34.92 ;
     RECT  37.069 23.808 38.297 24.984 ;
     RECT  38.077 26.256 38.297 27.96 ;
     RECT  38.257 72.384 38.297 72.6 ;
     RECT  38.297 23.808 38.333 24.744 ;
     RECT  37.825 44.688 38.333 45.624 ;
     RECT  38.252 51.264 38.339 52.488 ;
     RECT  38.261 34.896 38.365 34.92 ;
     RECT  37.667 36.096 38.365 36.168 ;
     RECT  37.681 50.016 38.365 50.04 ;
     RECT  37.427 2.784 38.387 4.536 ;
     RECT  37.717 20.496 38.401 20.52 ;
     RECT  37.852 22.32 38.401 22.776 ;
     RECT  38.333 23.808 38.401 24.072 ;
     RECT  38.387 2.784 38.405 3.336 ;
     RECT  38.339 51.888 38.405 52.488 ;
     RECT  38.405 3.312 38.435 3.336 ;
     RECT  38.401 20.016 38.441 20.52 ;
     RECT  37.973 40.944 38.477 41.64 ;
     RECT  37.789 59.856 38.485 59.88 ;
     RECT  38.005 31.968 38.509 32.472 ;
     RECT  38.297 26.4 38.513 27.96 ;
     RECT  38.485 59.232 38.531 60.408 ;
     RECT  38.081 64.896 38.549 65.16 ;
     RECT  38.189 79.44 38.549 79.848 ;
     RECT  38.261 10.272 38.581 11.976 ;
     RECT  38.081 78.048 38.581 78.072 ;
     RECT  38.513 26.4 38.621 26.664 ;
     RECT  36.065 82.56 38.621 82.584 ;
     RECT  38.365 49.536 38.629 50.856 ;
     RECT  38.477 41.616 38.653 41.64 ;
     RECT  38.437 42.72 38.653 42.744 ;
     RECT  37.433 70.56 38.653 70.584 ;
     RECT  37.955 29.616 38.677 29.688 ;
     RECT  38.257 15.936 38.684 16.536 ;
     RECT  37.613 17.616 38.684 18.168 ;
     RECT  37.649 13.296 38.689 13.656 ;
     RECT  38.401 22.32 38.693 24.072 ;
     RECT  37.969 56.88 38.693 58.008 ;
     RECT  38.581 77.52 38.693 78.072 ;
     RECT  38.693 22.608 38.723 24.072 ;
     RECT  38.684 15.936 38.725 18.168 ;
     RECT  38.693 57.024 38.729 58.008 ;
     RECT  37.825 66.144 38.761 66.168 ;
     RECT  38.545 67.824 38.761 67.848 ;
     RECT  38.677 29.616 38.764 29.928 ;
     RECT  38.723 22.608 38.765 23.448 ;
     RECT  38.653 41.616 38.765 42.744 ;
     RECT  38.725 15.936 38.771 18.216 ;
     RECT  38.629 48.864 38.771 50.856 ;
     RECT  38.581 38.688 38.773 38.712 ;
     RECT  38.149 74.976 38.773 75.24 ;
     RECT  37.609 76.32 38.773 76.344 ;
     RECT  38.693 77.52 38.773 77.592 ;
     RECT  38.771 18.144 38.797 18.216 ;
     RECT  38.531 60.384 38.801 60.408 ;
     RECT  38.113 62.448 38.801 63.624 ;
     RECT  37.969 54.144 38.805 54.168 ;
     RECT  38.581 9.744 38.819 11.976 ;
     RECT  38.773 38.688 38.819 39.912 ;
     RECT  38.761 66.144 38.819 67.848 ;
     RECT  38.773 74.976 38.819 77.592 ;
     RECT  38.509 31.296 38.833 32.472 ;
     RECT  38.261 33.84 38.833 33.864 ;
     RECT  38.819 66.144 38.845 67.272 ;
     RECT  38.819 76.896 38.86 77.592 ;
     RECT  38.771 15.936 38.867 16.536 ;
     RECT  36.209 55.488 38.869 55.512 ;
     RECT  38.387 4.512 38.873 4.536 ;
     RECT  38.819 9.984 38.873 11.976 ;
     RECT  38.243 8.448 38.88 8.712 ;
     RECT  38.805 53.232 38.905 54.168 ;
     RECT  38.869 55.488 38.905 55.56 ;
     RECT  38.225 6 38.945 6.024 ;
     RECT  38.797 18.144 38.945 18.792 ;
     RECT  38.771 49.056 38.945 50.856 ;
     RECT  38.905 53.232 38.945 55.56 ;
     RECT  38.945 18.144 38.981 18.552 ;
     RECT  38.873 9.984 39.017 11.304 ;
     RECT  38.833 31.296 39.017 33.864 ;
     RECT  38.549 64.896 39.017 64.92 ;
     RECT  39.017 31.296 39.053 32.472 ;
     RECT  38.801 63.6 39.053 63.624 ;
     RECT  38.653 70.56 39.053 70.728 ;
     RECT  38.867 15.936 39.085 16.488 ;
     RECT  38.365 34.896 39.085 36.168 ;
     RECT  38.333 44.688 39.085 45.048 ;
     RECT  38.729 57.024 39.089 57.48 ;
     RECT  38.225 69.456 39.121 69.528 ;
     RECT  38.689 13.296 39.125 13.848 ;
     RECT  39.085 43.776 39.125 45.048 ;
     RECT  39.085 34.896 39.161 37.032 ;
     RECT  38.764 29.616 39.197 29.64 ;
     RECT  39.125 43.776 39.233 43.8 ;
     RECT  39.053 31.296 39.265 31.992 ;
     RECT  38.297 72.384 39.337 72.408 ;
     RECT  39.125 13.68 39.409 13.848 ;
     RECT  39.085 15.312 39.409 16.488 ;
     RECT  38.765 41.616 39.445 41.64 ;
     RECT  38.945 53.232 39.445 53.256 ;
     RECT  38.341 7.44 39.517 7.464 ;
     RECT  38.88 8.448 39.517 8.472 ;
     RECT  38.441 20.016 39.517 20.04 ;
     RECT  39.017 33.84 39.517 33.864 ;
     RECT  39.161 34.896 39.517 35.736 ;
     RECT  38.531 59.232 39.517 59.256 ;
     RECT  39.517 7.44 39.553 8.472 ;
     RECT  39.121 69.456 39.661 70.248 ;
     RECT  38.549 79.728 39.841 79.848 ;
     RECT  38.819 74.976 39.884 75.816 ;
     RECT  39.337 71.52 39.913 72.408 ;
     RECT  38.765 42.72 39.925 42.744 ;
     RECT  39.517 58.656 39.949 59.256 ;
     RECT  39.229 62.16 39.985 62.184 ;
     RECT  39.553 6.864 40.208 8.472 ;
     RECT  39.017 9.984 40.208 10.296 ;
     RECT  39.017 11.28 40.208 11.304 ;
     RECT  39.409 13.68 40.208 16.488 ;
     RECT  38.981 18.192 40.208 18.552 ;
     RECT  39.517 20.016 40.208 20.52 ;
     RECT  38.765 22.704 40.208 23.448 ;
     RECT  39.661 25.632 40.208 25.656 ;
     RECT  38.621 26.64 40.208 26.664 ;
     RECT  38.513 27.936 40.208 27.96 ;
     RECT  39.265 31.152 40.208 31.992 ;
     RECT  39.517 33.84 40.208 35.736 ;
     RECT  39.161 37.008 40.208 37.032 ;
     RECT  38.819 38.784 40.208 39.912 ;
     RECT  39.445 40.992 40.208 41.64 ;
     RECT  39.925 42.72 40.208 43.176 ;
     RECT  39.125 44.88 40.208 45.048 ;
     RECT  37.973 47.328 40.208 47.352 ;
     RECT  38.945 49.056 40.208 49.56 ;
     RECT  38.945 50.832 40.208 50.856 ;
     RECT  39.445 52.8 40.208 53.256 ;
     RECT  38.945 54.576 40.208 55.56 ;
     RECT  39.089 57.456 40.208 57.48 ;
     RECT  39.949 58.56 40.208 59.256 ;
     RECT  39.985 62.16 40.208 62.76 ;
     RECT  38.845 66.144 40.208 66.168 ;
     RECT  38.845 67.248 40.208 67.272 ;
     RECT  39.661 68.784 40.208 70.248 ;
     RECT  39.913 71.52 40.208 72.984 ;
     RECT  39.884 74.64 40.208 75.816 ;
     RECT  38.86 77.568 40.208 77.592 ;
     RECT  39.841 79.008 40.208 79.848 ;
     RECT  38.341 81.36 40.208 81.384 ;
     RECT  40.208 2.148 40.312 90.732 ;
     RECT  40.312 2.418 40.504 90.462 ;
     RECT  40.504 71.712 40.529 71.736 ;
    LAYER M5 ;
     RECT  9.024 0.144 13.512 0.563 ;
     RECT  9.456 0.563 13.512 1.763 ;
     RECT  2.4 2.137 2.52 2.151 ;
     RECT  7.8 2.137 7.92 2.151 ;
     RECT  18.6 2.137 18.72 2.151 ;
     RECT  24 2.137 24.12 2.151 ;
     RECT  29.4 2.137 29.52 2.151 ;
     RECT  34.8 2.137 34.92 2.151 ;
     RECT  40.2 2.137 40.32 2.151 ;
     RECT  34.8 2.151 35.112 2.581 ;
     RECT  2.4 2.151 2.712 2.677 ;
     RECT  5.76 2.677 5.784 2.821 ;
     RECT  18.6 2.151 18.912 2.821 ;
     RECT  29.4 2.151 29.712 2.917 ;
     RECT  4.608 2.821 5.784 3.107 ;
     RECT  7.8 2.151 8.112 3.349 ;
     RECT  7.056 3.349 8.112 3.397 ;
     RECT  5.76 3.107 5.784 3.587 ;
     RECT  37.392 2.533 37.416 3.685 ;
     RECT  38.4 3.301 38.424 3.685 ;
     RECT  7.056 3.397 8.856 3.733 ;
     RECT  9.888 1.763 13.512 3.733 ;
     RECT  17.616 2.821 19.032 3.827 ;
     RECT  24 2.151 24.312 3.925 ;
     RECT  2.4 2.677 3.336 4.115 ;
     RECT  18.6 3.827 19.032 4.115 ;
     RECT  37.392 3.685 38.424 4.547 ;
     RECT  7.056 3.733 13.512 4.643 ;
     RECT  15.36 4.357 15.384 4.645 ;
     RECT  24 3.925 24.408 4.691 ;
     RECT  12.576 4.643 13.512 4.739 ;
     RECT  7.056 4.643 11.256 4.931 ;
     RECT  18.6 4.115 18.912 5.029 ;
     RECT  34.224 2.581 35.112 5.029 ;
     RECT  4.56 3.829 4.584 5.077 ;
     RECT  15.36 4.645 15.624 5.077 ;
     RECT  20.496 2.773 20.52 5.077 ;
     RECT  18.48 5.029 18.912 5.125 ;
     RECT  2.4 4.115 2.712 5.173 ;
     RECT  29.4 2.917 30.456 5.219 ;
     RECT  34.224 5.029 35.448 5.219 ;
     RECT  13.008 4.739 13.512 5.459 ;
     RECT  4.56 5.077 4.872 5.461 ;
     RECT  4.56 5.461 5.016 5.653 ;
     RECT  28.224 2.245 28.248 5.747 ;
     RECT  32.448 4.981 32.472 5.747 ;
     RECT  18.48 5.125 19.032 5.749 ;
     RECT  18.432 5.749 19.032 5.795 ;
     RECT  22.752 4.645 22.776 5.891 ;
     RECT  2.4 5.173 3.48 6.275 ;
     RECT  15.36 5.077 16.296 6.323 ;
     RECT  2.4 6.275 2.808 6.419 ;
     RECT  20.496 5.077 21.144 6.563 ;
     RECT  18.432 5.795 18.912 6.565 ;
     RECT  13.2 5.459 13.512 6.709 ;
     RECT  13.2 6.709 14.184 6.805 ;
     RECT  24 4.691 24.312 6.805 ;
     RECT  34.8 5.219 35.448 6.899 ;
     RECT  13.056 6.805 14.184 7.045 ;
     RECT  27.312 6.805 27.336 7.237 ;
     RECT  4.512 5.653 5.016 7.331 ;
     RECT  23.904 6.805 24.312 7.429 ;
     RECT  37.392 4.547 38.376 7.475 ;
     RECT  27.264 7.237 27.336 7.667 ;
     RECT  18.384 6.565 18.912 7.765 ;
     RECT  34.8 6.899 35.112 7.861 ;
     RECT  2.4 6.419 2.712 7.909 ;
     RECT  23.712 7.429 24.312 7.909 ;
     RECT  29.4 5.219 29.832 7.909 ;
     RECT  15.6 6.323 16.296 7.955 ;
     RECT  12.96 7.045 14.184 8.003 ;
     RECT  7.584 4.931 11.256 8.485 ;
     RECT  33.312 6.613 33.336 8.485 ;
     RECT  18.24 7.765 18.912 8.579 ;
     RECT  12.96 8.003 13.656 8.627 ;
     RECT  2.304 7.909 2.712 8.677 ;
     RECT  37.392 7.475 38.232 8.677 ;
     RECT  37.392 8.677 38.808 8.723 ;
     RECT  2.304 8.677 2.808 8.819 ;
     RECT  22.944 7.909 24.312 8.867 ;
     RECT  27.312 7.667 27.336 9.011 ;
     RECT  7.584 8.485 11.976 9.061 ;
     RECT  29.4 7.909 30.168 9.061 ;
     RECT  29.4 9.061 31.128 9.107 ;
     RECT  2.304 8.819 2.712 9.155 ;
     RECT  15.6 7.955 16.008 9.155 ;
     RECT  25.68 8.485 25.704 9.205 ;
     RECT  25.392 9.205 25.704 9.251 ;
     RECT  4.992 7.331 5.016 9.637 ;
     RECT  18.48 8.579 18.912 9.637 ;
     RECT  25.392 9.251 25.416 9.779 ;
     RECT  38.784 8.723 38.808 9.779 ;
     RECT  7.392 9.061 11.976 10.067 ;
     RECT  18.192 9.637 18.912 10.211 ;
     RECT  21.84 8.821 21.864 10.307 ;
     RECT  4.896 9.637 5.016 10.309 ;
     RECT  7.392 10.067 11.256 10.453 ;
     RECT  4.896 10.309 5.112 10.595 ;
     RECT  34.8 7.861 35.592 10.595 ;
     RECT  13.2 8.627 13.656 10.693 ;
     RECT  33.312 8.485 33.768 10.739 ;
     RECT  29.4 9.107 29.712 10.789 ;
     RECT  31.104 9.107 31.128 10.883 ;
     RECT  13.104 10.693 13.656 10.931 ;
     RECT  20.496 6.563 20.52 10.981 ;
     RECT  18.6 10.211 18.912 11.221 ;
     RECT  7.248 10.453 11.256 11.365 ;
     RECT  26.592 10.741 26.616 11.365 ;
     RECT  25.92 11.365 26.616 11.411 ;
     RECT  28.896 10.789 29.712 11.411 ;
     RECT  5.088 10.595 5.112 11.507 ;
     RECT  37.392 8.723 37.416 11.509 ;
     RECT  37.248 11.509 37.416 11.555 ;
     RECT  7.248 11.365 11.592 11.701 ;
     RECT  6.864 11.701 11.592 11.987 ;
     RECT  32.304 11.317 32.328 11.987 ;
     RECT  25.92 11.411 26.232 12.035 ;
     RECT  7.392 11.987 11.592 12.179 ;
     RECT  23.712 8.867 24.312 12.229 ;
     RECT  25.92 12.035 25.944 12.275 ;
     RECT  15.6 9.155 15.624 12.373 ;
     RECT  29.4 11.411 29.712 12.517 ;
     RECT  19.968 10.981 20.52 12.563 ;
     RECT  22.08 11.269 22.104 12.563 ;
     RECT  31.056 11.269 31.08 12.563 ;
     RECT  33.312 10.739 33.336 12.757 ;
     RECT  34.8 10.595 35.112 12.757 ;
     RECT  17.76 11.221 18.912 13.045 ;
     RECT  23.712 12.229 24.408 13.045 ;
     RECT  33.312 12.757 35.112 13.045 ;
     RECT  23.712 13.045 25.128 13.139 ;
     RECT  15.6 12.373 16.008 13.573 ;
     RECT  32.448 13.045 35.112 13.573 ;
     RECT  17.712 13.045 18.912 13.715 ;
     RECT  27.648 12.517 27.672 13.715 ;
     RECT  29.232 12.517 29.712 13.811 ;
     RECT  40.2 2.151 40.512 13.813 ;
     RECT  18 13.715 18.912 14.101 ;
     RECT  31.872 13.573 35.112 14.147 ;
     RECT  7.392 12.179 11.544 14.197 ;
     RECT  5.952 13.045 5.976 14.243 ;
     RECT  14.928 13.573 16.008 14.293 ;
     RECT  4.368 11.701 4.392 14.387 ;
     RECT  24 13.139 25.128 14.387 ;
     RECT  14.928 14.293 16.152 14.485 ;
     RECT  14.928 14.485 16.872 14.627 ;
     RECT  26.352 13.333 26.376 14.819 ;
     RECT  24 14.387 24.408 14.867 ;
     RECT  7.152 14.197 11.544 14.915 ;
     RECT  18 14.101 19.176 14.915 ;
     RECT  31.872 14.147 33.336 14.915 ;
     RECT  13.2 10.931 13.656 14.965 ;
     RECT  13.2 14.965 13.752 15.203 ;
     RECT  29.28 13.811 29.712 15.301 ;
     RECT  39.216 13.813 40.512 15.347 ;
     RECT  14.928 14.627 15.624 15.395 ;
     RECT  34.8 14.147 35.112 15.397 ;
     RECT  31.872 14.915 31.896 15.443 ;
     RECT  4.032 14.773 4.056 15.635 ;
     RECT  24 14.867 24.312 15.973 ;
     RECT  16.848 14.627 16.872 16.019 ;
     RECT  23.376 15.973 24.312 16.117 ;
     RECT  29.232 15.301 29.712 16.307 ;
     RECT  15.6 15.395 15.624 16.501 ;
     RECT  18 14.915 18.912 16.501 ;
     RECT  38.832 15.973 38.856 16.501 ;
     RECT  38.736 16.501 38.856 16.547 ;
     RECT  26.496 15.301 26.616 16.643 ;
     RECT  5.952 15.445 5.976 16.933 ;
     RECT  7.392 14.915 11.544 16.933 ;
     RECT  20.496 12.563 20.52 16.981 ;
     RECT  19.968 16.981 20.52 17.027 ;
     RECT  34.8 15.397 35.976 17.029 ;
     RECT  37.248 11.555 37.272 17.029 ;
     RECT  34.8 17.029 37.272 17.075 ;
     RECT  2.4 9.155 2.712 17.077 ;
     RECT  26.496 16.643 26.52 17.125 ;
     RECT  22.512 16.117 24.312 17.171 ;
     RECT  33.312 14.915 33.336 17.461 ;
     RECT  29.4 16.307 29.712 17.509 ;
     RECT  5.712 16.933 11.544 17.603 ;
     RECT  26.208 17.125 26.52 17.605 ;
     RECT  34.8 17.075 35.112 17.605 ;
     RECT  17.76 16.501 18.912 17.651 ;
     RECT  36.48 17.075 37.272 17.653 ;
     RECT  2.4 17.077 2.856 17.699 ;
     RECT  5.712 17.603 5.976 17.699 ;
     RECT  22.512 17.171 22.536 17.699 ;
     RECT  36.48 17.653 37.32 17.699 ;
     RECT  19.968 17.027 20.136 18.133 ;
     RECT  29.28 17.509 29.712 18.133 ;
     RECT  34.56 17.605 35.112 18.133 ;
     RECT  38.736 16.547 38.76 18.227 ;
     RECT  34.56 18.133 35.352 18.419 ;
     RECT  29.232 18.133 29.712 18.707 ;
     RECT  7.584 17.603 11.544 18.709 ;
     RECT  2.4 17.699 2.712 18.757 ;
     RECT  15.456 16.501 15.624 18.757 ;
     RECT  29.28 18.707 29.712 18.805 ;
     RECT  5.952 17.699 5.976 19.093 ;
     RECT  26.208 17.605 27.144 19.235 ;
     RECT  5.952 19.093 6.312 19.333 ;
     RECT  32.736 17.461 33.336 19.523 ;
     RECT  34.8 18.419 35.352 19.571 ;
     RECT  15.408 18.757 15.624 19.763 ;
     RECT  7.584 18.709 12.024 19.765 ;
     RECT  13.2 15.203 13.656 19.765 ;
     RECT  24 17.171 24.312 19.909 ;
     RECT  19.968 18.133 20.52 20.003 ;
     RECT  5.856 19.333 6.312 20.533 ;
     RECT  18 17.651 18.912 20.533 ;
     RECT  26.208 19.235 26.232 20.579 ;
     RECT  23.04 19.909 24.312 20.581 ;
     RECT  2.4 18.757 2.856 20.627 ;
     RECT  29.28 18.805 30.456 20.677 ;
     RECT  33.312 19.523 33.336 20.723 ;
     RECT  20.016 20.003 20.52 21.155 ;
     RECT  23.04 20.581 25.08 21.155 ;
     RECT  5.856 20.533 6.408 21.395 ;
     RECT  29.28 20.677 30.84 21.637 ;
     RECT  37.296 17.699 37.32 21.637 ;
     RECT  29.04 21.637 31.368 21.683 ;
     RECT  37.296 21.637 37.8 21.685 ;
     RECT  18 20.533 19.032 21.827 ;
     RECT  20.016 21.155 20.04 21.875 ;
     RECT  5.856 21.395 5.88 22.117 ;
     RECT  18 21.827 18.912 22.165 ;
     RECT  24 21.155 24.312 22.165 ;
     RECT  7.584 19.765 13.656 22.499 ;
     RECT  29.04 21.683 29.712 22.499 ;
     RECT  36.432 21.685 37.8 22.597 ;
     RECT  36.432 22.597 38.712 22.787 ;
     RECT  20.448 22.165 20.472 22.835 ;
     RECT  27.648 21.637 27.672 22.835 ;
     RECT  30.816 21.683 31.368 22.835 ;
     RECT  36.432 22.787 37.32 22.883 ;
     RECT  5.136 22.117 5.88 23.123 ;
     RECT  12.384 22.499 13.656 23.125 ;
     RECT  15.6 19.763 15.624 23.173 ;
     RECT  17.664 22.165 18.912 23.219 ;
     RECT  7.584 22.499 11.256 23.269 ;
     RECT  30.816 22.835 30.84 23.411 ;
     RECT  17.856 23.219 18.912 23.699 ;
     RECT  24 22.165 24.504 23.891 ;
     RECT  29.4 22.499 29.712 23.893 ;
     RECT  15.6 23.173 16.584 23.987 ;
     RECT  38.688 22.787 38.712 24.083 ;
     RECT  4.608 23.317 4.632 24.131 ;
     RECT  7.056 23.269 11.256 24.131 ;
     RECT  12.384 23.125 13.704 24.469 ;
     RECT  18 23.699 18.912 24.469 ;
     RECT  34.8 19.571 35.112 24.469 ;
     RECT  32.496 23.029 32.52 24.707 ;
     RECT  5.856 23.123 5.88 24.805 ;
     RECT  37.296 22.883 37.32 24.805 ;
     RECT  18 24.469 19.704 25.045 ;
     RECT  2.4 20.627 2.712 25.093 ;
     RECT  24 23.891 24.456 25.093 ;
     RECT  5.856 24.805 6.024 25.139 ;
     RECT  33.504 22.693 33.528 25.187 ;
     RECT  2.4 25.093 3.672 25.285 ;
     RECT  7.584 24.131 11.256 25.333 ;
     RECT  7.392 25.333 11.256 25.475 ;
     RECT  12.384 24.469 14.232 25.475 ;
     RECT  15.6 23.987 15.624 25.525 ;
     RECT  21.744 25.189 21.768 25.525 ;
     RECT  21.6 25.525 21.768 25.571 ;
     RECT  29.4 23.893 30.456 25.573 ;
     RECT  29.28 25.573 30.456 25.621 ;
     RECT  2.4 25.285 3.864 25.955 ;
     RECT  36.288 24.517 36.312 25.955 ;
     RECT  6 25.139 6.024 26.053 ;
     RECT  13.104 25.475 14.232 26.243 ;
     RECT  15.504 25.525 15.624 26.243 ;
     RECT  34.8 24.469 35.208 26.291 ;
     RECT  37.296 24.805 38.184 26.291 ;
     RECT  21.6 25.571 21.624 26.677 ;
     RECT  23.568 25.093 24.456 26.723 ;
     RECT  34.8 26.291 35.112 26.725 ;
     RECT  17.088 25.045 19.704 26.771 ;
     RECT  17.088 26.771 18.912 26.819 ;
     RECT  29.28 25.621 31.32 26.819 ;
     RECT  3.84 25.955 3.864 27.059 ;
     RECT  6 26.053 6.072 27.059 ;
     RECT  7.488 25.475 11.256 27.203 ;
     RECT  29.28 26.819 29.712 27.203 ;
     RECT  13.104 26.243 13.656 27.301 ;
     RECT  6 27.059 6.024 27.347 ;
     RECT  15.6 26.243 15.624 27.493 ;
     RECT  21.6 26.677 22.056 27.587 ;
     RECT  34.176 26.725 35.112 27.635 ;
     RECT  31.152 26.819 31.32 27.637 ;
     RECT  31.152 27.637 31.944 27.829 ;
     RECT  15.6 27.493 15.816 27.971 ;
     RECT  30.816 27.829 31.944 28.021 ;
     RECT  30.72 28.021 31.944 28.259 ;
     RECT  24 26.723 24.456 28.405 ;
     RECT  7.584 27.203 11.256 28.453 ;
     RECT  23.328 28.405 24.456 28.453 ;
     RECT  25.632 22.021 25.656 28.453 ;
     RECT  30.816 28.259 31.944 28.691 ;
     RECT  16.992 27.877 17.016 28.789 ;
     RECT  18 26.819 18.912 28.789 ;
     RECT  16.992 28.789 18.912 28.979 ;
     RECT  15.6 27.971 15.624 28.981 ;
     RECT  37.296 26.291 37.32 28.981 ;
     RECT  23.328 28.453 25.656 29.123 ;
     RECT  24 29.123 25.656 29.461 ;
     RECT  34.8 27.635 35.112 29.557 ;
     RECT  7.392 28.453 11.256 29.605 ;
     RECT  29.4 27.203 29.712 29.605 ;
     RECT  31.248 28.691 31.944 29.605 ;
     RECT  15.6 28.981 15.816 29.699 ;
     RECT  19.968 28.837 19.992 29.699 ;
     RECT  37.296 28.981 37.944 29.699 ;
     RECT  24 29.461 26.232 29.795 ;
     RECT  31.248 29.605 32.376 29.795 ;
     RECT  17.088 28.979 18.912 30.035 ;
     RECT  31.296 29.795 32.376 30.035 ;
     RECT  21.6 27.587 21.624 30.181 ;
     RECT  25.632 29.795 26.232 30.323 ;
     RECT  37.296 29.699 37.32 30.659 ;
     RECT  21.6 30.181 22.248 30.661 ;
     RECT  12.96 27.301 13.656 30.851 ;
     RECT  24 29.795 24.504 30.851 ;
     RECT  29.4 29.605 30.216 30.851 ;
     RECT  21.6 30.661 22.824 30.899 ;
     RECT  29.4 30.851 29.712 31.285 ;
     RECT  38.688 29.893 38.712 31.331 ;
     RECT  7.392 29.605 11.976 31.379 ;
     RECT  22.8 30.899 22.824 31.669 ;
     RECT  24 30.851 24.456 31.669 ;
     RECT  7.392 31.379 11.256 31.907 ;
     RECT  34.8 29.557 35.208 31.955 ;
     RECT  17.616 30.035 18.912 32.149 ;
     RECT  22.8 31.669 24.456 32.339 ;
     RECT  20.304 30.229 20.328 32.483 ;
     RECT  6.336 31.861 6.36 33.013 ;
     RECT  24 32.339 24.456 33.013 ;
     RECT  31.296 30.035 31.32 33.013 ;
     RECT  22.8 32.339 22.824 33.107 ;
     RECT  26.208 30.323 26.232 33.875 ;
     RECT  31.296 33.013 32.184 33.877 ;
     RECT  31.296 33.877 32.616 33.923 ;
     RECT  15.6 29.699 15.624 34.117 ;
     RECT  34.8 31.955 35.112 34.165 ;
     RECT  5.568 33.013 6.36 34.259 ;
     RECT  4.224 33.637 4.248 34.355 ;
     RECT  15.504 34.117 15.624 34.355 ;
     RECT  17.088 32.149 18.912 34.355 ;
     RECT  32.16 33.923 32.616 34.835 ;
     RECT  18 34.355 18.912 35.317 ;
     RECT  29.136 31.285 29.712 35.845 ;
     RECT  5.568 34.259 5.592 35.987 ;
     RECT  24 33.013 24.792 35.989 ;
     RECT  17.808 35.317 18.912 36.035 ;
     RECT  24 35.989 25.416 36.035 ;
     RECT  38.16 34.165 38.184 36.085 ;
     RECT  37.632 36.085 38.184 36.131 ;
     RECT  15.6 34.355 15.624 36.421 ;
     RECT  34.224 34.165 35.112 36.421 ;
     RECT  27.792 35.029 27.816 36.515 ;
     RECT  25.392 36.035 25.416 36.803 ;
     RECT  15.6 36.421 15.72 36.997 ;
     RECT  31.296 35.557 31.32 37.571 ;
     RECT  22.992 35.989 23.016 37.619 ;
     RECT  34.224 36.421 35.352 37.619 ;
     RECT  37.632 36.131 37.656 37.907 ;
     RECT  5.136 36.469 5.16 38.147 ;
     RECT  24 36.035 24.312 38.245 ;
     RECT  24 38.245 24.408 38.627 ;
     RECT  20.208 37.477 20.232 38.675 ;
     RECT  28.896 35.845 29.712 38.677 ;
     RECT  21.6 30.899 21.624 39.061 ;
     RECT  34.8 37.619 35.352 39.061 ;
     RECT  40.2 15.347 40.512 39.205 ;
     RECT  18 36.035 18.912 39.301 ;
     RECT  34.176 39.061 35.352 39.347 ;
     RECT  28.368 38.677 30.216 39.443 ;
     RECT  38.784 38.677 38.808 39.443 ;
     RECT  28.896 39.443 30.216 39.445 ;
     RECT  40.08 39.205 40.512 39.587 ;
     RECT  2.4 25.955 2.712 39.733 ;
     RECT  17.664 39.301 18.912 39.877 ;
     RECT  32.592 34.835 32.616 39.923 ;
     RECT  15.6 36.997 16.344 39.973 ;
     RECT  17.664 39.877 19.704 39.973 ;
     RECT  21.6 39.061 22.2 40.261 ;
     RECT  21.6 40.261 22.872 40.355 ;
     RECT  7.584 31.907 11.256 40.405 ;
     RECT  2.4 39.733 2.856 40.451 ;
     RECT  15.6 39.973 19.704 40.499 ;
     RECT  24 38.627 24.312 40.693 ;
     RECT  25.488 37.573 25.512 40.693 ;
     RECT  22.848 40.355 22.872 40.787 ;
     RECT  27.12 39.829 27.144 40.835 ;
     RECT  28.896 39.445 30.312 40.931 ;
     RECT  34.176 39.347 35.112 41.075 ;
     RECT  29.4 40.931 30.312 41.411 ;
     RECT  40.2 39.587 40.512 41.413 ;
     RECT  21.6 40.355 21.624 41.509 ;
     RECT  13.2 30.851 13.656 41.557 ;
     RECT  7.584 40.405 11.448 41.651 ;
     RECT  36.768 41.029 36.792 41.699 ;
     RECT  24 40.693 25.512 42.083 ;
     RECT  4.8 38.725 4.824 42.085 ;
     RECT  34.8 41.075 35.112 42.133 ;
     RECT  32.544 40.165 32.568 42.179 ;
     RECT  13.2 41.557 14.52 42.181 ;
     RECT  15.6 40.499 18.912 42.181 ;
     RECT  6.288 40.405 6.312 42.227 ;
     RECT  26.784 41.605 26.808 42.373 ;
     RECT  26.496 42.373 26.808 42.419 ;
     RECT  13.2 42.181 18.912 42.467 ;
     RECT  24 42.083 24.552 42.515 ;
     RECT  7.584 41.651 11.256 42.709 ;
     RECT  13.2 42.467 14.28 42.709 ;
     RECT  4.416 42.085 4.824 42.755 ;
     RECT  34.8 42.133 35.88 42.755 ;
     RECT  20.784 41.509 21.624 42.803 ;
     RECT  40.08 41.413 40.512 43.141 ;
     RECT  4.8 42.755 4.824 43.379 ;
     RECT  15.6 42.467 16.248 43.379 ;
     RECT  32.64 42.565 32.664 43.379 ;
     RECT  24 42.515 24.312 43.909 ;
     RECT  13.008 42.709 14.28 44.099 ;
     RECT  39.936 43.141 40.512 44.915 ;
     RECT  15.6 43.379 15.624 44.965 ;
     RECT  23.28 43.909 24.312 44.965 ;
     RECT  26.496 42.419 26.52 44.965 ;
     RECT  29.4 41.411 29.712 44.965 ;
     RECT  30.816 42.709 30.84 44.965 ;
     RECT  29.4 44.965 30.84 45.059 ;
     RECT  26.496 44.965 26.76 45.395 ;
     RECT  13.2 44.099 14.28 45.635 ;
     RECT  15.6 44.965 16.392 45.635 ;
     RECT  26.736 45.395 26.76 45.635 ;
     RECT  29.4 45.059 29.928 45.635 ;
     RECT  23.28 44.965 25.128 45.731 ;
     RECT  7.584 42.709 11.736 46.211 ;
     RECT  32.208 44.389 32.232 46.211 ;
     RECT  0.24 14.869 0.264 46.355 ;
     RECT  29.4 45.635 29.712 46.597 ;
     RECT  13.2 45.635 13.656 46.645 ;
     RECT  21.6 42.803 21.624 46.645 ;
     RECT  23.28 45.731 24.312 46.787 ;
     RECT  20.256 44.725 20.28 46.931 ;
     RECT  12.96 46.645 13.656 47.075 ;
     RECT  7.584 46.211 11.256 47.171 ;
     RECT  2.4 40.451 2.712 47.269 ;
     RECT  7.584 47.171 10.776 47.651 ;
     RECT  2.4 47.269 3.48 47.845 ;
     RECT  13.2 47.075 13.656 47.893 ;
     RECT  29.088 46.597 29.712 48.371 ;
     RECT  7.8 47.651 10.776 48.419 ;
     RECT  2.4 47.845 4.296 48.659 ;
     RECT  5.28 46.645 5.304 48.659 ;
     RECT  13.2 47.893 13.752 48.659 ;
     RECT  38.64 47.317 38.664 48.853 ;
     RECT  38.64 48.853 38.76 48.899 ;
     RECT  15.6 45.635 15.624 48.997 ;
     RECT  34.8 42.755 35.112 48.997 ;
     RECT  29.28 48.371 29.712 49.525 ;
     RECT  38.736 48.899 38.76 49.571 ;
     RECT  31.68 47.461 31.704 50.051 ;
     RECT  4.512 48.805 5.064 50.053 ;
     RECT  24 46.787 24.312 50.053 ;
     RECT  18 42.467 18.912 50.101 ;
     RECT  19.92 47.845 19.944 50.101 ;
     RECT  18 50.101 19.944 50.147 ;
     RECT  15.6 48.997 16.296 50.339 ;
     RECT  34.176 48.997 35.112 50.435 ;
     RECT  7.8 48.419 8.112 50.437 ;
     RECT  2.4 48.659 3.48 50.677 ;
     RECT  4.512 50.053 5.736 50.677 ;
     RECT  15.6 50.339 15.624 50.677 ;
     RECT  34.8 50.435 35.112 50.677 ;
     RECT  9.168 48.419 10.776 50.723 ;
     RECT  13.2 48.659 13.656 50.771 ;
     RECT  18 50.147 19.368 50.771 ;
     RECT  7.68 50.437 8.112 50.867 ;
     RECT  24 50.053 25.08 50.963 ;
     RECT  26.784 50.101 26.808 51.107 ;
     RECT  22.608 50.101 22.632 51.205 ;
     RECT  22.608 51.205 22.776 51.251 ;
     RECT  7.8 50.867 8.112 51.253 ;
     RECT  9.168 50.723 9.96 51.253 ;
     RECT  21.36 46.645 21.624 51.347 ;
     RECT  14.784 50.677 15.624 51.395 ;
     RECT  2.4 50.677 5.736 51.781 ;
     RECT  36.336 50.389 36.36 51.923 ;
     RECT  15.6 51.395 15.624 52.499 ;
     RECT  22.752 51.251 22.776 52.547 ;
     RECT  7.8 51.253 9.96 52.981 ;
     RECT  7.488 52.981 9.96 53.171 ;
     RECT  38.304 51.253 38.328 53.221 ;
     RECT  13.2 50.771 13.512 53.365 ;
     RECT  20.016 52.885 20.04 53.509 ;
     RECT  20.016 53.509 20.52 53.555 ;
     RECT  33.648 52.981 33.672 53.795 ;
     RECT  11.808 50.677 11.832 54.035 ;
     RECT  7.8 53.171 9.96 54.083 ;
     RECT  34.8 50.677 35.304 54.083 ;
     RECT  24 50.963 24.312 54.085 ;
     RECT  38.304 53.221 38.856 54.179 ;
     RECT  2.4 51.781 6.12 54.419 ;
     RECT  40.08 44.915 40.512 54.565 ;
     RECT  13.2 53.365 13.704 54.661 ;
     RECT  33.696 54.133 33.72 54.707 ;
     RECT  25.68 51.781 25.704 54.755 ;
     RECT  9.936 54.083 9.96 54.851 ;
     RECT  28.08 54.085 28.104 54.853 ;
     RECT  29.088 49.525 29.712 54.853 ;
     RECT  28.08 54.853 29.712 54.899 ;
     RECT  18 50.771 18.912 55.379 ;
     RECT  7.8 54.083 8.232 55.475 ;
     RECT  39.312 54.565 40.512 55.571 ;
     RECT  18.48 55.379 18.912 55.621 ;
     RECT  16.32 54.613 16.344 55.859 ;
     RECT  18.48 55.621 19.272 56.003 ;
     RECT  31.872 55.045 31.896 56.243 ;
     RECT  7.8 55.475 8.112 56.389 ;
     RECT  18.6 56.003 19.272 56.437 ;
     RECT  20.496 53.555 20.52 56.437 ;
     RECT  12.48 54.661 13.704 56.483 ;
     RECT  18.6 56.437 20.52 56.483 ;
     RECT  28.464 54.899 29.712 56.485 ;
     RECT  23.472 54.085 24.312 56.531 ;
     RECT  13.2 56.483 13.704 56.629 ;
     RECT  30.768 54.853 30.792 56.771 ;
     RECT  15.696 56.101 15.72 57.011 ;
     RECT  25.632 55.717 25.656 57.059 ;
     RECT  38.304 54.179 38.328 57.059 ;
     RECT  7.392 56.389 8.112 57.107 ;
     RECT  18.6 56.483 20.04 57.299 ;
     RECT  13.2 56.629 13.848 57.829 ;
     RECT  2.4 54.419 5.688 58.117 ;
     RECT  34.8 54.083 35.112 58.501 ;
     RECT  28.368 56.485 29.712 58.645 ;
     RECT  28.368 58.645 30.216 58.691 ;
     RECT  7.8 57.107 8.112 59.125 ;
     RECT  9.984 55.045 10.008 59.221 ;
     RECT  12.768 57.829 13.848 59.221 ;
     RECT  38.592 57.973 38.616 59.221 ;
     RECT  38.496 59.221 38.616 59.267 ;
     RECT  31.44 58.117 31.464 59.459 ;
     RECT  34.704 58.501 35.112 59.603 ;
     RECT  9.984 59.221 10.872 59.891 ;
     RECT  18.6 57.299 19.896 59.891 ;
     RECT  2.4 58.117 5.832 59.939 ;
     RECT  9.984 59.891 10.008 60.275 ;
     RECT  6.816 59.125 8.112 60.277 ;
     RECT  15.84 58.645 16.824 60.373 ;
     RECT  38.496 59.267 38.52 60.419 ;
     RECT  22.944 59.749 22.968 60.851 ;
     RECT  28.464 58.691 30.216 60.851 ;
     RECT  6.816 60.277 8.232 60.949 ;
     RECT  12.528 59.221 13.848 60.949 ;
     RECT  26.16 58.645 26.184 60.949 ;
     RECT  15.408 60.373 16.824 61.043 ;
     RECT  5.04 59.939 5.832 61.237 ;
     RECT  6.816 60.949 8.712 61.331 ;
     RECT  24 56.531 24.312 61.477 ;
     RECT  4.944 61.237 5.832 61.573 ;
     RECT  6.816 61.331 8.232 61.573 ;
     RECT  15.84 61.043 16.824 61.619 ;
     RECT  12.528 60.949 14.424 62.195 ;
     RECT  24 61.477 24.456 62.195 ;
     RECT  32.544 60.229 32.568 62.195 ;
     RECT  36.432 60.373 36.456 62.195 ;
     RECT  18.6 59.891 19.272 62.725 ;
     RECT  11.376 60.949 11.4 62.771 ;
     RECT  25.44 60.949 26.184 62.771 ;
     RECT  15.84 61.619 15.864 62.821 ;
     RECT  28.464 60.851 29.712 63.061 ;
     RECT  26.16 62.771 26.184 63.299 ;
     RECT  4.944 61.573 8.232 63.539 ;
     RECT  37.344 62.437 37.368 63.635 ;
     RECT  11.232 63.205 11.256 63.781 ;
     RECT  12.768 62.195 13.512 63.781 ;
     RECT  21.6 51.347 21.624 63.781 ;
     RECT  28.128 63.061 29.712 63.781 ;
     RECT  14.928 62.821 15.864 63.827 ;
     RECT  24 62.195 24.408 63.829 ;
     RECT  27.936 63.781 29.712 64.117 ;
     RECT  34.8 59.603 35.112 64.357 ;
     RECT  18.6 62.725 19.32 64.403 ;
     RECT  20.88 63.781 21.624 64.403 ;
     RECT  27.84 64.117 29.712 64.595 ;
     RECT  11.232 63.781 13.512 64.741 ;
     RECT  4.944 63.539 6.312 64.835 ;
     RECT  20.976 64.403 21.624 64.885 ;
     RECT  9.456 63.109 9.48 64.931 ;
     RECT  2.4 59.939 3.96 64.933 ;
     RECT  4.944 64.835 5.496 64.933 ;
     RECT  34.8 64.357 35.208 64.981 ;
     RECT  15.84 63.827 15.864 65.027 ;
     RECT  34.8 64.981 35.304 65.509 ;
     RECT  34.416 65.509 35.304 65.555 ;
     RECT  20.976 64.885 22.392 65.603 ;
     RECT  27.936 64.595 28.152 65.603 ;
     RECT  2.4 64.933 5.496 65.651 ;
     RECT  20.976 65.603 21.144 65.795 ;
     RECT  11.04 64.741 13.512 65.941 ;
     RECT  24 63.829 24.456 66.035 ;
     RECT  20.976 65.795 21 66.085 ;
     RECT  10.896 65.941 13.512 66.179 ;
     RECT  30.816 64.309 30.84 66.179 ;
     RECT  7.296 63.539 8.232 66.181 ;
     RECT  29.4 64.595 29.712 66.469 ;
     RECT  20.784 66.085 21 66.515 ;
     RECT  29.4 66.469 30.792 66.611 ;
     RECT  2.4 65.651 3.912 66.613 ;
     RECT  20.784 66.515 20.808 66.755 ;
     RECT  30.768 66.611 30.792 66.755 ;
     RECT  27.936 65.603 27.96 66.899 ;
     RECT  18.6 64.403 18.912 67.045 ;
     RECT  4.944 65.651 5.496 67.141 ;
     RECT  4.944 67.141 5.736 67.283 ;
     RECT  11.04 66.179 13.512 67.283 ;
     RECT  22.368 65.603 22.392 67.283 ;
     RECT  2.4 66.613 3.96 67.331 ;
     RECT  24 66.035 24.408 67.523 ;
     RECT  37.008 64.741 37.032 67.525 ;
     RECT  36.72 67.525 37.032 67.571 ;
     RECT  5.472 67.283 5.736 67.765 ;
     RECT  7.152 66.181 8.232 67.765 ;
     RECT  32.688 65.797 32.712 67.859 ;
     RECT  36.72 67.571 36.744 67.859 ;
     RECT  38.784 66.133 38.808 67.859 ;
     RECT  11.04 67.283 11.784 68.387 ;
     RECT  11.04 68.387 11.592 68.435 ;
     RECT  5.472 67.765 8.232 68.821 ;
     RECT  2.4 67.331 3.864 68.917 ;
     RECT  4.848 68.821 8.232 68.917 ;
     RECT  11.28 68.435 11.592 69.011 ;
     RECT  29.4 66.611 29.712 69.445 ;
     RECT  40.2 55.571 40.512 69.445 ;
     RECT  9.648 68.245 9.672 69.491 ;
     RECT  14.64 68.917 14.664 69.731 ;
     RECT  11.28 69.011 11.448 70.019 ;
     RECT  2.4 68.917 8.232 70.163 ;
     RECT  16.416 65.461 16.44 70.163 ;
     RECT  2.4 70.163 6.408 70.259 ;
     RECT  18.432 67.045 18.912 70.259 ;
     RECT  39.312 69.445 40.512 70.259 ;
     RECT  13.2 67.283 13.512 70.405 ;
     RECT  29.28 69.445 29.712 70.643 ;
     RECT  12.384 70.405 13.512 70.645 ;
     RECT  34.416 65.555 35.112 70.693 ;
     RECT  2.4 70.259 4.872 70.739 ;
     RECT  11.28 70.019 11.304 70.981 ;
     RECT  7.8 70.163 8.232 71.363 ;
     RECT  12.384 70.645 14.28 71.363 ;
     RECT  7.8 71.363 8.112 71.509 ;
     RECT  40.2 70.259 40.512 71.509 ;
     RECT  27.36 68.821 27.384 71.651 ;
     RECT  30.768 70.597 30.792 71.843 ;
     RECT  33.648 70.693 35.112 71.891 ;
     RECT  24 67.523 24.312 72.133 ;
     RECT  10.848 70.981 11.304 72.277 ;
     RECT  12.384 71.363 13.512 72.277 ;
     RECT  5.952 70.259 6.408 72.419 ;
     RECT  10.848 72.277 13.512 72.419 ;
     RECT  38.784 70.693 38.808 72.419 ;
     RECT  3.696 70.739 4.872 72.805 ;
     RECT  5.952 72.419 5.976 72.805 ;
     RECT  34.464 71.891 35.112 72.901 ;
     RECT  36.864 70.069 36.888 72.947 ;
     RECT  18.48 70.259 18.912 72.995 ;
     RECT  39.936 71.509 40.512 72.995 ;
     RECT  2.4 70.739 2.712 72.997 ;
     RECT  3.696 72.805 5.976 72.997 ;
     RECT  11.04 72.419 13.512 73.091 ;
     RECT  2.4 72.997 5.976 73.477 ;
     RECT  7.392 71.509 8.112 73.477 ;
     RECT  2.4 73.477 8.112 73.571 ;
     RECT  11.04 73.091 11.544 73.571 ;
     RECT  13.2 73.091 13.512 74.053 ;
     RECT  30.816 72.133 30.84 74.053 ;
     RECT  30.816 74.053 31.176 74.099 ;
     RECT  31.152 74.099 31.176 74.101 ;
     RECT  2.4 73.571 6.792 74.147 ;
     RECT  33.072 73.093 33.096 74.147 ;
     RECT  7.8 73.571 8.112 74.629 ;
     RECT  40.2 72.995 40.512 74.629 ;
     RECT  4.848 74.147 6.792 74.723 ;
     RECT  12.96 74.053 13.512 74.723 ;
     RECT  25.68 74.293 25.704 75.059 ;
     RECT  34.464 72.901 35.352 75.107 ;
     RECT  2.4 74.147 3.816 75.205 ;
     RECT  4.848 74.723 5.976 75.205 ;
     RECT  39.936 74.629 40.512 75.299 ;
     RECT  13.2 74.723 13.512 75.781 ;
     RECT  31.152 74.101 32.088 75.781 ;
     RECT  34.464 75.107 35.112 76.069 ;
     RECT  11.088 73.571 11.544 76.357 ;
     RECT  7.8 74.629 8.808 76.403 ;
     RECT  16.56 70.645 16.584 76.403 ;
     RECT  31.152 75.781 32.136 76.499 ;
     RECT  7.8 76.403 8.112 76.645 ;
     RECT  20.304 76.501 20.328 76.835 ;
     RECT  2.4 75.205 5.976 76.885 ;
     RECT  12.912 75.781 13.512 76.979 ;
     RECT  32.112 76.499 32.136 76.979 ;
     RECT  29.4 70.643 29.712 76.981 ;
     RECT  36.528 74.005 36.552 77.027 ;
     RECT  34.464 76.069 35.352 77.075 ;
     RECT  11.088 76.357 11.784 77.461 ;
     RECT  22.704 76.357 22.728 77.461 ;
     RECT  23.712 72.133 24.312 77.461 ;
     RECT  29.4 76.981 30.216 77.555 ;
     RECT  38.784 74.965 38.808 77.555 ;
     RECT  7.344 76.645 8.112 77.603 ;
     RECT  9.12 77.557 9.144 77.701 ;
     RECT  9.12 77.701 9.192 77.843 ;
     RECT  29.4 77.555 29.712 77.845 ;
     RECT  11.088 77.461 12.12 78.083 ;
     RECT  22.704 77.461 24.312 78.131 ;
     RECT  32.88 77.413 32.904 78.131 ;
     RECT  11.088 78.083 11.976 78.613 ;
     RECT  20.4 78.517 20.424 78.613 ;
     RECT  20.4 78.613 20.472 78.755 ;
     RECT  29.04 77.845 29.712 78.899 ;
     RECT  10.848 78.613 11.976 79.475 ;
     RECT  34.464 77.075 35.112 79.525 ;
     RECT  10.848 79.475 11.784 79.571 ;
     RECT  2.4 76.885 6.36 79.859 ;
     RECT  10.848 79.571 11.112 79.955 ;
     RECT  7.8 77.603 8.112 80.341 ;
     RECT  9.12 77.843 9.144 80.341 ;
     RECT  36.48 79.621 36.504 80.387 ;
     RECT  7.8 80.341 9.144 80.629 ;
     RECT  34.416 79.525 35.112 80.629 ;
     RECT  11.088 79.955 11.112 80.821 ;
     RECT  13.2 76.979 13.512 80.821 ;
     RECT  2.4 79.859 3.96 80.963 ;
     RECT  2.4 80.963 2.856 81.445 ;
     RECT  7.68 80.629 9.144 81.445 ;
     RECT  23.616 78.131 24.312 81.445 ;
     RECT  13.104 80.821 13.512 81.491 ;
     RECT  17.04 76.885 17.064 81.539 ;
     RECT  27.936 78.853 27.96 81.685 ;
     RECT  27.936 81.685 28.248 81.731 ;
     RECT  22.752 81.445 24.312 81.733 ;
     RECT  20.448 78.755 20.472 81.875 ;
     RECT  3.936 80.963 3.96 81.925 ;
     RECT  5.04 79.859 6.36 81.925 ;
     RECT  2.304 81.445 2.856 82.021 ;
     RECT  3.936 81.925 6.36 82.021 ;
     RECT  7.68 81.445 10.008 82.021 ;
     RECT  11.088 80.821 11.928 82.115 ;
     RECT  11.088 82.115 11.112 82.163 ;
     RECT  2.304 82.021 10.008 82.355 ;
     RECT  21.888 81.733 24.312 82.451 ;
     RECT  34.416 80.629 35.88 82.549 ;
     RECT  38.352 81.349 38.376 82.595 ;
     RECT  2.304 82.355 8.328 82.691 ;
     RECT  19.92 82.597 19.944 82.739 ;
     RECT  21.888 82.451 21.912 82.739 ;
     RECT  12.192 82.309 12.216 82.789 ;
     RECT  13.2 81.491 13.512 82.789 ;
     RECT  10.992 82.453 11.016 83.125 ;
     RECT  12.192 82.789 13.512 83.125 ;
     RECT  2.304 82.691 4.536 83.267 ;
     RECT  5.52 82.691 8.328 83.507 ;
     RECT  28.032 81.731 28.248 83.507 ;
     RECT  10.992 83.125 13.512 83.557 ;
     RECT  29.4 78.899 29.712 83.605 ;
     RECT  28.224 83.507 28.248 83.651 ;
     RECT  18.6 72.995 18.912 83.749 ;
     RECT  19.968 83.173 19.992 83.749 ;
     RECT  3.936 83.267 3.96 83.843 ;
     RECT  9.504 82.355 10.008 83.941 ;
     RECT  10.992 83.557 14.232 83.941 ;
     RECT  9.504 83.941 14.232 84.037 ;
     RECT  5.52 83.507 6.072 84.323 ;
     RECT  15.6 83.749 15.624 84.325 ;
     RECT  5.664 84.323 6.072 84.419 ;
     RECT  18.6 83.749 19.992 84.467 ;
     RECT  15.6 84.325 16.584 84.611 ;
     RECT  7.8 83.507 8.328 84.853 ;
     RECT  23.616 82.451 24.312 84.853 ;
     RECT  9.504 84.037 14.616 85.139 ;
     RECT  7.8 84.853 8.52 85.381 ;
     RECT  19.968 84.467 19.992 85.381 ;
     RECT  19.968 85.381 20.232 85.427 ;
     RECT  7.584 85.381 8.52 85.523 ;
     RECT  7.584 85.523 8.328 85.765 ;
     RECT  26.064 83.605 26.088 85.955 ;
     RECT  20.208 85.427 20.232 86.005 ;
     RECT  21.984 85.477 22.008 86.005 ;
     RECT  23.328 84.853 24.312 86.099 ;
     RECT  20.208 86.005 22.008 86.195 ;
     RECT  7.056 85.765 8.328 86.531 ;
     RECT  29.4 83.605 30.168 86.533 ;
     RECT  20.208 86.195 21.096 86.723 ;
     RECT  7.056 86.531 8.112 86.725 ;
     RECT  34.416 82.549 36.264 86.725 ;
     RECT  4.272 85.765 4.296 86.771 ;
     RECT  16.56 84.611 16.584 86.771 ;
     RECT  23.616 86.099 24.312 86.771 ;
     RECT  34.224 86.725 36.264 86.771 ;
     RECT  29.04 86.533 30.168 86.821 ;
     RECT  26.688 86.533 26.712 87.109 ;
     RECT  26.064 87.109 26.712 87.157 ;
     RECT  9.504 85.139 14.232 87.251 ;
     RECT  28.848 86.821 30.168 87.299 ;
     RECT  33.216 86.245 33.24 87.347 ;
     RECT  28.992 87.299 30.168 87.443 ;
     RECT  29.088 87.443 30.168 87.587 ;
     RECT  26.064 87.157 26.808 87.781 ;
     RECT  5.664 84.419 5.688 87.827 ;
     RECT  20.208 86.723 20.808 87.827 ;
     RECT  9.6 87.251 13.656 87.971 ;
     RECT  26.064 87.781 27.576 87.971 ;
     RECT  9.6 87.971 13.608 88.115 ;
     RECT  20.784 87.827 20.808 88.115 ;
     RECT  6.864 86.725 8.112 88.403 ;
     RECT  9.6 88.115 13.512 88.403 ;
     RECT  26.064 87.971 26.808 88.403 ;
     RECT  36.24 86.771 36.264 88.403 ;
     RECT  9.6 88.403 11.208 88.741 ;
     RECT  26.784 88.403 26.808 88.931 ;
     RECT  34.224 86.771 35.112 89.315 ;
     RECT  7.248 88.403 8.112 89.461 ;
     RECT  9.168 88.741 11.208 89.555 ;
     RECT  22.8 89.509 22.824 89.747 ;
     RECT  29.4 87.587 30.168 89.749 ;
     RECT  9.168 89.555 10.824 89.891 ;
     RECT  28.224 89.461 28.248 90.083 ;
     RECT  6.864 89.461 8.112 90.131 ;
     RECT  12.24 88.403 13.512 90.515 ;
     RECT  29.4 89.749 30.36 90.515 ;
     RECT  2.4 83.267 2.712 90.729 ;
     RECT  7.8 90.131 8.112 90.729 ;
     RECT  13.2 90.515 13.512 90.729 ;
     RECT  18.6 84.467 18.912 90.729 ;
     RECT  24 86.771 24.312 90.729 ;
     RECT  29.4 90.515 29.712 90.729 ;
     RECT  34.8 89.315 35.112 90.729 ;
     RECT  40.2 75.299 40.512 90.729 ;
     RECT  2.4 90.729 2.52 90.743 ;
     RECT  7.8 90.729 7.92 90.743 ;
     RECT  13.2 90.729 13.32 90.743 ;
     RECT  18.6 90.729 18.72 90.743 ;
     RECT  24 90.729 24.12 90.743 ;
     RECT  29.4 90.729 29.52 90.743 ;
     RECT  34.8 90.729 34.92 90.743 ;
     RECT  40.2 90.729 40.32 90.743 ;
     RECT  9.168 89.891 10.776 91.141 ;
     RECT  9.168 91.141 10.92 91.189 ;
     RECT  9.024 91.189 10.92 91.237 ;
     RECT  9.024 91.237 11.064 92.629 ;
     RECT  9.024 92.629 11.208 92.752 ;
     RECT  28.248 2.245 29.4 5.747 ;
     RECT  3.336 2.821 4.608 3.107 ;
     RECT  19.032 2.821 20.496 4.115 ;
     RECT  3.336 3.107 5.76 3.587 ;
     RECT  37.416 3.301 38.4 3.685 ;
     RECT  5.784 3.349 7.056 3.587 ;
     RECT  8.856 3.397 9.888 3.733 ;
     RECT  3.336 3.587 4.872 3.829 ;
     RECT  18.48 3.827 18.6 5.029 ;
     RECT  3.336 3.829 4.56 4.115 ;
     RECT  4.584 3.829 4.872 5.077 ;
     RECT  2.712 4.115 4.56 5.173 ;
     RECT  18.912 4.115 20.496 5.125 ;
     RECT  11.256 4.643 12.576 4.739 ;
     RECT  22.776 4.645 24 5.891 ;
     RECT  19.032 5.125 20.496 5.795 ;
     RECT  3.48 5.173 4.56 5.653 ;
     RECT  34.224 5.219 34.8 6.613 ;
     RECT  13.056 5.459 13.2 6.805 ;
     RECT  3.48 5.653 4.512 6.275 ;
     RECT  23.904 5.891 24 6.805 ;
     RECT  15.36 6.323 15.6 6.709 ;
     RECT  33.336 6.613 34.8 8.485 ;
     RECT  14.184 6.709 15.6 8.003 ;
     RECT  35.112 6.899 35.448 7.861 ;
     RECT  38.232 7.475 38.376 8.677 ;
     RECT  11.976 8.485 12.96 8.627 ;
     RECT  24.312 8.485 25.68 9.205 ;
     RECT  33.768 8.485 34.8 10.739 ;
     RECT  18.24 8.579 18.48 9.637 ;
     RECT  11.976 8.627 13.2 10.067 ;
     RECT  38.808 8.677 40.2 9.779 ;
     RECT  37.416 8.723 38.784 9.779 ;
     RECT  20.52 8.821 21.84 10.307 ;
     RECT  21.864 8.821 22.944 8.867 ;
     RECT  29.712 9.107 31.104 10.883 ;
     RECT  24.312 9.205 25.392 9.779 ;
     RECT  11.256 10.067 13.2 10.693 ;
     RECT  18.192 10.211 18.6 11.221 ;
     RECT  11.256 10.693 13.104 10.931 ;
     RECT  33.336 10.739 34.8 12.757 ;
     RECT  29.712 10.883 31.128 11.269 ;
     RECT  11.256 10.931 11.592 11.365 ;
     RECT  18.912 10.981 19.968 12.563 ;
     RECT  29.712 11.269 31.056 12.563 ;
     RECT  31.08 11.269 31.128 11.317 ;
     RECT  31.08 11.317 32.304 11.987 ;
     RECT  32.328 11.317 33.312 11.987 ;
     RECT  26.232 11.411 26.616 12.035 ;
     RECT  29.232 11.411 29.4 12.517 ;
     RECT  6.864 11.987 7.392 13.045 ;
     RECT  31.08 11.987 33.312 12.563 ;
     RECT  25.944 12.035 26.616 12.275 ;
     RECT  24.408 12.229 25.92 12.275 ;
     RECT  24.408 12.275 26.616 12.517 ;
     RECT  24.408 12.517 27.648 13.045 ;
     RECT  31.872 12.563 33.312 13.045 ;
     RECT  5.976 13.045 7.392 14.197 ;
     RECT  25.128 13.045 27.648 13.333 ;
     RECT  31.872 13.045 32.448 13.573 ;
     RECT  25.128 13.333 26.352 14.387 ;
     RECT  26.376 13.333 27.648 13.715 ;
     RECT  13.656 13.573 14.928 14.965 ;
     RECT  17.712 13.715 18 14.485 ;
     RECT  29.232 13.811 29.28 15.301 ;
     RECT  19.176 14.101 20.496 14.915 ;
     RECT  33.336 14.147 34.8 17.605 ;
     RECT  5.976 14.197 7.152 14.243 ;
     RECT  5.952 14.243 7.152 14.915 ;
     RECT  16.872 14.485 18 16.019 ;
     RECT  15.624 14.627 16.848 16.019 ;
     RECT  2.712 14.773 4.032 15.635 ;
     RECT  5.952 14.915 7.392 15.445 ;
     RECT  31.896 14.915 33.312 15.443 ;
     RECT  13.752 14.965 14.928 15.203 ;
     RECT  13.656 15.203 14.928 15.395 ;
     RECT  39.216 15.347 40.2 15.973 ;
     RECT  15.456 15.395 15.6 16.501 ;
     RECT  35.976 15.397 37.248 17.029 ;
     RECT  5.976 15.445 7.392 16.933 ;
     RECT  2.712 15.635 2.856 17.077 ;
     RECT  38.856 15.973 40.2 16.547 ;
     RECT  17.76 16.019 18 16.501 ;
     RECT  29.28 16.307 29.4 17.509 ;
     RECT  37.272 16.501 38.736 17.653 ;
     RECT  38.76 16.547 40.2 18.227 ;
     RECT  26.52 16.643 26.616 17.605 ;
     RECT  18.912 16.981 19.968 20.003 ;
     RECT  20.136 17.027 20.52 18.133 ;
     RECT  35.112 17.075 36.48 17.699 ;
     RECT  22.536 17.171 24 17.699 ;
     RECT  5.976 17.603 7.584 19.093 ;
     RECT  33.336 17.605 34.56 18.419 ;
     RECT  37.32 17.653 38.736 18.227 ;
     RECT  2.712 17.699 2.856 18.757 ;
     RECT  35.112 17.699 35.352 18.133 ;
     RECT  33.336 18.419 34.8 20.723 ;
     RECT  12.024 18.709 13.2 19.765 ;
     RECT  6.312 19.093 7.584 20.533 ;
     RECT  18.912 20.003 20.016 20.533 ;
     RECT  6.408 20.533 7.584 21.395 ;
     RECT  19.032 20.533 20.016 21.827 ;
     RECT  20.04 21.155 20.472 21.875 ;
     RECT  24.312 21.155 25.08 22.021 ;
     RECT  27.672 21.637 29.04 22.499 ;
     RECT  29.712 21.683 30.816 23.411 ;
     RECT  35.112 21.685 36.432 22.883 ;
     RECT  18.912 21.827 20.016 21.875 ;
     RECT  20.448 21.875 20.472 22.165 ;
     RECT  24.312 22.021 25.632 22.165 ;
     RECT  24.504 22.165 25.632 23.891 ;
     RECT  11.256 22.499 12.384 25.475 ;
     RECT  38.712 22.597 40.2 24.083 ;
     RECT  33.528 22.693 34.8 25.187 ;
     RECT  37.32 22.787 38.688 24.083 ;
     RECT  32.52 23.029 33.504 24.707 ;
     RECT  5.136 23.123 5.856 23.317 ;
     RECT  16.584 23.173 17.664 23.219 ;
     RECT  16.584 23.219 17.856 23.699 ;
     RECT  5.88 23.269 7.056 24.131 ;
     RECT  4.632 23.317 5.856 24.131 ;
     RECT  29.712 23.411 30.456 23.893 ;
     RECT  16.584 23.699 18 23.987 ;
     RECT  24.456 23.891 25.632 28.453 ;
     RECT  15.624 23.987 18 25.045 ;
     RECT  37.32 24.083 38.184 24.805 ;
     RECT  5.88 24.131 7.584 24.805 ;
     RECT  14.232 24.469 15.6 25.525 ;
     RECT  35.208 24.517 36.288 25.955 ;
     RECT  36.312 24.517 37.296 25.955 ;
     RECT  6.024 24.805 7.584 25.333 ;
     RECT  15.624 25.045 17.088 26.819 ;
     RECT  6.024 25.333 7.392 25.475 ;
     RECT  6.024 25.475 7.488 26.053 ;
     RECT  14.232 25.525 15.504 26.243 ;
     RECT  21.624 25.571 21.768 26.677 ;
     RECT  2.712 25.955 3.84 27.059 ;
     RECT  6.072 26.053 7.488 27.059 ;
     RECT  22.056 26.677 23.568 26.723 ;
     RECT  15.624 26.819 18 27.493 ;
     RECT  29.712 26.819 31.152 27.829 ;
     RECT  6.024 27.059 7.488 27.203 ;
     RECT  6.024 27.203 7.584 27.347 ;
     RECT  7.392 27.347 7.584 28.453 ;
     RECT  15.816 27.493 18 27.877 ;
     RECT  29.712 27.829 30.816 28.021 ;
     RECT  15.816 27.877 16.992 27.971 ;
     RECT  17.016 27.877 18 28.789 ;
     RECT  15.624 27.971 16.992 28.979 ;
     RECT  29.712 28.021 30.72 28.259 ;
     RECT  29.712 28.259 30.816 28.691 ;
     RECT  29.712 28.691 31.248 29.605 ;
     RECT  18.912 28.837 19.968 29.699 ;
     RECT  15.624 28.979 17.088 28.981 ;
     RECT  15.816 28.981 17.088 29.699 ;
     RECT  11.976 29.605 12.96 30.851 ;
     RECT  30.216 29.605 31.248 29.795 ;
     RECT  15.624 29.699 17.088 30.035 ;
     RECT  18.912 29.699 19.992 30.229 ;
     RECT  37.32 29.699 37.944 29.893 ;
     RECT  24.504 29.795 25.632 30.323 ;
     RECT  30.216 29.795 31.296 30.851 ;
     RECT  37.32 29.893 38.688 30.659 ;
     RECT  38.712 29.893 40.2 31.331 ;
     RECT  18.912 30.229 20.304 32.483 ;
     RECT  20.328 30.229 21.6 32.483 ;
     RECT  22.824 30.661 24 31.669 ;
     RECT  11.976 30.851 13.2 31.379 ;
     RECT  21.624 30.899 22.8 33.107 ;
     RECT  6.36 31.861 7.392 31.907 ;
     RECT  6.36 31.907 7.584 34.259 ;
     RECT  15.624 32.149 17.088 34.355 ;
     RECT  22.824 32.339 24 33.107 ;
     RECT  24.792 33.013 26.208 33.875 ;
     RECT  2.712 33.637 4.224 34.355 ;
     RECT  4.248 33.637 5.568 34.355 ;
     RECT  17.808 34.355 18 35.317 ;
     RECT  32.16 34.835 32.592 35.557 ;
     RECT  27.816 35.029 29.136 35.845 ;
     RECT  31.32 35.557 32.592 37.571 ;
     RECT  27.816 35.845 28.896 36.515 ;
     RECT  21.624 35.989 22.992 37.619 ;
     RECT  23.016 35.989 24 37.619 ;
     RECT  24.312 36.035 25.392 36.803 ;
     RECT  24.312 36.803 25.416 37.573 ;
     RECT  18.912 37.477 20.208 38.675 ;
     RECT  20.232 37.477 21.6 38.675 ;
     RECT  24.312 37.573 25.488 38.245 ;
     RECT  21.624 37.619 22.2 39.061 ;
     RECT  34.224 37.619 34.8 39.061 ;
     RECT  24.408 38.245 25.488 38.627 ;
     RECT  24.312 38.627 25.488 40.693 ;
     RECT  18.912 38.675 19.704 39.877 ;
     RECT  38.808 38.677 40.2 39.205 ;
     RECT  38.808 39.205 40.08 39.443 ;
     RECT  16.344 39.301 17.664 39.973 ;
     RECT  22.872 40.261 24 40.787 ;
     RECT  21.624 40.355 22.848 40.787 ;
     RECT  4.824 40.405 6.288 42.227 ;
     RECT  6.312 40.405 7.584 42.227 ;
     RECT  29.712 41.411 30.312 42.709 ;
     RECT  14.52 41.557 15.6 42.181 ;
     RECT  25.512 41.605 26.784 42.083 ;
     RECT  11.256 41.651 11.448 42.709 ;
     RECT  26.496 42.083 26.784 42.373 ;
     RECT  14.28 42.467 15.6 45.635 ;
     RECT  11.736 42.709 13.008 44.099 ;
     RECT  29.712 42.709 30.816 44.965 ;
     RECT  11.736 44.099 13.2 46.211 ;
     RECT  30.84 44.389 32.208 45.059 ;
     RECT  18.912 44.725 20.256 46.931 ;
     RECT  20.28 44.725 21.6 46.645 ;
     RECT  25.128 44.965 26.496 45.395 ;
     RECT  12.96 46.211 13.2 46.645 ;
     RECT  20.28 46.645 21.36 46.931 ;
     RECT  18.912 46.931 21.36 47.845 ;
     RECT  38.664 47.317 40.08 48.853 ;
     RECT  4.296 47.845 5.28 48.659 ;
     RECT  18.912 47.845 19.92 50.101 ;
     RECT  19.944 47.845 21.36 50.147 ;
     RECT  29.088 48.371 29.28 49.525 ;
     RECT  8.112 48.419 9.168 51.253 ;
     RECT  3.48 48.659 5.304 48.805 ;
     RECT  3.48 48.805 4.512 50.677 ;
     RECT  5.064 48.805 5.304 50.053 ;
     RECT  38.76 48.853 40.08 49.571 ;
     RECT  21.624 50.101 22.608 51.251 ;
     RECT  22.632 50.101 24 51.205 ;
     RECT  35.112 50.389 36.336 50.677 ;
     RECT  10.776 50.677 11.808 50.723 ;
     RECT  11.832 50.677 13.2 54.035 ;
     RECT  13.656 50.677 14.784 50.771 ;
     RECT  35.304 50.677 36.336 51.923 ;
     RECT  13.512 50.771 14.784 51.395 ;
     RECT  24.312 50.963 25.08 51.781 ;
     RECT  22.776 51.205 24 52.547 ;
     RECT  21.624 51.251 22.752 52.547 ;
     RECT  24.312 51.781 25.68 54.755 ;
     RECT  18.912 52.885 20.016 53.555 ;
     RECT  6.12 52.981 7.488 53.171 ;
     RECT  33.672 52.981 34.8 53.795 ;
     RECT  38.856 53.221 40.08 54.179 ;
     RECT  20.52 53.509 21.6 56.483 ;
     RECT  33.696 53.795 34.8 54.133 ;
     RECT  12.48 54.035 13.2 54.661 ;
     RECT  28.104 54.085 29.088 54.853 ;
     RECT  33.72 54.133 34.8 54.707 ;
     RECT  38.328 54.179 40.08 54.565 ;
     RECT  38.328 54.565 39.312 55.571 ;
     RECT  24.312 54.755 25.656 55.717 ;
     RECT  29.712 54.853 30.768 56.771 ;
     RECT  30.792 55.045 31.872 56.243 ;
     RECT  19.272 55.621 20.496 56.437 ;
     RECT  24.312 55.717 25.632 57.059 ;
     RECT  12.768 56.483 13.2 57.829 ;
     RECT  30.216 58.645 31.44 59.459 ;
     RECT  5.832 59.125 6.816 61.573 ;
     RECT  21.624 59.749 22.944 60.851 ;
     RECT  22.968 59.749 24 60.851 ;
     RECT  3.96 59.939 5.04 61.237 ;
     RECT  35.112 60.373 36.432 62.195 ;
     RECT  11.4 60.949 12.528 62.195 ;
     RECT  14.424 60.949 15.408 61.043 ;
     RECT  24.312 60.949 25.44 61.477 ;
     RECT  14.424 61.043 15.84 62.195 ;
     RECT  3.96 61.237 4.944 64.933 ;
     RECT  24.456 61.477 25.44 62.195 ;
     RECT  11.4 62.195 12.768 62.771 ;
     RECT  13.512 62.195 15.84 62.821 ;
     RECT  24.408 62.195 25.44 62.771 ;
     RECT  11.376 62.771 12.768 63.205 ;
     RECT  24.408 62.771 24.456 63.829 ;
     RECT  13.512 62.821 14.928 63.827 ;
     RECT  8.232 63.109 9.456 64.931 ;
     RECT  11.256 63.205 12.768 63.781 ;
     RECT  6.312 63.539 7.296 64.835 ;
     RECT  29.712 64.309 30.816 66.179 ;
     RECT  28.152 64.595 29.4 65.603 ;
     RECT  7.152 64.835 7.296 66.181 ;
     RECT  21.144 65.603 22.368 65.795 ;
     RECT  27.96 65.603 29.4 66.899 ;
     RECT  3.912 65.651 4.944 66.613 ;
     RECT  21 65.795 22.368 66.515 ;
     RECT  38.808 66.133 40.2 67.859 ;
     RECT  29.712 66.179 30.792 66.469 ;
     RECT  29.712 66.611 30.768 66.755 ;
     RECT  3.96 66.613 4.944 67.283 ;
     RECT  5.736 67.141 7.152 67.765 ;
     RECT  3.96 67.283 5.472 67.331 ;
     RECT  11.784 67.283 13.2 68.387 ;
     RECT  3.864 67.331 5.472 68.821 ;
     RECT  8.232 68.245 9.648 69.491 ;
     RECT  9.672 68.245 11.04 68.435 ;
     RECT  3.864 68.821 4.848 68.917 ;
     RECT  13.512 68.917 14.64 69.731 ;
     RECT  11.448 69.011 11.592 70.019 ;
     RECT  13.512 69.731 14.28 70.645 ;
     RECT  11.304 70.019 11.592 70.405 ;
     RECT  6.408 70.163 7.8 71.509 ;
     RECT  4.872 70.259 5.952 72.805 ;
     RECT  39.312 70.259 40.2 70.693 ;
     RECT  11.304 70.405 12.384 72.277 ;
     RECT  29.712 70.597 30.768 71.843 ;
     RECT  38.808 70.693 40.2 71.509 ;
     RECT  2.712 70.739 3.696 72.997 ;
     RECT  6.408 71.509 7.392 72.419 ;
     RECT  38.808 71.509 39.936 72.419 ;
     RECT  29.712 71.843 30.792 72.133 ;
     RECT  33.648 71.891 34.464 73.093 ;
     RECT  29.712 72.133 30.816 74.099 ;
     RECT  5.976 72.419 7.392 73.477 ;
     RECT  35.352 72.901 36.864 72.947 ;
     RECT  35.352 72.947 36.552 74.005 ;
     RECT  11.544 73.091 13.2 74.053 ;
     RECT  33.096 73.093 34.464 74.147 ;
     RECT  6.792 73.571 7.8 74.723 ;
     RECT  35.352 74.005 36.528 75.107 ;
     RECT  11.544 74.053 12.96 74.723 ;
     RECT  29.712 74.099 31.152 76.499 ;
     RECT  32.088 74.101 33.072 74.147 ;
     RECT  3.816 74.147 4.848 75.205 ;
     RECT  24.312 74.293 25.68 75.059 ;
     RECT  11.544 74.723 13.2 75.781 ;
     RECT  38.808 74.965 39.936 75.299 ;
     RECT  35.112 75.107 36.528 76.069 ;
     RECT  38.808 75.299 40.2 77.555 ;
     RECT  11.544 75.781 12.912 76.357 ;
     RECT  35.352 76.069 36.528 77.027 ;
     RECT  11.784 76.357 12.912 76.979 ;
     RECT  22.728 76.357 23.712 77.461 ;
     RECT  8.112 76.403 8.808 77.557 ;
     RECT  29.712 76.499 30.216 76.981 ;
     RECT  18.912 76.501 20.304 76.835 ;
     RECT  5.976 76.645 7.344 76.885 ;
     RECT  6.36 76.885 7.344 77.603 ;
     RECT  11.784 76.979 13.2 77.461 ;
     RECT  12.12 77.461 13.2 78.083 ;
     RECT  8.112 77.557 9.12 80.341 ;
     RECT  6.36 77.603 7.8 80.629 ;
     RECT  11.976 78.083 13.2 79.475 ;
     RECT  18.912 78.517 20.4 78.755 ;
     RECT  27.96 78.853 29.04 78.899 ;
     RECT  27.96 78.899 29.4 81.685 ;
     RECT  11.784 79.475 13.2 79.571 ;
     RECT  11.112 79.571 13.2 80.821 ;
     RECT  35.112 79.621 36.48 80.387 ;
     RECT  3.96 79.859 5.04 81.925 ;
     RECT  10.848 79.955 11.088 81.445 ;
     RECT  35.112 80.387 35.88 80.629 ;
     RECT  6.36 80.629 7.68 82.021 ;
     RECT  11.928 80.821 13.104 81.491 ;
     RECT  2.856 80.963 3.936 82.021 ;
     RECT  10.008 81.445 11.088 82.163 ;
     RECT  11.928 81.491 13.2 82.115 ;
     RECT  28.248 81.685 29.4 83.651 ;
     RECT  20.472 81.733 21.888 81.875 ;
     RECT  11.112 82.115 13.2 82.163 ;
     RECT  10.008 82.163 13.2 82.309 ;
     RECT  10.008 82.309 12.192 82.453 ;
     RECT  12.216 82.309 13.2 82.789 ;
     RECT  8.328 82.355 9.504 84.853 ;
     RECT  10.008 82.453 10.992 83.941 ;
     RECT  11.016 82.453 12.192 83.125 ;
     RECT  18.912 82.597 19.92 82.739 ;
     RECT  4.536 82.691 5.52 83.267 ;
     RECT  18.912 82.739 19.944 83.173 ;
     RECT  18.912 83.173 19.968 83.749 ;
     RECT  2.712 83.267 3.936 83.843 ;
     RECT  14.232 83.749 15.6 84.037 ;
     RECT  14.616 84.037 15.6 84.611 ;
     RECT  5.52 84.323 5.664 85.765 ;
     RECT  5.688 84.419 6.072 85.381 ;
     RECT  18.912 84.467 19.968 85.427 ;
     RECT  8.52 84.853 9.504 85.523 ;
     RECT  5.688 85.381 7.584 85.765 ;
     RECT  18.912 85.427 20.208 87.827 ;
     RECT  22.008 85.477 23.328 86.099 ;
     RECT  8.328 85.523 9.504 86.531 ;
     RECT  4.296 85.765 5.664 86.771 ;
     RECT  5.688 85.765 7.056 86.725 ;
     RECT  26.064 85.955 26.088 86.533 ;
     RECT  33.24 86.245 34.416 86.725 ;
     RECT  8.112 86.531 9.504 87.251 ;
     RECT  26.064 86.533 26.688 87.109 ;
     RECT  5.688 86.725 6.864 87.827 ;
     RECT  33.24 86.725 34.224 87.347 ;
     RECT  35.112 86.771 36.24 88.403 ;
     RECT  8.112 87.251 9.6 88.741 ;
     RECT  6.864 88.403 7.248 89.461 ;
     RECT  11.208 88.403 12.24 89.555 ;
     RECT  8.112 88.741 9.168 90.729 ;
     RECT  28.248 89.461 29.4 90.083 ;
     RECT  22.824 89.509 24 89.747 ;
     RECT  10.824 89.555 12.24 89.891 ;
     RECT  10.776 89.891 12.24 90.515 ;
     RECT  10.776 90.515 11.064 91.141 ;
     RECT  7.92 90.729 9.168 90.743 ;
     RECT  9.024 90.743 9.168 91.189 ;
     RECT  10.92 91.141 11.064 91.237 ;
  END
END ot_s81_markov_chunk5_native
END LIBRARY
